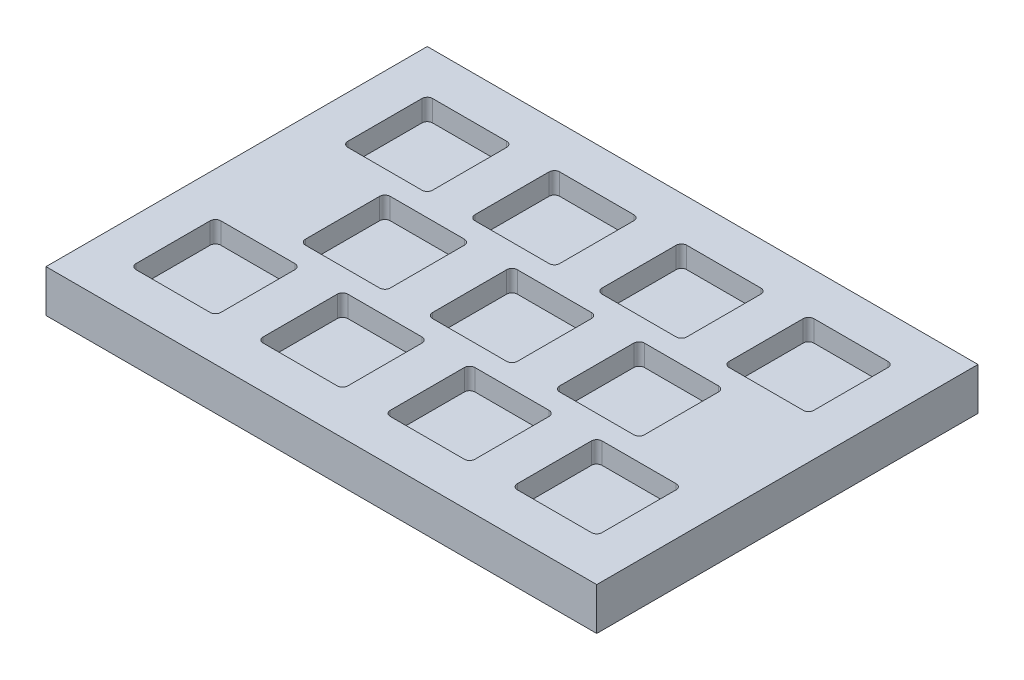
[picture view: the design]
ISO-10303-21;
HEADER;
FILE_DESCRIPTION(('STEP AP214'),'2;1');
FILE_NAME('part.step','',(''),(''),'','','');
FILE_SCHEMA(('AUTOMOTIVE_DESIGN { 1 0 10303 214 1 1 1 1 }'));
ENDSEC;
DATA;
#1=APPLICATION_CONTEXT('core data for automotive mechanical design processes');
#2=APPLICATION_PROTOCOL_DEFINITION('international standard','automotive_design',2000,#1);
#3=PRODUCT_CONTEXT('',#1,'mechanical');
#4=PRODUCT('Part','Part','',(#3));
#5=PRODUCT_RELATED_PRODUCT_CATEGORY('part','',(#4));
#6=PRODUCT_DEFINITION_FORMATION('','',#4);
#7=PRODUCT_DEFINITION_CONTEXT('part definition',#1,'design');
#8=PRODUCT_DEFINITION('design','',#6,#7);
#9=PRODUCT_DEFINITION_SHAPE('','',#8);
#10=(LENGTH_UNIT() NAMED_UNIT(*) SI_UNIT(.MILLI.,.METRE.));
#11=(NAMED_UNIT(*) PLANE_ANGLE_UNIT() SI_UNIT($,.RADIAN.));
#12=(NAMED_UNIT(*) SI_UNIT($,.STERADIAN.) SOLID_ANGLE_UNIT());
#13=UNCERTAINTY_MEASURE_WITH_UNIT(LENGTH_MEASURE(1.E-05),#10,'distance_accuracy_value','');
#14=(GEOMETRIC_REPRESENTATION_CONTEXT(3) GLOBAL_UNCERTAINTY_ASSIGNED_CONTEXT((#13)) GLOBAL_UNIT_ASSIGNED_CONTEXT((#10,
#11,#12)) REPRESENTATION_CONTEXT('',''));
#15=CARTESIAN_POINT('',(0.,0.,0.));
#16=DIRECTION('',(0.,0.,1.));
#17=DIRECTION('',(1.,0.,0.));
#18=AXIS2_PLACEMENT_3D('',#15,#16,#17);
#19=CARTESIAN_POINT('',(-82.55,12.7,57.15));
#20=DIRECTION('',(0.,1.,0.));
#21=DIRECTION('',(0.,0.,1.));
#22=AXIS2_PLACEMENT_3D('',#19,#20,#21);
#23=PLANE('',#22);
#24=DIRECTION('',(0.,0.,1.));
#25=VECTOR('',#24,1.);
#26=CARTESIAN_POINT('',(-82.55,12.7,-57.15));
#27=LINE('',#26,#25);
#28=CARTESIAN_POINT('',(-82.55,12.7,-57.15));
#29=VERTEX_POINT('',#28);
#30=CARTESIAN_POINT('',(-82.55,12.7,57.15));
#31=VERTEX_POINT('',#30);
#32=EDGE_CURVE('E902',#29,#31,#27,.T.);
#33=ORIENTED_EDGE('',*,*,#32,.T.);
#34=DIRECTION('',(1.,0.,0.));
#35=VECTOR('',#34,1.);
#36=CARTESIAN_POINT('',(-82.55,12.7,57.15));
#37=LINE('',#36,#35);
#38=CARTESIAN_POINT('',(82.55,12.7,57.15));
#39=VERTEX_POINT('',#38);
#40=EDGE_CURVE('E905',#31,#39,#37,.T.);
#41=ORIENTED_EDGE('',*,*,#40,.T.);
#42=DIRECTION('',(0.,0.,-1.));
#43=VECTOR('',#42,1.);
#44=CARTESIAN_POINT('',(82.55,12.7,-57.15));
#45=LINE('',#44,#43);
#46=CARTESIAN_POINT('',(82.55,12.7,-57.15));
#47=VERTEX_POINT('',#46);
#48=EDGE_CURVE('E907',#39,#47,#45,.T.);
#49=ORIENTED_EDGE('',*,*,#48,.T.);
#50=DIRECTION('',(-1.,0.,0.));
#51=VECTOR('',#50,1.);
#52=CARTESIAN_POINT('',(-82.55,12.7,-57.15));
#53=LINE('',#52,#51);
#54=EDGE_CURVE('E909',#47,#29,#53,.T.);
#55=ORIENTED_EDGE('',*,*,#54,.T.);
#56=EDGE_LOOP('',(#33,#41,#49,#55));
#57=FACE_BOUND('',#56,.T.);
#58=DIRECTION('',(0.,0.,-1.));
#59=VECTOR('',#58,1.);
#60=CARTESIAN_POINT('',(-44.45,12.7,-44.45));
#61=LINE('',#60,#59);
#62=CARTESIAN_POINT('',(-44.45,12.7,-20.6375));
#63=VERTEX_POINT('',#62);
#64=CARTESIAN_POINT('',(-44.45,12.7,-42.8625));
#65=VERTEX_POINT('',#64);
#66=EDGE_CURVE('E869',#63,#65,#61,.T.);
#67=ORIENTED_EDGE('',*,*,#66,.F.);
#68=CARTESIAN_POINT('',(-46.0375,12.7,-20.6375));
#69=DIRECTION('',(0.,1.,0.));
#70=DIRECTION('',(0.,0.,1.));
#71=AXIS2_PLACEMENT_3D('',#68,#69,#70);
#72=CIRCLE('',#71,1.5875);
#73=CARTESIAN_POINT('',(-46.0375,12.7,-19.05));
#74=VERTEX_POINT('',#73);
#75=EDGE_CURVE('E953',#63,#74,#72,.F.);
#76=ORIENTED_EDGE('',*,*,#75,.T.);
#77=DIRECTION('',(1.,0.,0.));
#78=VECTOR('',#77,1.);
#79=CARTESIAN_POINT('',(-44.45,12.7,-19.05));
#80=LINE('',#79,#78);
#81=CARTESIAN_POINT('',(-68.2625,12.7,-19.05));
#82=VERTEX_POINT('',#81);
#83=EDGE_CURVE('E878',#82,#74,#80,.T.);
#84=ORIENTED_EDGE('',*,*,#83,.F.);
#85=CARTESIAN_POINT('',(-68.2625,12.7,-20.6375));
#86=DIRECTION('',(0.,1.,0.));
#87=DIRECTION('',(0.,0.,1.));
#88=AXIS2_PLACEMENT_3D('',#85,#86,#87);
#89=CIRCLE('',#88,1.5875);
#90=CARTESIAN_POINT('',(-69.85,12.7,-20.6375));
#91=VERTEX_POINT('',#90);
#92=EDGE_CURVE('E951',#82,#91,#89,.F.);
#93=ORIENTED_EDGE('',*,*,#92,.T.);
#94=DIRECTION('',(0.,0.,1.));
#95=VECTOR('',#94,1.);
#96=CARTESIAN_POINT('',(-69.85,12.7,-44.45));
#97=LINE('',#96,#95);
#98=CARTESIAN_POINT('',(-69.85,12.7,-42.8625));
#99=VERTEX_POINT('',#98);
#100=EDGE_CURVE('E875',#99,#91,#97,.T.);
#101=ORIENTED_EDGE('',*,*,#100,.F.);
#102=CARTESIAN_POINT('',(-68.2625,12.7,-42.8625));
#103=DIRECTION('',(0.,1.,0.));
#104=DIRECTION('',(0.,0.,1.));
#105=AXIS2_PLACEMENT_3D('',#102,#103,#104);
#106=CIRCLE('',#105,1.5875);
#107=CARTESIAN_POINT('',(-68.2625,12.7,-44.45));
#108=VERTEX_POINT('',#107);
#109=EDGE_CURVE('E957',#99,#108,#106,.F.);
#110=ORIENTED_EDGE('',*,*,#109,.T.);
#111=DIRECTION('',(-1.,0.,0.));
#112=VECTOR('',#111,1.);
#113=CARTESIAN_POINT('',(-44.45,12.7,-44.45));
#114=LINE('',#113,#112);
#115=CARTESIAN_POINT('',(-46.0375,12.7,-44.45));
#116=VERTEX_POINT('',#115);
#117=EDGE_CURVE('E872',#116,#108,#114,.T.);
#118=ORIENTED_EDGE('',*,*,#117,.F.);
#119=CARTESIAN_POINT('',(-46.0375,12.7,-42.8625));
#120=DIRECTION('',(0.,1.,0.));
#121=DIRECTION('',(0.,0.,1.));
#122=AXIS2_PLACEMENT_3D('',#119,#120,#121);
#123=CIRCLE('',#122,1.5875);
#124=EDGE_CURVE('E955',#116,#65,#123,.F.);
#125=ORIENTED_EDGE('',*,*,#124,.T.);
#126=EDGE_LOOP('',(#67,#76,#84,#93,#101,#110,#118,#125));
#127=FACE_BOUND('',#126,.T.);
#128=DIRECTION('',(0.,0.,-1.));
#129=VECTOR('',#128,1.);
#130=CARTESIAN_POINT('',(-25.4,12.7,-12.7));
#131=LINE('',#130,#129);
#132=CARTESIAN_POINT('',(-25.4,12.7,11.1125));
#133=VERTEX_POINT('',#132);
#134=CARTESIAN_POINT('',(-25.4,12.7,-11.1125));
#135=VERTEX_POINT('',#134);
#136=EDGE_CURVE('E845',#133,#135,#131,.T.);
#137=ORIENTED_EDGE('',*,*,#136,.F.);
#138=CARTESIAN_POINT('',(-26.9875,12.7,11.1125));
#139=DIRECTION('',(0.,1.,0.));
#140=DIRECTION('',(0.,0.,1.));
#141=AXIS2_PLACEMENT_3D('',#138,#139,#140);
#142=CIRCLE('',#141,1.5875);
#143=CARTESIAN_POINT('',(-26.9875,12.7,12.7));
#144=VERTEX_POINT('',#143);
#145=EDGE_CURVE('E1241',#133,#144,#142,.F.);
#146=ORIENTED_EDGE('',*,*,#145,.T.);
#147=DIRECTION('',(1.,0.,0.));
#148=VECTOR('',#147,1.);
#149=CARTESIAN_POINT('',(-25.4,12.7,12.7));
#150=LINE('',#149,#148);
#151=CARTESIAN_POINT('',(-49.2125,12.7,12.7));
#152=VERTEX_POINT('',#151);
#153=EDGE_CURVE('E854',#152,#144,#150,.T.);
#154=ORIENTED_EDGE('',*,*,#153,.F.);
#155=CARTESIAN_POINT('',(-49.2125,12.7,11.1125));
#156=DIRECTION('',(0.,1.,0.));
#157=DIRECTION('',(0.,0.,1.));
#158=AXIS2_PLACEMENT_3D('',#155,#156,#157);
#159=CIRCLE('',#158,1.5875);
#160=CARTESIAN_POINT('',(-50.8,12.7,11.1125));
#161=VERTEX_POINT('',#160);
#162=EDGE_CURVE('E1243',#152,#161,#159,.F.);
#163=ORIENTED_EDGE('',*,*,#162,.T.);
#164=DIRECTION('',(0.,0.,1.));
#165=VECTOR('',#164,1.);
#166=CARTESIAN_POINT('',(-50.8,12.7,-12.7));
#167=LINE('',#166,#165);
#168=CARTESIAN_POINT('',(-50.8,12.7,-11.1125));
#169=VERTEX_POINT('',#168);
#170=EDGE_CURVE('E851',#169,#161,#167,.T.);
#171=ORIENTED_EDGE('',*,*,#170,.F.);
#172=CARTESIAN_POINT('',(-49.2125,12.7,-11.1125));
#173=DIRECTION('',(0.,1.,0.));
#174=DIRECTION('',(0.,0.,1.));
#175=AXIS2_PLACEMENT_3D('',#172,#173,#174);
#176=CIRCLE('',#175,1.5875);
#177=CARTESIAN_POINT('',(-49.2125,12.7,-12.7));
#178=VERTEX_POINT('',#177);
#179=EDGE_CURVE('E1245',#169,#178,#176,.F.);
#180=ORIENTED_EDGE('',*,*,#179,.T.);
#181=DIRECTION('',(-1.,0.,0.));
#182=VECTOR('',#181,1.);
#183=CARTESIAN_POINT('',(-25.4,12.7,-12.7));
#184=LINE('',#183,#182);
#185=CARTESIAN_POINT('',(-26.9875,12.7,-12.7));
#186=VERTEX_POINT('',#185);
#187=EDGE_CURVE('E848',#186,#178,#184,.T.);
#188=ORIENTED_EDGE('',*,*,#187,.F.);
#189=CARTESIAN_POINT('',(-26.9875,12.7,-11.1125));
#190=DIRECTION('',(0.,1.,0.));
#191=DIRECTION('',(0.,0.,1.));
#192=AXIS2_PLACEMENT_3D('',#189,#190,#191);
#193=CIRCLE('',#192,1.5875);
#194=EDGE_CURVE('E1239',#186,#135,#193,.F.);
#195=ORIENTED_EDGE('',*,*,#194,.T.);
#196=EDGE_LOOP('',(#137,#146,#154,#163,#171,#180,#188,#195));
#197=FACE_BOUND('',#196,.T.);
#198=DIRECTION('',(0.,0.,-1.));
#199=VECTOR('',#198,1.);
#200=CARTESIAN_POINT('',(-44.45,12.7,19.05));
#201=LINE('',#200,#199);
#202=CARTESIAN_POINT('',(-44.45,12.7,42.8625));
#203=VERTEX_POINT('',#202);
#204=CARTESIAN_POINT('',(-44.45,12.7,20.6375));
#205=VERTEX_POINT('',#204);
#206=EDGE_CURVE('E821',#203,#205,#201,.T.);
#207=ORIENTED_EDGE('',*,*,#206,.F.);
#208=CARTESIAN_POINT('',(-46.0375,12.7,42.8625));
#209=DIRECTION('',(0.,1.,0.));
#210=DIRECTION('',(0.,0.,1.));
#211=AXIS2_PLACEMENT_3D('',#208,#209,#210);
#212=CIRCLE('',#211,1.5875);
#213=CARTESIAN_POINT('',(-46.0375,12.7,44.45));
#214=VERTEX_POINT('',#213);
#215=EDGE_CURVE('E989',#203,#214,#212,.F.);
#216=ORIENTED_EDGE('',*,*,#215,.T.);
#217=DIRECTION('',(1.,0.,0.));
#218=VECTOR('',#217,1.);
#219=CARTESIAN_POINT('',(-44.45,12.7,44.45));
#220=LINE('',#219,#218);
#221=CARTESIAN_POINT('',(-68.2625,12.7,44.45));
#222=VERTEX_POINT('',#221);
#223=EDGE_CURVE('E830',#222,#214,#220,.T.);
#224=ORIENTED_EDGE('',*,*,#223,.F.);
#225=CARTESIAN_POINT('',(-68.2625,12.7,42.8625));
#226=DIRECTION('',(0.,1.,0.));
#227=DIRECTION('',(0.,0.,1.));
#228=AXIS2_PLACEMENT_3D('',#225,#226,#227);
#229=CIRCLE('',#228,1.5875);
#230=CARTESIAN_POINT('',(-69.85,12.7,42.8625));
#231=VERTEX_POINT('',#230);
#232=EDGE_CURVE('E987',#222,#231,#229,.F.);
#233=ORIENTED_EDGE('',*,*,#232,.T.);
#234=DIRECTION('',(0.,0.,1.));
#235=VECTOR('',#234,1.);
#236=CARTESIAN_POINT('',(-69.85,12.7,19.05));
#237=LINE('',#236,#235);
#238=CARTESIAN_POINT('',(-69.85,12.7,20.6375));
#239=VERTEX_POINT('',#238);
#240=EDGE_CURVE('E827',#239,#231,#237,.T.);
#241=ORIENTED_EDGE('',*,*,#240,.F.);
#242=CARTESIAN_POINT('',(-68.2625,12.7,20.6375));
#243=DIRECTION('',(0.,1.,0.));
#244=DIRECTION('',(0.,0.,1.));
#245=AXIS2_PLACEMENT_3D('',#242,#243,#244);
#246=CIRCLE('',#245,1.5875);
#247=CARTESIAN_POINT('',(-68.2625,12.7,19.05));
#248=VERTEX_POINT('',#247);
#249=EDGE_CURVE('E993',#239,#248,#246,.F.);
#250=ORIENTED_EDGE('',*,*,#249,.T.);
#251=DIRECTION('',(-1.,0.,0.));
#252=VECTOR('',#251,1.);
#253=CARTESIAN_POINT('',(-44.45,12.7,19.05));
#254=LINE('',#253,#252);
#255=CARTESIAN_POINT('',(-46.0375,12.7,19.05));
#256=VERTEX_POINT('',#255);
#257=EDGE_CURVE('E824',#256,#248,#254,.T.);
#258=ORIENTED_EDGE('',*,*,#257,.F.);
#259=CARTESIAN_POINT('',(-46.0375,12.7,20.6375));
#260=DIRECTION('',(0.,1.,0.));
#261=DIRECTION('',(0.,0.,1.));
#262=AXIS2_PLACEMENT_3D('',#259,#260,#261);
#263=CIRCLE('',#262,1.5875);
#264=EDGE_CURVE('E991',#256,#205,#263,.F.);
#265=ORIENTED_EDGE('',*,*,#264,.T.);
#266=EDGE_LOOP('',(#207,#216,#224,#233,#241,#250,#258,#265));
#267=FACE_BOUND('',#266,.T.);
#268=DIRECTION('',(0.,0.,-1.));
#269=VECTOR('',#268,1.);
#270=CARTESIAN_POINT('',(-6.34999999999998,12.7,-44.45));
#271=LINE('',#270,#269);
#272=CARTESIAN_POINT('',(-6.34999999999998,12.7,-20.6375));
#273=VERTEX_POINT('',#272);
#274=CARTESIAN_POINT('',(-6.34999999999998,12.7,-42.8625));
#275=VERTEX_POINT('',#274);
#276=EDGE_CURVE('E797',#273,#275,#271,.T.);
#277=ORIENTED_EDGE('',*,*,#276,.F.);
#278=CARTESIAN_POINT('',(-7.93749999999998,12.7,-20.6375));
#279=DIRECTION('',(0.,1.,0.));
#280=DIRECTION('',(0.,0.,1.));
#281=AXIS2_PLACEMENT_3D('',#278,#279,#280);
#282=CIRCLE('',#281,1.5875);
#283=CARTESIAN_POINT('',(-7.93749999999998,12.7,-19.05));
#284=VERTEX_POINT('',#283);
#285=EDGE_CURVE('E1025',#273,#284,#282,.F.);
#286=ORIENTED_EDGE('',*,*,#285,.T.);
#287=DIRECTION('',(1.,0.,0.));
#288=VECTOR('',#287,1.);
#289=CARTESIAN_POINT('',(-6.34999999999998,12.7,-19.05));
#290=LINE('',#289,#288);
#291=CARTESIAN_POINT('',(-30.1625,12.7,-19.05));
#292=VERTEX_POINT('',#291);
#293=EDGE_CURVE('E806',#292,#284,#290,.T.);
#294=ORIENTED_EDGE('',*,*,#293,.F.);
#295=CARTESIAN_POINT('',(-30.1625,12.7,-20.6375));
#296=DIRECTION('',(0.,1.,0.));
#297=DIRECTION('',(0.,0.,1.));
#298=AXIS2_PLACEMENT_3D('',#295,#296,#297);
#299=CIRCLE('',#298,1.5875);
#300=CARTESIAN_POINT('',(-31.75,12.7,-20.6375));
#301=VERTEX_POINT('',#300);
#302=EDGE_CURVE('E1023',#292,#301,#299,.F.);
#303=ORIENTED_EDGE('',*,*,#302,.T.);
#304=DIRECTION('',(0.,0.,1.));
#305=VECTOR('',#304,1.);
#306=CARTESIAN_POINT('',(-31.75,12.7,-44.45));
#307=LINE('',#306,#305);
#308=CARTESIAN_POINT('',(-31.75,12.7,-42.8625));
#309=VERTEX_POINT('',#308);
#310=EDGE_CURVE('E803',#309,#301,#307,.T.);
#311=ORIENTED_EDGE('',*,*,#310,.F.);
#312=CARTESIAN_POINT('',(-30.1625,12.7,-42.8625));
#313=DIRECTION('',(0.,1.,0.));
#314=DIRECTION('',(0.,0.,1.));
#315=AXIS2_PLACEMENT_3D('',#312,#313,#314);
#316=CIRCLE('',#315,1.5875);
#317=CARTESIAN_POINT('',(-30.1625,12.7,-44.45));
#318=VERTEX_POINT('',#317);
#319=EDGE_CURVE('E1029',#309,#318,#316,.F.);
#320=ORIENTED_EDGE('',*,*,#319,.T.);
#321=DIRECTION('',(-1.,0.,0.));
#322=VECTOR('',#321,1.);
#323=CARTESIAN_POINT('',(-6.34999999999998,12.7,-44.45));
#324=LINE('',#323,#322);
#325=CARTESIAN_POINT('',(-7.93749999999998,12.7,-44.45));
#326=VERTEX_POINT('',#325);
#327=EDGE_CURVE('E800',#326,#318,#324,.T.);
#328=ORIENTED_EDGE('',*,*,#327,.F.);
#329=CARTESIAN_POINT('',(-7.93749999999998,12.7,-42.8625));
#330=DIRECTION('',(0.,1.,0.));
#331=DIRECTION('',(0.,0.,1.));
#332=AXIS2_PLACEMENT_3D('',#329,#330,#331);
#333=CIRCLE('',#332,1.5875);
#334=EDGE_CURVE('E1027',#326,#275,#333,.F.);
#335=ORIENTED_EDGE('',*,*,#334,.T.);
#336=EDGE_LOOP('',(#277,#286,#294,#303,#311,#320,#328,#335));
#337=FACE_BOUND('',#336,.T.);
#338=DIRECTION('',(0.,0.,-1.));
#339=VECTOR('',#338,1.);
#340=CARTESIAN_POINT('',(-6.34999999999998,12.7,19.05));
#341=LINE('',#340,#339);
#342=CARTESIAN_POINT('',(-6.34999999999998,12.7,42.8625));
#343=VERTEX_POINT('',#342);
#344=CARTESIAN_POINT('',(-6.34999999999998,12.7,20.6375));
#345=VERTEX_POINT('',#344);
#346=EDGE_CURVE('E773',#343,#345,#341,.T.);
#347=ORIENTED_EDGE('',*,*,#346,.F.);
#348=CARTESIAN_POINT('',(-7.93749999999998,12.7,42.8625));
#349=DIRECTION('',(0.,1.,0.));
#350=DIRECTION('',(0.,0.,1.));
#351=AXIS2_PLACEMENT_3D('',#348,#349,#350);
#352=CIRCLE('',#351,1.5875);
#353=CARTESIAN_POINT('',(-7.93749999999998,12.7,44.45));
#354=VERTEX_POINT('',#353);
#355=EDGE_CURVE('E1061',#343,#354,#352,.F.);
#356=ORIENTED_EDGE('',*,*,#355,.T.);
#357=DIRECTION('',(1.,0.,0.));
#358=VECTOR('',#357,1.);
#359=CARTESIAN_POINT('',(-6.34999999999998,12.7,44.45));
#360=LINE('',#359,#358);
#361=CARTESIAN_POINT('',(-30.1625,12.7,44.45));
#362=VERTEX_POINT('',#361);
#363=EDGE_CURVE('E782',#362,#354,#360,.T.);
#364=ORIENTED_EDGE('',*,*,#363,.F.);
#365=CARTESIAN_POINT('',(-30.1625,12.7,42.8625));
#366=DIRECTION('',(0.,1.,0.));
#367=DIRECTION('',(0.,0.,1.));
#368=AXIS2_PLACEMENT_3D('',#365,#366,#367);
#369=CIRCLE('',#368,1.5875);
#370=CARTESIAN_POINT('',(-31.75,12.7,42.8625));
#371=VERTEX_POINT('',#370);
#372=EDGE_CURVE('E1059',#362,#371,#369,.F.);
#373=ORIENTED_EDGE('',*,*,#372,.T.);
#374=DIRECTION('',(0.,0.,1.));
#375=VECTOR('',#374,1.);
#376=CARTESIAN_POINT('',(-31.75,12.7,19.05));
#377=LINE('',#376,#375);
#378=CARTESIAN_POINT('',(-31.75,12.7,20.6375));
#379=VERTEX_POINT('',#378);
#380=EDGE_CURVE('E779',#379,#371,#377,.T.);
#381=ORIENTED_EDGE('',*,*,#380,.F.);
#382=CARTESIAN_POINT('',(-30.1625,12.7,20.6375));
#383=DIRECTION('',(0.,1.,0.));
#384=DIRECTION('',(0.,0.,1.));
#385=AXIS2_PLACEMENT_3D('',#382,#383,#384);
#386=CIRCLE('',#385,1.5875);
#387=CARTESIAN_POINT('',(-30.1625,12.7,19.05));
#388=VERTEX_POINT('',#387);
#389=EDGE_CURVE('E1065',#379,#388,#386,.F.);
#390=ORIENTED_EDGE('',*,*,#389,.T.);
#391=DIRECTION('',(-1.,0.,0.));
#392=VECTOR('',#391,1.);
#393=CARTESIAN_POINT('',(-6.34999999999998,12.7,19.05));
#394=LINE('',#393,#392);
#395=CARTESIAN_POINT('',(-7.93749999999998,12.7,19.05));
#396=VERTEX_POINT('',#395);
#397=EDGE_CURVE('E776',#396,#388,#394,.T.);
#398=ORIENTED_EDGE('',*,*,#397,.F.);
#399=CARTESIAN_POINT('',(-7.93749999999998,12.7,20.6375));
#400=DIRECTION('',(0.,1.,0.));
#401=DIRECTION('',(0.,0.,1.));
#402=AXIS2_PLACEMENT_3D('',#399,#400,#401);
#403=CIRCLE('',#402,1.5875);
#404=EDGE_CURVE('E1063',#396,#345,#403,.F.);
#405=ORIENTED_EDGE('',*,*,#404,.T.);
#406=EDGE_LOOP('',(#347,#356,#364,#373,#381,#390,#398,#405));
#407=FACE_BOUND('',#406,.T.);
#408=DIRECTION('',(0.,0.,-1.));
#409=VECTOR('',#408,1.);
#410=CARTESIAN_POINT('',(31.75,12.7,-44.45));
#411=LINE('',#410,#409);
#412=CARTESIAN_POINT('',(31.75,12.7,-20.6375));
#413=VERTEX_POINT('',#412);
#414=CARTESIAN_POINT('',(31.75,12.7,-42.8625));
#415=VERTEX_POINT('',#414);
#416=EDGE_CURVE('E749',#413,#415,#411,.T.);
#417=ORIENTED_EDGE('',*,*,#416,.F.);
#418=CARTESIAN_POINT('',(30.1625,12.7,-20.6375));
#419=DIRECTION('',(0.,1.,0.));
#420=DIRECTION('',(0.,0.,1.));
#421=AXIS2_PLACEMENT_3D('',#418,#419,#420);
#422=CIRCLE('',#421,1.5875);
#423=CARTESIAN_POINT('',(30.1625,12.7,-19.05));
#424=VERTEX_POINT('',#423);
#425=EDGE_CURVE('E1097',#413,#424,#422,.F.);
#426=ORIENTED_EDGE('',*,*,#425,.T.);
#427=DIRECTION('',(1.,0.,0.));
#428=VECTOR('',#427,1.);
#429=CARTESIAN_POINT('',(31.75,12.7,-19.05));
#430=LINE('',#429,#428);
#431=CARTESIAN_POINT('',(7.93750000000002,12.7,-19.05));
#432=VERTEX_POINT('',#431);
#433=EDGE_CURVE('E758',#432,#424,#430,.T.);
#434=ORIENTED_EDGE('',*,*,#433,.F.);
#435=CARTESIAN_POINT('',(7.93750000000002,12.7,-20.6375));
#436=DIRECTION('',(0.,1.,0.));
#437=DIRECTION('',(0.,0.,1.));
#438=AXIS2_PLACEMENT_3D('',#435,#436,#437);
#439=CIRCLE('',#438,1.5875);
#440=CARTESIAN_POINT('',(6.35000000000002,12.7,-20.6375));
#441=VERTEX_POINT('',#440);
#442=EDGE_CURVE('E1095',#432,#441,#439,.F.);
#443=ORIENTED_EDGE('',*,*,#442,.T.);
#444=DIRECTION('',(0.,0.,1.));
#445=VECTOR('',#444,1.);
#446=CARTESIAN_POINT('',(6.35000000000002,12.7,-44.45));
#447=LINE('',#446,#445);
#448=CARTESIAN_POINT('',(6.35000000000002,12.7,-42.8625));
#449=VERTEX_POINT('',#448);
#450=EDGE_CURVE('E755',#449,#441,#447,.T.);
#451=ORIENTED_EDGE('',*,*,#450,.F.);
#452=CARTESIAN_POINT('',(7.93750000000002,12.7,-42.8625));
#453=DIRECTION('',(0.,1.,0.));
#454=DIRECTION('',(0.,0.,1.));
#455=AXIS2_PLACEMENT_3D('',#452,#453,#454);
#456=CIRCLE('',#455,1.5875);
#457=CARTESIAN_POINT('',(7.93750000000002,12.7,-44.45));
#458=VERTEX_POINT('',#457);
#459=EDGE_CURVE('E1101',#449,#458,#456,.F.);
#460=ORIENTED_EDGE('',*,*,#459,.T.);
#461=DIRECTION('',(-1.,0.,0.));
#462=VECTOR('',#461,1.);
#463=CARTESIAN_POINT('',(31.75,12.7,-44.45));
#464=LINE('',#463,#462);
#465=CARTESIAN_POINT('',(30.1625,12.7,-44.45));
#466=VERTEX_POINT('',#465);
#467=EDGE_CURVE('E752',#466,#458,#464,.T.);
#468=ORIENTED_EDGE('',*,*,#467,.F.);
#469=CARTESIAN_POINT('',(30.1625,12.7,-42.8625));
#470=DIRECTION('',(0.,1.,0.));
#471=DIRECTION('',(0.,0.,1.));
#472=AXIS2_PLACEMENT_3D('',#469,#470,#471);
#473=CIRCLE('',#472,1.5875);
#474=EDGE_CURVE('E1099',#466,#415,#473,.F.);
#475=ORIENTED_EDGE('',*,*,#474,.T.);
#476=EDGE_LOOP('',(#417,#426,#434,#443,#451,#460,#468,#475));
#477=FACE_BOUND('',#476,.T.);
#478=DIRECTION('',(0.,0.,-1.));
#479=VECTOR('',#478,1.);
#480=CARTESIAN_POINT('',(31.75,12.7,19.05));
#481=LINE('',#480,#479);
#482=CARTESIAN_POINT('',(31.75,12.7,42.8625));
#483=VERTEX_POINT('',#482);
#484=CARTESIAN_POINT('',(31.75,12.7,20.6375));
#485=VERTEX_POINT('',#484);
#486=EDGE_CURVE('E725',#483,#485,#481,.T.);
#487=ORIENTED_EDGE('',*,*,#486,.F.);
#488=CARTESIAN_POINT('',(30.1625,12.7,42.8625));
#489=DIRECTION('',(0.,1.,0.));
#490=DIRECTION('',(0.,0.,1.));
#491=AXIS2_PLACEMENT_3D('',#488,#489,#490);
#492=CIRCLE('',#491,1.5875);
#493=CARTESIAN_POINT('',(30.1625,12.7,44.45));
#494=VERTEX_POINT('',#493);
#495=EDGE_CURVE('E1133',#483,#494,#492,.F.);
#496=ORIENTED_EDGE('',*,*,#495,.T.);
#497=DIRECTION('',(1.,0.,0.));
#498=VECTOR('',#497,1.);
#499=CARTESIAN_POINT('',(31.75,12.7,44.45));
#500=LINE('',#499,#498);
#501=CARTESIAN_POINT('',(7.93750000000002,12.7,44.45));
#502=VERTEX_POINT('',#501);
#503=EDGE_CURVE('E734',#502,#494,#500,.T.);
#504=ORIENTED_EDGE('',*,*,#503,.F.);
#505=CARTESIAN_POINT('',(7.93750000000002,12.7,42.8625));
#506=DIRECTION('',(0.,1.,0.));
#507=DIRECTION('',(0.,0.,1.));
#508=AXIS2_PLACEMENT_3D('',#505,#506,#507);
#509=CIRCLE('',#508,1.5875);
#510=CARTESIAN_POINT('',(6.35000000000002,12.7,42.8625));
#511=VERTEX_POINT('',#510);
#512=EDGE_CURVE('E1131',#502,#511,#509,.F.);
#513=ORIENTED_EDGE('',*,*,#512,.T.);
#514=DIRECTION('',(0.,0.,1.));
#515=VECTOR('',#514,1.);
#516=CARTESIAN_POINT('',(6.35000000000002,12.7,19.05));
#517=LINE('',#516,#515);
#518=CARTESIAN_POINT('',(6.35000000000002,12.7,20.6375));
#519=VERTEX_POINT('',#518);
#520=EDGE_CURVE('E731',#519,#511,#517,.T.);
#521=ORIENTED_EDGE('',*,*,#520,.F.);
#522=CARTESIAN_POINT('',(7.93750000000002,12.7,20.6375));
#523=DIRECTION('',(0.,1.,0.));
#524=DIRECTION('',(0.,0.,1.));
#525=AXIS2_PLACEMENT_3D('',#522,#523,#524);
#526=CIRCLE('',#525,1.5875);
#527=CARTESIAN_POINT('',(7.93750000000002,12.7,19.05));
#528=VERTEX_POINT('',#527);
#529=EDGE_CURVE('E1137',#519,#528,#526,.F.);
#530=ORIENTED_EDGE('',*,*,#529,.T.);
#531=DIRECTION('',(-1.,0.,0.));
#532=VECTOR('',#531,1.);
#533=CARTESIAN_POINT('',(31.75,12.7,19.05));
#534=LINE('',#533,#532);
#535=CARTESIAN_POINT('',(30.1625,12.7,19.05));
#536=VERTEX_POINT('',#535);
#537=EDGE_CURVE('E728',#536,#528,#534,.T.);
#538=ORIENTED_EDGE('',*,*,#537,.F.);
#539=CARTESIAN_POINT('',(30.1625,12.7,20.6375));
#540=DIRECTION('',(0.,1.,0.));
#541=DIRECTION('',(0.,0.,1.));
#542=AXIS2_PLACEMENT_3D('',#539,#540,#541);
#543=CIRCLE('',#542,1.5875);
#544=EDGE_CURVE('E1135',#536,#485,#543,.F.);
#545=ORIENTED_EDGE('',*,*,#544,.T.);
#546=EDGE_LOOP('',(#487,#496,#504,#513,#521,#530,#538,#545));
#547=FACE_BOUND('',#546,.T.);
#548=DIRECTION('',(0.,0.,-1.));
#549=VECTOR('',#548,1.);
#550=CARTESIAN_POINT('',(69.85,12.7,-44.45));
#551=LINE('',#550,#549);
#552=CARTESIAN_POINT('',(69.85,12.7,-20.6375));
#553=VERTEX_POINT('',#552);
#554=CARTESIAN_POINT('',(69.85,12.7,-42.8625));
#555=VERTEX_POINT('',#554);
#556=EDGE_CURVE('E701',#553,#555,#551,.T.);
#557=ORIENTED_EDGE('',*,*,#556,.F.);
#558=CARTESIAN_POINT('',(68.2625,12.7,-20.6375));
#559=DIRECTION('',(0.,1.,0.));
#560=DIRECTION('',(0.,0.,1.));
#561=AXIS2_PLACEMENT_3D('',#558,#559,#560);
#562=CIRCLE('',#561,1.5875);
#563=CARTESIAN_POINT('',(68.2625,12.7,-19.05));
#564=VERTEX_POINT('',#563);
#565=EDGE_CURVE('E1169',#553,#564,#562,.F.);
#566=ORIENTED_EDGE('',*,*,#565,.T.);
#567=DIRECTION('',(1.,0.,0.));
#568=VECTOR('',#567,1.);
#569=CARTESIAN_POINT('',(69.85,12.7,-19.05));
#570=LINE('',#569,#568);
#571=CARTESIAN_POINT('',(46.0375,12.7,-19.05));
#572=VERTEX_POINT('',#571);
#573=EDGE_CURVE('E710',#572,#564,#570,.T.);
#574=ORIENTED_EDGE('',*,*,#573,.F.);
#575=CARTESIAN_POINT('',(46.0375,12.7,-20.6375));
#576=DIRECTION('',(0.,1.,0.));
#577=DIRECTION('',(0.,0.,1.));
#578=AXIS2_PLACEMENT_3D('',#575,#576,#577);
#579=CIRCLE('',#578,1.5875);
#580=CARTESIAN_POINT('',(44.45,12.7,-20.6375));
#581=VERTEX_POINT('',#580);
#582=EDGE_CURVE('E1167',#572,#581,#579,.F.);
#583=ORIENTED_EDGE('',*,*,#582,.T.);
#584=DIRECTION('',(0.,0.,1.));
#585=VECTOR('',#584,1.);
#586=CARTESIAN_POINT('',(44.45,12.7,-44.45));
#587=LINE('',#586,#585);
#588=CARTESIAN_POINT('',(44.45,12.7,-42.8625));
#589=VERTEX_POINT('',#588);
#590=EDGE_CURVE('E707',#589,#581,#587,.T.);
#591=ORIENTED_EDGE('',*,*,#590,.F.);
#592=CARTESIAN_POINT('',(46.0375,12.7,-42.8625));
#593=DIRECTION('',(0.,1.,0.));
#594=DIRECTION('',(0.,0.,1.));
#595=AXIS2_PLACEMENT_3D('',#592,#593,#594);
#596=CIRCLE('',#595,1.5875);
#597=CARTESIAN_POINT('',(46.0375,12.7,-44.45));
#598=VERTEX_POINT('',#597);
#599=EDGE_CURVE('E1173',#589,#598,#596,.F.);
#600=ORIENTED_EDGE('',*,*,#599,.T.);
#601=DIRECTION('',(-1.,0.,0.));
#602=VECTOR('',#601,1.);
#603=CARTESIAN_POINT('',(69.85,12.7,-44.45));
#604=LINE('',#603,#602);
#605=CARTESIAN_POINT('',(68.2625,12.7,-44.45));
#606=VERTEX_POINT('',#605);
#607=EDGE_CURVE('E704',#606,#598,#604,.T.);
#608=ORIENTED_EDGE('',*,*,#607,.F.);
#609=CARTESIAN_POINT('',(68.2625,12.7,-42.8625));
#610=DIRECTION('',(0.,1.,0.));
#611=DIRECTION('',(0.,0.,1.));
#612=AXIS2_PLACEMENT_3D('',#609,#610,#611);
#613=CIRCLE('',#612,1.5875);
#614=EDGE_CURVE('E1171',#606,#555,#613,.F.);
#615=ORIENTED_EDGE('',*,*,#614,.T.);
#616=EDGE_LOOP('',(#557,#566,#574,#583,#591,#600,#608,#615));
#617=FACE_BOUND('',#616,.T.);
#618=DIRECTION('',(0.,0.,-1.));
#619=VECTOR('',#618,1.);
#620=CARTESIAN_POINT('',(69.85,12.7,19.05));
#621=LINE('',#620,#619);
#622=CARTESIAN_POINT('',(69.85,12.7,42.8625));
#623=VERTEX_POINT('',#622);
#624=CARTESIAN_POINT('',(69.85,12.7,20.6375));
#625=VERTEX_POINT('',#624);
#626=EDGE_CURVE('E677',#623,#625,#621,.T.);
#627=ORIENTED_EDGE('',*,*,#626,.F.);
#628=CARTESIAN_POINT('',(68.2625,12.7,42.8625));
#629=DIRECTION('',(0.,1.,0.));
#630=DIRECTION('',(0.,0.,1.));
#631=AXIS2_PLACEMENT_3D('',#628,#629,#630);
#632=CIRCLE('',#631,1.5875);
#633=CARTESIAN_POINT('',(68.2625,12.7,44.45));
#634=VERTEX_POINT('',#633);
#635=EDGE_CURVE('E1205',#623,#634,#632,.F.);
#636=ORIENTED_EDGE('',*,*,#635,.T.);
#637=DIRECTION('',(1.,0.,0.));
#638=VECTOR('',#637,1.);
#639=CARTESIAN_POINT('',(69.85,12.7,44.45));
#640=LINE('',#639,#638);
#641=CARTESIAN_POINT('',(46.0375,12.7,44.45));
#642=VERTEX_POINT('',#641);
#643=EDGE_CURVE('E686',#642,#634,#640,.T.);
#644=ORIENTED_EDGE('',*,*,#643,.F.);
#645=CARTESIAN_POINT('',(46.0375,12.7,42.8625));
#646=DIRECTION('',(0.,1.,0.));
#647=DIRECTION('',(0.,0.,1.));
#648=AXIS2_PLACEMENT_3D('',#645,#646,#647);
#649=CIRCLE('',#648,1.5875);
#650=CARTESIAN_POINT('',(44.45,12.7,42.8625));
#651=VERTEX_POINT('',#650);
#652=EDGE_CURVE('E1203',#642,#651,#649,.F.);
#653=ORIENTED_EDGE('',*,*,#652,.T.);
#654=DIRECTION('',(0.,0.,1.));
#655=VECTOR('',#654,1.);
#656=CARTESIAN_POINT('',(44.45,12.7,19.05));
#657=LINE('',#656,#655);
#658=CARTESIAN_POINT('',(44.45,12.7,20.6375));
#659=VERTEX_POINT('',#658);
#660=EDGE_CURVE('E683',#659,#651,#657,.T.);
#661=ORIENTED_EDGE('',*,*,#660,.F.);
#662=CARTESIAN_POINT('',(46.0375,12.7,20.6375));
#663=DIRECTION('',(0.,1.,0.));
#664=DIRECTION('',(0.,0.,1.));
#665=AXIS2_PLACEMENT_3D('',#662,#663,#664);
#666=CIRCLE('',#665,1.5875);
#667=CARTESIAN_POINT('',(46.0375,12.7,19.05));
#668=VERTEX_POINT('',#667);
#669=EDGE_CURVE('E1209',#659,#668,#666,.F.);
#670=ORIENTED_EDGE('',*,*,#669,.T.);
#671=DIRECTION('',(-1.,0.,0.));
#672=VECTOR('',#671,1.);
#673=CARTESIAN_POINT('',(69.85,12.7,19.05));
#674=LINE('',#673,#672);
#675=CARTESIAN_POINT('',(68.2625,12.7,19.05));
#676=VERTEX_POINT('',#675);
#677=EDGE_CURVE('E680',#676,#668,#674,.T.);
#678=ORIENTED_EDGE('',*,*,#677,.F.);
#679=CARTESIAN_POINT('',(68.2625,12.7,20.6375));
#680=DIRECTION('',(0.,1.,0.));
#681=DIRECTION('',(0.,0.,1.));
#682=AXIS2_PLACEMENT_3D('',#679,#680,#681);
#683=CIRCLE('',#682,1.5875);
#684=EDGE_CURVE('E1207',#676,#625,#683,.F.);
#685=ORIENTED_EDGE('',*,*,#684,.T.);
#686=EDGE_LOOP('',(#627,#636,#644,#653,#661,#670,#678,#685));
#687=FACE_BOUND('',#686,.T.);
#688=DIRECTION('',(1.,0.,0.));
#689=VECTOR('',#688,1.);
#690=CARTESIAN_POINT('',(12.7,12.7,12.7));
#691=LINE('',#690,#689);
#692=CARTESIAN_POINT('',(-11.1125,12.7,12.7));
#693=VERTEX_POINT('',#692);
#694=CARTESIAN_POINT('',(11.1125,12.7,12.7));
#695=VERTEX_POINT('',#694);
#696=EDGE_CURVE('E655',#693,#695,#691,.T.);
#697=ORIENTED_EDGE('',*,*,#696,.F.);
#698=CARTESIAN_POINT('',(-11.1125,12.7,11.1125));
#699=DIRECTION('',(0.,1.,0.));
#700=DIRECTION('',(0.,0.,1.));
#701=AXIS2_PLACEMENT_3D('',#698,#699,#700);
#702=CIRCLE('',#701,1.5875);
#703=CARTESIAN_POINT('',(-12.7,12.7,11.1125));
#704=VERTEX_POINT('',#703);
#705=EDGE_CURVE('E646',#693,#704,#702,.F.);
#706=ORIENTED_EDGE('',*,*,#705,.T.);
#707=DIRECTION('',(0.,0.,1.));
#708=VECTOR('',#707,1.);
#709=CARTESIAN_POINT('',(-12.7,12.7,-12.7));
#710=LINE('',#709,#708);
#711=CARTESIAN_POINT('',(-12.7,12.7,-11.1125));
#712=VERTEX_POINT('',#711);
#713=EDGE_CURVE('E652',#712,#704,#710,.T.);
#714=ORIENTED_EDGE('',*,*,#713,.F.);
#715=CARTESIAN_POINT('',(-11.1125,12.7,-11.1125));
#716=DIRECTION('',(0.,1.,0.));
#717=DIRECTION('',(0.,0.,1.));
#718=AXIS2_PLACEMENT_3D('',#715,#716,#717);
#719=CIRCLE('',#718,1.5875);
#720=CARTESIAN_POINT('',(-11.1125,12.7,-12.7));
#721=VERTEX_POINT('',#720);
#722=EDGE_CURVE('E615',#712,#721,#719,.F.);
#723=ORIENTED_EDGE('',*,*,#722,.T.);
#724=DIRECTION('',(-1.,0.,0.));
#725=VECTOR('',#724,1.);
#726=CARTESIAN_POINT('',(12.7,12.7,-12.7));
#727=LINE('',#726,#725);
#728=CARTESIAN_POINT('',(11.1125,12.7,-12.7));
#729=VERTEX_POINT('',#728);
#730=EDGE_CURVE('E624',#729,#721,#727,.T.);
#731=ORIENTED_EDGE('',*,*,#730,.F.);
#732=CARTESIAN_POINT('',(11.1125,12.7,-11.1125));
#733=DIRECTION('',(0.,1.,0.));
#734=DIRECTION('',(0.,0.,1.));
#735=AXIS2_PLACEMENT_3D('',#732,#733,#734);
#736=CIRCLE('',#735,1.5875);
#737=CARTESIAN_POINT('',(12.7,12.7,-11.1125));
#738=VERTEX_POINT('',#737);
#739=EDGE_CURVE('E671',#729,#738,#736,.F.);
#740=ORIENTED_EDGE('',*,*,#739,.T.);
#741=DIRECTION('',(0.,0.,-1.));
#742=VECTOR('',#741,1.);
#743=CARTESIAN_POINT('',(12.7,12.7,-12.7));
#744=LINE('',#743,#742);
#745=CARTESIAN_POINT('',(12.7,12.7,11.1125));
#746=VERTEX_POINT('',#745);
#747=EDGE_CURVE('E666',#746,#738,#744,.T.);
#748=ORIENTED_EDGE('',*,*,#747,.F.);
#749=CARTESIAN_POINT('',(11.1125,12.7,11.1125));
#750=DIRECTION('',(0.,1.,0.));
#751=DIRECTION('',(0.,0.,1.));
#752=AXIS2_PLACEMENT_3D('',#749,#750,#751);
#753=CIRCLE('',#752,1.5875);
#754=EDGE_CURVE('E660',#746,#695,#753,.F.);
#755=ORIENTED_EDGE('',*,*,#754,.T.);
#756=EDGE_LOOP('',(#697,#706,#714,#723,#731,#740,#748,#755));
#757=FACE_BOUND('',#756,.T.);
#758=DIRECTION('',(-1.,0.,0.));
#759=VECTOR('',#758,1.);
#760=CARTESIAN_POINT('',(50.8,12.7,-12.7));
#761=LINE('',#760,#759);
#762=CARTESIAN_POINT('',(49.2125,12.7,-12.7));
#763=VERTEX_POINT('',#762);
#764=CARTESIAN_POINT('',(26.9875,12.7,-12.7));
#765=VERTEX_POINT('',#764);
#766=EDGE_CURVE('E1247',#763,#765,#761,.T.);
#767=ORIENTED_EDGE('',*,*,#766,.F.);
#768=CARTESIAN_POINT('',(49.2125,12.7,-11.1125));
#769=DIRECTION('',(0.,1.,0.));
#770=DIRECTION('',(0.,0.,1.));
#771=AXIS2_PLACEMENT_3D('',#768,#769,#770);
#772=CIRCLE('',#771,1.5875);
#773=CARTESIAN_POINT('',(50.8,12.7,-11.1125));
#774=VERTEX_POINT('',#773);
#775=EDGE_CURVE('E1249',#763,#774,#772,.F.);
#776=ORIENTED_EDGE('',*,*,#775,.T.);
#777=DIRECTION('',(0.,0.,-1.));
#778=VECTOR('',#777,1.);
#779=CARTESIAN_POINT('',(50.8,12.7,-12.7));
#780=LINE('',#779,#778);
#781=CARTESIAN_POINT('',(50.8,12.7,11.1125));
#782=VERTEX_POINT('',#781);
#783=EDGE_CURVE('E1251',#782,#774,#780,.T.);
#784=ORIENTED_EDGE('',*,*,#783,.F.);
#785=CARTESIAN_POINT('',(49.2125,12.7,11.1125));
#786=DIRECTION('',(0.,1.,0.));
#787=DIRECTION('',(0.,0.,1.));
#788=AXIS2_PLACEMENT_3D('',#785,#786,#787);
#789=CIRCLE('',#788,1.5875);
#790=CARTESIAN_POINT('',(49.2125,12.7,12.7));
#791=VERTEX_POINT('',#790);
#792=EDGE_CURVE('E1254',#782,#791,#789,.F.);
#793=ORIENTED_EDGE('',*,*,#792,.T.);
#794=DIRECTION('',(1.,0.,0.));
#795=VECTOR('',#794,1.);
#796=CARTESIAN_POINT('',(50.8,12.7,12.7));
#797=LINE('',#796,#795);
#798=CARTESIAN_POINT('',(26.9875,12.7,12.7));
#799=VERTEX_POINT('',#798);
#800=EDGE_CURVE('E1256',#799,#791,#797,.T.);
#801=ORIENTED_EDGE('',*,*,#800,.F.);
#802=CARTESIAN_POINT('',(26.9875,12.7,11.1125));
#803=DIRECTION('',(0.,1.,0.));
#804=DIRECTION('',(0.,0.,1.));
#805=AXIS2_PLACEMENT_3D('',#802,#803,#804);
#806=CIRCLE('',#805,1.5875);
#807=CARTESIAN_POINT('',(25.4,12.7,11.1125));
#808=VERTEX_POINT('',#807);
#809=EDGE_CURVE('E1259',#799,#808,#806,.F.);
#810=ORIENTED_EDGE('',*,*,#809,.T.);
#811=DIRECTION('',(0.,0.,1.));
#812=VECTOR('',#811,1.);
#813=CARTESIAN_POINT('',(25.4,12.7,-12.7));
#814=LINE('',#813,#812);
#815=CARTESIAN_POINT('',(25.4,12.7,-11.1125));
#816=VERTEX_POINT('',#815);
#817=EDGE_CURVE('E1261',#816,#808,#814,.T.);
#818=ORIENTED_EDGE('',*,*,#817,.F.);
#819=CARTESIAN_POINT('',(26.9875,12.7,-11.1125));
#820=DIRECTION('',(0.,1.,0.));
#821=DIRECTION('',(0.,0.,1.));
#822=AXIS2_PLACEMENT_3D('',#819,#820,#821);
#823=CIRCLE('',#822,1.5875);
#824=EDGE_CURVE('E1263',#816,#765,#823,.F.);
#825=ORIENTED_EDGE('',*,*,#824,.T.);
#826=EDGE_LOOP('',(#767,#776,#784,#793,#801,#810,#818,#825));
#827=FACE_BOUND('',#826,.T.);
#828=ADVANCED_FACE('F36',(#57,#127,#197,#267,#337,#407,#477,#547,#617,#687,#757,#827),#23,.T.);
#829=CARTESIAN_POINT('',(-82.55,12.7,-57.15));
#830=DIRECTION('',(1.,0.,0.));
#831=DIRECTION('',(0.,0.,-1.));
#832=AXIS2_PLACEMENT_3D('',#829,#830,#831);
#833=PLANE('',#832);
#834=DIRECTION('',(0.,0.,1.));
#835=VECTOR('',#834,1.);
#836=CARTESIAN_POINT('',(-82.55,0.,-57.15));
#837=LINE('',#836,#835);
#838=CARTESIAN_POINT('',(-82.55,0.,-57.15));
#839=VERTEX_POINT('',#838);
#840=CARTESIAN_POINT('',(-82.55,0.,57.15));
#841=VERTEX_POINT('',#840);
#842=EDGE_CURVE('E893',#839,#841,#837,.T.);
#843=ORIENTED_EDGE('',*,*,#842,.T.);
#844=DIRECTION('',(0.,-1.,0.));
#845=VECTOR('',#844,1.);
#846=CARTESIAN_POINT('',(-82.55,12.7,57.15));
#847=LINE('',#846,#845);
#848=EDGE_CURVE('E920',#31,#841,#847,.T.);
#849=ORIENTED_EDGE('',*,*,#848,.F.);
#850=ORIENTED_EDGE('',*,*,#32,.F.);
#851=DIRECTION('',(0.,-1.,0.));
#852=VECTOR('',#851,1.);
#853=CARTESIAN_POINT('',(-82.55,12.7,-57.15));
#854=LINE('',#853,#852);
#855=EDGE_CURVE('E911',#29,#839,#854,.T.);
#856=ORIENTED_EDGE('',*,*,#855,.T.);
#857=EDGE_LOOP('',(#843,#849,#850,#856));
#858=FACE_BOUND('',#857,.T.);
#859=ADVANCED_FACE('F1332',(#858),#833,.F.);
#860=CARTESIAN_POINT('',(-82.55,12.7,57.15));
#861=DIRECTION('',(0.,0.,-1.));
#862=DIRECTION('',(-1.,0.,0.));
#863=AXIS2_PLACEMENT_3D('',#860,#861,#862);
#864=PLANE('',#863);
#865=DIRECTION('',(1.,0.,0.));
#866=VECTOR('',#865,1.);
#867=CARTESIAN_POINT('',(-82.55,0.,57.15));
#868=LINE('',#867,#866);
#869=CARTESIAN_POINT('',(82.55,0.,57.15));
#870=VERTEX_POINT('',#869);
#871=EDGE_CURVE('E896',#841,#870,#868,.T.);
#872=ORIENTED_EDGE('',*,*,#871,.T.);
#873=DIRECTION('',(0.,-1.,0.));
#874=VECTOR('',#873,1.);
#875=CARTESIAN_POINT('',(82.55,12.7,57.15));
#876=LINE('',#875,#874);
#877=EDGE_CURVE('E917',#39,#870,#876,.T.);
#878=ORIENTED_EDGE('',*,*,#877,.F.);
#879=ORIENTED_EDGE('',*,*,#40,.F.);
#880=ORIENTED_EDGE('',*,*,#848,.T.);
#881=EDGE_LOOP('',(#872,#878,#879,#880));
#882=FACE_BOUND('',#881,.T.);
#883=ADVANCED_FACE('F1338',(#882),#864,.F.);
#884=CARTESIAN_POINT('',(82.55,12.7,-57.15));
#885=DIRECTION('',(-1.,0.,0.));
#886=DIRECTION('',(0.,0.,1.));
#887=AXIS2_PLACEMENT_3D('',#884,#885,#886);
#888=PLANE('',#887);
#889=DIRECTION('',(0.,0.,-1.));
#890=VECTOR('',#889,1.);
#891=CARTESIAN_POINT('',(82.55,0.,-57.15));
#892=LINE('',#891,#890);
#893=CARTESIAN_POINT('',(82.55,0.,-57.15));
#894=VERTEX_POINT('',#893);
#895=EDGE_CURVE('E898',#870,#894,#892,.T.);
#896=ORIENTED_EDGE('',*,*,#895,.T.);
#897=DIRECTION('',(0.,-1.,0.));
#898=VECTOR('',#897,1.);
#899=CARTESIAN_POINT('',(82.55,12.7,-57.15));
#900=LINE('',#899,#898);
#901=EDGE_CURVE('E914',#47,#894,#900,.T.);
#902=ORIENTED_EDGE('',*,*,#901,.F.);
#903=ORIENTED_EDGE('',*,*,#48,.F.);
#904=ORIENTED_EDGE('',*,*,#877,.T.);
#905=EDGE_LOOP('',(#896,#902,#903,#904));
#906=FACE_BOUND('',#905,.T.);
#907=ADVANCED_FACE('F1349',(#906),#888,.F.);
#908=CARTESIAN_POINT('',(-82.55,12.7,-57.15));
#909=DIRECTION('',(0.,0.,1.));
#910=DIRECTION('',(1.,0.,0.));
#911=AXIS2_PLACEMENT_3D('',#908,#909,#910);
#912=PLANE('',#911);
#913=DIRECTION('',(-1.,0.,0.));
#914=VECTOR('',#913,1.);
#915=CARTESIAN_POINT('',(-82.55,0.,-57.15));
#916=LINE('',#915,#914);
#917=EDGE_CURVE('E900',#894,#839,#916,.T.);
#918=ORIENTED_EDGE('',*,*,#917,.T.);
#919=ORIENTED_EDGE('',*,*,#855,.F.);
#920=ORIENTED_EDGE('',*,*,#54,.F.);
#921=ORIENTED_EDGE('',*,*,#901,.T.);
#922=EDGE_LOOP('',(#918,#919,#920,#921));
#923=FACE_BOUND('',#922,.T.);
#924=ADVANCED_FACE('F1346',(#923),#912,.F.);
#925=CARTESIAN_POINT('',(-82.55,0.,57.15));
#926=DIRECTION('',(0.,1.,0.));
#927=DIRECTION('',(0.,0.,1.));
#928=AXIS2_PLACEMENT_3D('',#925,#926,#927);
#929=PLANE('',#928);
#930=ORIENTED_EDGE('',*,*,#842,.F.);
#931=ORIENTED_EDGE('',*,*,#917,.F.);
#932=ORIENTED_EDGE('',*,*,#895,.F.);
#933=ORIENTED_EDGE('',*,*,#871,.F.);
#934=EDGE_LOOP('',(#930,#931,#932,#933));
#935=FACE_BOUND('',#934,.T.);
#936=ADVANCED_FACE('F1344',(#935),#929,.F.);
#937=CARTESIAN_POINT('',(-44.45,6.35,-44.45));
#938=DIRECTION('',(1.,0.,0.));
#939=DIRECTION('',(0.,0.,-1.));
#940=AXIS2_PLACEMENT_3D('',#937,#938,#939);
#941=PLANE('',#940);
#942=DIRECTION('',(0.,0.,-1.));
#943=VECTOR('',#942,1.);
#944=CARTESIAN_POINT('',(-44.45,6.35,-44.45));
#945=LINE('',#944,#943);
#946=CARTESIAN_POINT('',(-44.45,6.35,-20.6375));
#947=VERTEX_POINT('',#946);
#948=CARTESIAN_POINT('',(-44.45,6.35,-42.8625));
#949=VERTEX_POINT('',#948);
#950=EDGE_CURVE('E881',#947,#949,#945,.T.);
#951=ORIENTED_EDGE('',*,*,#950,.F.);
#952=DIRECTION('',(0.,1.,0.));
#953=VECTOR('',#952,1.);
#954=CARTESIAN_POINT('',(-44.45,12.7,-20.6375));
#955=LINE('',#954,#953);
#956=EDGE_CURVE('E943',#947,#63,#955,.T.);
#957=ORIENTED_EDGE('',*,*,#956,.T.);
#958=ORIENTED_EDGE('',*,*,#66,.T.);
#959=DIRECTION('',(0.,1.,0.));
#960=VECTOR('',#959,1.);
#961=CARTESIAN_POINT('',(-44.45,6.35,-42.8625));
#962=LINE('',#961,#960);
#963=EDGE_CURVE('E941',#65,#949,#962,.F.);
#964=ORIENTED_EDGE('',*,*,#963,.T.);
#965=EDGE_LOOP('',(#951,#957,#958,#964));
#966=FACE_BOUND('',#965,.T.);
#967=ADVANCED_FACE('F1702',(#966),#941,.F.);
#968=CARTESIAN_POINT('',(-44.45,6.35,-19.05));
#969=DIRECTION('',(0.,0.,1.));
#970=DIRECTION('',(1.,0.,0.));
#971=AXIS2_PLACEMENT_3D('',#968,#969,#970);
#972=PLANE('',#971);
#973=DIRECTION('',(1.,0.,0.));
#974=VECTOR('',#973,1.);
#975=CARTESIAN_POINT('',(-44.45,6.35,-19.05));
#976=LINE('',#975,#974);
#977=CARTESIAN_POINT('',(-68.2625,6.35,-19.05));
#978=VERTEX_POINT('',#977);
#979=CARTESIAN_POINT('',(-46.0375,6.35,-19.05));
#980=VERTEX_POINT('',#979);
#981=EDGE_CURVE('E890',#978,#980,#976,.T.);
#982=ORIENTED_EDGE('',*,*,#981,.F.);
#983=DIRECTION('',(0.,1.,0.));
#984=VECTOR('',#983,1.);
#985=CARTESIAN_POINT('',(-68.2625,12.7,-19.05));
#986=LINE('',#985,#984);
#987=EDGE_CURVE('E925',#978,#82,#986,.T.);
#988=ORIENTED_EDGE('',*,*,#987,.T.);
#989=ORIENTED_EDGE('',*,*,#83,.T.);
#990=DIRECTION('',(0.,1.,0.));
#991=VECTOR('',#990,1.);
#992=CARTESIAN_POINT('',(-46.0375,6.35,-19.05));
#993=LINE('',#992,#991);
#994=EDGE_CURVE('E923',#74,#980,#993,.F.);
#995=ORIENTED_EDGE('',*,*,#994,.T.);
#996=EDGE_LOOP('',(#982,#988,#989,#995));
#997=FACE_BOUND('',#996,.T.);
#998=ADVANCED_FACE('F1698',(#997),#972,.F.);
#999=CARTESIAN_POINT('',(-69.85,6.35,-44.45));
#1000=DIRECTION('',(-1.,0.,0.));
#1001=DIRECTION('',(0.,0.,1.));
#1002=AXIS2_PLACEMENT_3D('',#999,#1000,#1001);
#1003=PLANE('',#1002);
#1004=ORIENTED_EDGE('',*,*,#100,.T.);
#1005=DIRECTION('',(0.,1.,0.));
#1006=VECTOR('',#1005,1.);
#1007=CARTESIAN_POINT('',(-69.85,6.35,-20.6375));
#1008=LINE('',#1007,#1006);
#1009=CARTESIAN_POINT('',(-69.85,6.35,-20.6375));
#1010=VERTEX_POINT('',#1009);
#1011=EDGE_CURVE('E931',#91,#1010,#1008,.F.);
#1012=ORIENTED_EDGE('',*,*,#1011,.T.);
#1013=DIRECTION('',(0.,0.,1.));
#1014=VECTOR('',#1013,1.);
#1015=CARTESIAN_POINT('',(-69.85,6.35,-44.45));
#1016=LINE('',#1015,#1014);
#1017=CARTESIAN_POINT('',(-69.85,6.35,-42.8625));
#1018=VERTEX_POINT('',#1017);
#1019=EDGE_CURVE('E887',#1018,#1010,#1016,.T.);
#1020=ORIENTED_EDGE('',*,*,#1019,.F.);
#1021=DIRECTION('',(0.,1.,0.));
#1022=VECTOR('',#1021,1.);
#1023=CARTESIAN_POINT('',(-69.85,12.7,-42.8625));
#1024=LINE('',#1023,#1022);
#1025=EDGE_CURVE('E928',#1018,#99,#1024,.T.);
#1026=ORIENTED_EDGE('',*,*,#1025,.T.);
#1027=EDGE_LOOP('',(#1004,#1012,#1020,#1026));
#1028=FACE_BOUND('',#1027,.T.);
#1029=ADVANCED_FACE('F1701',(#1028),#1003,.F.);
#1030=CARTESIAN_POINT('',(-44.45,6.35,-44.45));
#1031=DIRECTION('',(0.,0.,-1.));
#1032=DIRECTION('',(-1.,0.,0.));
#1033=AXIS2_PLACEMENT_3D('',#1030,#1031,#1032);
#1034=PLANE('',#1033);
#1035=DIRECTION('',(-1.,0.,0.));
#1036=VECTOR('',#1035,1.);
#1037=CARTESIAN_POINT('',(-44.45,6.35,-44.45));
#1038=LINE('',#1037,#1036);
#1039=CARTESIAN_POINT('',(-46.0375,6.35,-44.45));
#1040=VERTEX_POINT('',#1039);
#1041=CARTESIAN_POINT('',(-68.2625,6.35,-44.45));
#1042=VERTEX_POINT('',#1041);
#1043=EDGE_CURVE('E884',#1040,#1042,#1038,.T.);
#1044=ORIENTED_EDGE('',*,*,#1043,.F.);
#1045=DIRECTION('',(0.,1.,0.));
#1046=VECTOR('',#1045,1.);
#1047=CARTESIAN_POINT('',(-46.0375,12.7,-44.45));
#1048=LINE('',#1047,#1046);
#1049=EDGE_CURVE('E948',#1040,#116,#1048,.T.);
#1050=ORIENTED_EDGE('',*,*,#1049,.T.);
#1051=ORIENTED_EDGE('',*,*,#117,.T.);
#1052=DIRECTION('',(0.,1.,0.));
#1053=VECTOR('',#1052,1.);
#1054=CARTESIAN_POINT('',(-68.2625,6.35,-44.45));
#1055=LINE('',#1054,#1053);
#1056=EDGE_CURVE('E946',#108,#1042,#1055,.F.);
#1057=ORIENTED_EDGE('',*,*,#1056,.T.);
#1058=EDGE_LOOP('',(#1044,#1050,#1051,#1057));
#1059=FACE_BOUND('',#1058,.T.);
#1060=ADVANCED_FACE('F1696',(#1059),#1034,.F.);
#1061=CARTESIAN_POINT('',(-44.45,6.35,-19.05));
#1062=DIRECTION('',(0.,-1.,0.));
#1063=DIRECTION('',(0.,0.,-1.));
#1064=AXIS2_PLACEMENT_3D('',#1061,#1062,#1063);
#1065=PLANE('',#1064);
#1066=ORIENTED_EDGE('',*,*,#1019,.T.);
#1067=CARTESIAN_POINT('',(-68.2625,6.35,-20.6375));
#1068=DIRECTION('',(0.,-1.,0.));
#1069=DIRECTION('',(0.,0.,-1.));
#1070=AXIS2_PLACEMENT_3D('',#1067,#1068,#1069);
#1071=CIRCLE('',#1070,1.5875);
#1072=EDGE_CURVE('E939',#1010,#978,#1071,.F.);
#1073=ORIENTED_EDGE('',*,*,#1072,.T.);
#1074=ORIENTED_EDGE('',*,*,#981,.T.);
#1075=CARTESIAN_POINT('',(-46.0375,6.35,-20.6375));
#1076=DIRECTION('',(0.,-1.,0.));
#1077=DIRECTION('',(0.,0.,-1.));
#1078=AXIS2_PLACEMENT_3D('',#1075,#1076,#1077);
#1079=CIRCLE('',#1078,1.5875);
#1080=EDGE_CURVE('E937',#980,#947,#1079,.F.);
#1081=ORIENTED_EDGE('',*,*,#1080,.T.);
#1082=ORIENTED_EDGE('',*,*,#950,.T.);
#1083=CARTESIAN_POINT('',(-46.0375,6.35,-42.8625));
#1084=DIRECTION('',(0.,-1.,0.));
#1085=DIRECTION('',(0.,0.,-1.));
#1086=AXIS2_PLACEMENT_3D('',#1083,#1084,#1085);
#1087=CIRCLE('',#1086,1.5875);
#1088=EDGE_CURVE('E935',#949,#1040,#1087,.F.);
#1089=ORIENTED_EDGE('',*,*,#1088,.T.);
#1090=ORIENTED_EDGE('',*,*,#1043,.T.);
#1091=CARTESIAN_POINT('',(-68.2625,6.35,-42.8625));
#1092=DIRECTION('',(0.,-1.,0.));
#1093=DIRECTION('',(0.,0.,-1.));
#1094=AXIS2_PLACEMENT_3D('',#1091,#1092,#1093);
#1095=CIRCLE('',#1094,1.5875);
#1096=EDGE_CURVE('E933',#1042,#1018,#1095,.F.);
#1097=ORIENTED_EDGE('',*,*,#1096,.T.);
#1098=EDGE_LOOP('',(#1066,#1073,#1074,#1081,#1082,#1089,#1090,#1097));
#1099=FACE_BOUND('',#1098,.T.);
#1100=ADVANCED_FACE('F1692',(#1099),#1065,.F.);
#1101=CARTESIAN_POINT('',(-25.4,6.35,-12.7));
#1102=DIRECTION('',(1.,0.,0.));
#1103=DIRECTION('',(0.,0.,-1.));
#1104=AXIS2_PLACEMENT_3D('',#1101,#1102,#1103);
#1105=PLANE('',#1104);
#1106=ORIENTED_EDGE('',*,*,#136,.T.);
#1107=DIRECTION('',(0.,1.,0.));
#1108=VECTOR('',#1107,1.);
#1109=CARTESIAN_POINT('',(-25.4,6.35,-11.1125));
#1110=LINE('',#1109,#1108);
#1111=CARTESIAN_POINT('',(-25.4,6.35,-11.1125));
#1112=VERTEX_POINT('',#1111);
#1113=EDGE_CURVE('E1219',#135,#1112,#1110,.F.);
#1114=ORIENTED_EDGE('',*,*,#1113,.T.);
#1115=DIRECTION('',(0.,0.,-1.));
#1116=VECTOR('',#1115,1.);
#1117=CARTESIAN_POINT('',(-25.4,6.35,-12.7));
#1118=LINE('',#1117,#1116);
#1119=CARTESIAN_POINT('',(-25.4,6.35,11.1125));
#1120=VERTEX_POINT('',#1119);
#1121=EDGE_CURVE('E857',#1120,#1112,#1118,.T.);
#1122=ORIENTED_EDGE('',*,*,#1121,.F.);
#1123=DIRECTION('',(0.,1.,0.));
#1124=VECTOR('',#1123,1.);
#1125=CARTESIAN_POINT('',(-25.4,12.7,11.1125));
#1126=LINE('',#1125,#1124);
#1127=EDGE_CURVE('E1216',#1120,#133,#1126,.T.);
#1128=ORIENTED_EDGE('',*,*,#1127,.T.);
#1129=EDGE_LOOP('',(#1106,#1114,#1122,#1128));
#1130=FACE_BOUND('',#1129,.T.);
#1131=ADVANCED_FACE('F1682',(#1130),#1105,.F.);
#1132=CARTESIAN_POINT('',(-25.4,6.35,12.7));
#1133=DIRECTION('',(0.,0.,1.));
#1134=DIRECTION('',(1.,0.,0.));
#1135=AXIS2_PLACEMENT_3D('',#1132,#1133,#1134);
#1136=PLANE('',#1135);
#1137=ORIENTED_EDGE('',*,*,#153,.T.);
#1138=DIRECTION('',(0.,1.,0.));
#1139=VECTOR('',#1138,1.);
#1140=CARTESIAN_POINT('',(-26.9875,6.35,12.7));
#1141=LINE('',#1140,#1139);
#1142=CARTESIAN_POINT('',(-26.9875,6.35,12.7));
#1143=VERTEX_POINT('',#1142);
#1144=EDGE_CURVE('E1232',#144,#1143,#1141,.F.);
#1145=ORIENTED_EDGE('',*,*,#1144,.T.);
#1146=DIRECTION('',(1.,0.,0.));
#1147=VECTOR('',#1146,1.);
#1148=CARTESIAN_POINT('',(-25.4,6.35,12.7));
#1149=LINE('',#1148,#1147);
#1150=CARTESIAN_POINT('',(-49.2125,6.35,12.7));
#1151=VERTEX_POINT('',#1150);
#1152=EDGE_CURVE('E866',#1151,#1143,#1149,.T.);
#1153=ORIENTED_EDGE('',*,*,#1152,.F.);
#1154=DIRECTION('',(0.,1.,0.));
#1155=VECTOR('',#1154,1.);
#1156=CARTESIAN_POINT('',(-49.2125,12.7,12.7));
#1157=LINE('',#1156,#1155);
#1158=EDGE_CURVE('E1229',#1151,#152,#1157,.T.);
#1159=ORIENTED_EDGE('',*,*,#1158,.T.);
#1160=EDGE_LOOP('',(#1137,#1145,#1153,#1159));
#1161=FACE_BOUND('',#1160,.T.);
#1162=ADVANCED_FACE('F1678',(#1161),#1136,.F.);
#1163=CARTESIAN_POINT('',(-50.8,6.35,-12.7));
#1164=DIRECTION('',(-1.,0.,0.));
#1165=DIRECTION('',(0.,0.,1.));
#1166=AXIS2_PLACEMENT_3D('',#1163,#1164,#1165);
#1167=PLANE('',#1166);
#1168=ORIENTED_EDGE('',*,*,#170,.T.);
#1169=DIRECTION('',(0.,1.,0.));
#1170=VECTOR('',#1169,1.);
#1171=CARTESIAN_POINT('',(-50.8,6.35,11.1125));
#1172=LINE('',#1171,#1170);
#1173=CARTESIAN_POINT('',(-50.8,6.35,11.1125));
#1174=VERTEX_POINT('',#1173);
#1175=EDGE_CURVE('E1237',#161,#1174,#1172,.F.);
#1176=ORIENTED_EDGE('',*,*,#1175,.T.);
#1177=DIRECTION('',(0.,0.,1.));
#1178=VECTOR('',#1177,1.);
#1179=CARTESIAN_POINT('',(-50.8,6.35,-12.7));
#1180=LINE('',#1179,#1178);
#1181=CARTESIAN_POINT('',(-50.8,6.35,-11.1125));
#1182=VERTEX_POINT('',#1181);
#1183=EDGE_CURVE('E863',#1182,#1174,#1180,.T.);
#1184=ORIENTED_EDGE('',*,*,#1183,.F.);
#1185=DIRECTION('',(0.,1.,0.));
#1186=VECTOR('',#1185,1.);
#1187=CARTESIAN_POINT('',(-50.8,12.7,-11.1125));
#1188=LINE('',#1187,#1186);
#1189=EDGE_CURVE('E1234',#1182,#169,#1188,.T.);
#1190=ORIENTED_EDGE('',*,*,#1189,.T.);
#1191=EDGE_LOOP('',(#1168,#1176,#1184,#1190));
#1192=FACE_BOUND('',#1191,.T.);
#1193=ADVANCED_FACE('F1681',(#1192),#1167,.F.);
#1194=CARTESIAN_POINT('',(-25.4,6.35,-12.7));
#1195=DIRECTION('',(0.,0.,-1.));
#1196=DIRECTION('',(-1.,0.,0.));
#1197=AXIS2_PLACEMENT_3D('',#1194,#1195,#1196);
#1198=PLANE('',#1197);
#1199=DIRECTION('',(-1.,0.,0.));
#1200=VECTOR('',#1199,1.);
#1201=CARTESIAN_POINT('',(-25.4,6.35,-12.7));
#1202=LINE('',#1201,#1200);
#1203=CARTESIAN_POINT('',(-26.9875,6.35,-12.7));
#1204=VERTEX_POINT('',#1203);
#1205=CARTESIAN_POINT('',(-49.2125,6.35,-12.7));
#1206=VERTEX_POINT('',#1205);
#1207=EDGE_CURVE('E860',#1204,#1206,#1202,.T.);
#1208=ORIENTED_EDGE('',*,*,#1207,.F.);
#1209=DIRECTION('',(0.,1.,0.));
#1210=VECTOR('',#1209,1.);
#1211=CARTESIAN_POINT('',(-26.9875,12.7,-12.7));
#1212=LINE('',#1211,#1210);
#1213=EDGE_CURVE('E1213',#1204,#186,#1212,.T.);
#1214=ORIENTED_EDGE('',*,*,#1213,.T.);
#1215=ORIENTED_EDGE('',*,*,#187,.T.);
#1216=DIRECTION('',(0.,1.,0.));
#1217=VECTOR('',#1216,1.);
#1218=CARTESIAN_POINT('',(-49.2125,6.35,-12.7));
#1219=LINE('',#1218,#1217);
#1220=EDGE_CURVE('E1211',#178,#1206,#1219,.F.);
#1221=ORIENTED_EDGE('',*,*,#1220,.T.);
#1222=EDGE_LOOP('',(#1208,#1214,#1215,#1221));
#1223=FACE_BOUND('',#1222,.T.);
#1224=ADVANCED_FACE('F1676',(#1223),#1198,.F.);
#1225=CARTESIAN_POINT('',(-25.4,6.35,12.7));
#1226=DIRECTION('',(0.,-1.,0.));
#1227=DIRECTION('',(0.,0.,-1.));
#1228=AXIS2_PLACEMENT_3D('',#1225,#1226,#1227);
#1229=PLANE('',#1228);
#1230=ORIENTED_EDGE('',*,*,#1121,.T.);
#1231=CARTESIAN_POINT('',(-26.9875,6.35,-11.1125));
#1232=DIRECTION('',(0.,-1.,0.));
#1233=DIRECTION('',(0.,0.,-1.));
#1234=AXIS2_PLACEMENT_3D('',#1231,#1232,#1233);
#1235=CIRCLE('',#1234,1.5875);
#1236=EDGE_CURVE('E1227',#1112,#1204,#1235,.F.);
#1237=ORIENTED_EDGE('',*,*,#1236,.T.);
#1238=ORIENTED_EDGE('',*,*,#1207,.T.);
#1239=CARTESIAN_POINT('',(-49.2125,6.35,-11.1125));
#1240=DIRECTION('',(0.,-1.,0.));
#1241=DIRECTION('',(0.,0.,-1.));
#1242=AXIS2_PLACEMENT_3D('',#1239,#1240,#1241);
#1243=CIRCLE('',#1242,1.5875);
#1244=EDGE_CURVE('E1221',#1206,#1182,#1243,.F.);
#1245=ORIENTED_EDGE('',*,*,#1244,.T.);
#1246=ORIENTED_EDGE('',*,*,#1183,.T.);
#1247=CARTESIAN_POINT('',(-49.2125,6.35,11.1125));
#1248=DIRECTION('',(0.,-1.,0.));
#1249=DIRECTION('',(0.,0.,-1.));
#1250=AXIS2_PLACEMENT_3D('',#1247,#1248,#1249);
#1251=CIRCLE('',#1250,1.5875);
#1252=EDGE_CURVE('E1223',#1174,#1151,#1251,.F.);
#1253=ORIENTED_EDGE('',*,*,#1252,.T.);
#1254=ORIENTED_EDGE('',*,*,#1152,.T.);
#1255=CARTESIAN_POINT('',(-26.9875,6.35,11.1125));
#1256=DIRECTION('',(0.,-1.,0.));
#1257=DIRECTION('',(0.,0.,-1.));
#1258=AXIS2_PLACEMENT_3D('',#1255,#1256,#1257);
#1259=CIRCLE('',#1258,1.5875);
#1260=EDGE_CURVE('E1225',#1143,#1120,#1259,.F.);
#1261=ORIENTED_EDGE('',*,*,#1260,.T.);
#1262=EDGE_LOOP('',(#1230,#1237,#1238,#1245,#1246,#1253,#1254,#1261));
#1263=FACE_BOUND('',#1262,.T.);
#1264=ADVANCED_FACE('F1672',(#1263),#1229,.F.);
#1265=CARTESIAN_POINT('',(-68.2625,6.35,-20.6375));
#1266=DIRECTION('',(0.,-1.,0.));
#1267=DIRECTION('',(0.,0.,-1.));
#1268=AXIS2_PLACEMENT_3D('',#1265,#1266,#1267);
#1269=CYLINDRICAL_SURFACE('',#1268,1.5875);
#1270=ORIENTED_EDGE('',*,*,#1072,.F.);
#1271=ORIENTED_EDGE('',*,*,#1011,.F.);
#1272=ORIENTED_EDGE('',*,*,#92,.F.);
#1273=ORIENTED_EDGE('',*,*,#987,.F.);
#1274=EDGE_LOOP('',(#1270,#1271,#1272,#1273));
#1275=FACE_BOUND('',#1274,.T.);
#1276=ADVANCED_FACE('F1668',(#1275),#1269,.F.);
#1277=CARTESIAN_POINT('',(-46.0375,6.35,-20.6375));
#1278=DIRECTION('',(0.,-1.,0.));
#1279=DIRECTION('',(0.,0.,-1.));
#1280=AXIS2_PLACEMENT_3D('',#1277,#1278,#1279);
#1281=CYLINDRICAL_SURFACE('',#1280,1.5875);
#1282=ORIENTED_EDGE('',*,*,#1080,.F.);
#1283=ORIENTED_EDGE('',*,*,#994,.F.);
#1284=ORIENTED_EDGE('',*,*,#75,.F.);
#1285=ORIENTED_EDGE('',*,*,#956,.F.);
#1286=EDGE_LOOP('',(#1282,#1283,#1284,#1285));
#1287=FACE_BOUND('',#1286,.T.);
#1288=ADVANCED_FACE('F1664',(#1287),#1281,.F.);
#1289=CARTESIAN_POINT('',(-46.0375,6.35,-42.8625));
#1290=DIRECTION('',(0.,-1.,0.));
#1291=DIRECTION('',(0.,0.,-1.));
#1292=AXIS2_PLACEMENT_3D('',#1289,#1290,#1291);
#1293=CYLINDRICAL_SURFACE('',#1292,1.5875);
#1294=ORIENTED_EDGE('',*,*,#1088,.F.);
#1295=ORIENTED_EDGE('',*,*,#963,.F.);
#1296=ORIENTED_EDGE('',*,*,#124,.F.);
#1297=ORIENTED_EDGE('',*,*,#1049,.F.);
#1298=EDGE_LOOP('',(#1294,#1295,#1296,#1297));
#1299=FACE_BOUND('',#1298,.T.);
#1300=ADVANCED_FACE('F1660',(#1299),#1293,.F.);
#1301=CARTESIAN_POINT('',(-68.2625,6.35,-42.8625));
#1302=DIRECTION('',(0.,-1.,0.));
#1303=DIRECTION('',(0.,0.,-1.));
#1304=AXIS2_PLACEMENT_3D('',#1301,#1302,#1303);
#1305=CYLINDRICAL_SURFACE('',#1304,1.5875);
#1306=ORIENTED_EDGE('',*,*,#1096,.F.);
#1307=ORIENTED_EDGE('',*,*,#1056,.F.);
#1308=ORIENTED_EDGE('',*,*,#109,.F.);
#1309=ORIENTED_EDGE('',*,*,#1025,.F.);
#1310=EDGE_LOOP('',(#1306,#1307,#1308,#1309));
#1311=FACE_BOUND('',#1310,.T.);
#1312=ADVANCED_FACE('F1656',(#1311),#1305,.F.);
#1313=CARTESIAN_POINT('',(-44.45,6.35,19.05));
#1314=DIRECTION('',(1.,0.,0.));
#1315=DIRECTION('',(0.,0.,-1.));
#1316=AXIS2_PLACEMENT_3D('',#1313,#1314,#1315);
#1317=PLANE('',#1316);
#1318=DIRECTION('',(0.,0.,-1.));
#1319=VECTOR('',#1318,1.);
#1320=CARTESIAN_POINT('',(-44.45,6.35,19.05));
#1321=LINE('',#1320,#1319);
#1322=CARTESIAN_POINT('',(-44.45,6.35,42.8625));
#1323=VERTEX_POINT('',#1322);
#1324=CARTESIAN_POINT('',(-44.45,6.35,20.6375));
#1325=VERTEX_POINT('',#1324);
#1326=EDGE_CURVE('E833',#1323,#1325,#1321,.T.);
#1327=ORIENTED_EDGE('',*,*,#1326,.F.);
#1328=DIRECTION('',(0.,1.,0.));
#1329=VECTOR('',#1328,1.);
#1330=CARTESIAN_POINT('',(-44.45,12.7,42.8625));
#1331=LINE('',#1330,#1329);
#1332=EDGE_CURVE('E979',#1323,#203,#1331,.T.);
#1333=ORIENTED_EDGE('',*,*,#1332,.T.);
#1334=ORIENTED_EDGE('',*,*,#206,.T.);
#1335=DIRECTION('',(0.,1.,0.));
#1336=VECTOR('',#1335,1.);
#1337=CARTESIAN_POINT('',(-44.45,6.35,20.6375));
#1338=LINE('',#1337,#1336);
#1339=EDGE_CURVE('E977',#205,#1325,#1338,.F.);
#1340=ORIENTED_EDGE('',*,*,#1339,.T.);
#1341=EDGE_LOOP('',(#1327,#1333,#1334,#1340));
#1342=FACE_BOUND('',#1341,.T.);
#1343=ADVANCED_FACE('F1646',(#1342),#1317,.F.);
#1344=CARTESIAN_POINT('',(-44.45,6.35,44.45));
#1345=DIRECTION('',(0.,0.,1.));
#1346=DIRECTION('',(1.,0.,0.));
#1347=AXIS2_PLACEMENT_3D('',#1344,#1345,#1346);
#1348=PLANE('',#1347);
#1349=DIRECTION('',(1.,0.,0.));
#1350=VECTOR('',#1349,1.);
#1351=CARTESIAN_POINT('',(-44.45,6.35,44.45));
#1352=LINE('',#1351,#1350);
#1353=CARTESIAN_POINT('',(-68.2625,6.35,44.45));
#1354=VERTEX_POINT('',#1353);
#1355=CARTESIAN_POINT('',(-46.0375,6.35,44.45));
#1356=VERTEX_POINT('',#1355);
#1357=EDGE_CURVE('E842',#1354,#1356,#1352,.T.);
#1358=ORIENTED_EDGE('',*,*,#1357,.F.);
#1359=DIRECTION('',(0.,1.,0.));
#1360=VECTOR('',#1359,1.);
#1361=CARTESIAN_POINT('',(-68.2625,12.7,44.45));
#1362=LINE('',#1361,#1360);
#1363=EDGE_CURVE('E961',#1354,#222,#1362,.T.);
#1364=ORIENTED_EDGE('',*,*,#1363,.T.);
#1365=ORIENTED_EDGE('',*,*,#223,.T.);
#1366=DIRECTION('',(0.,1.,0.));
#1367=VECTOR('',#1366,1.);
#1368=CARTESIAN_POINT('',(-46.0375,6.35,44.45));
#1369=LINE('',#1368,#1367);
#1370=EDGE_CURVE('E959',#214,#1356,#1369,.F.);
#1371=ORIENTED_EDGE('',*,*,#1370,.T.);
#1372=EDGE_LOOP('',(#1358,#1364,#1365,#1371));
#1373=FACE_BOUND('',#1372,.T.);
#1374=ADVANCED_FACE('F1642',(#1373),#1348,.F.);
#1375=CARTESIAN_POINT('',(-69.85,6.35,19.05));
#1376=DIRECTION('',(-1.,0.,0.));
#1377=DIRECTION('',(0.,0.,1.));
#1378=AXIS2_PLACEMENT_3D('',#1375,#1376,#1377);
#1379=PLANE('',#1378);
#1380=ORIENTED_EDGE('',*,*,#240,.T.);
#1381=DIRECTION('',(0.,1.,0.));
#1382=VECTOR('',#1381,1.);
#1383=CARTESIAN_POINT('',(-69.85,6.35,42.8625));
#1384=LINE('',#1383,#1382);
#1385=CARTESIAN_POINT('',(-69.85,6.35,42.8625));
#1386=VERTEX_POINT('',#1385);
#1387=EDGE_CURVE('E967',#231,#1386,#1384,.F.);
#1388=ORIENTED_EDGE('',*,*,#1387,.T.);
#1389=DIRECTION('',(0.,0.,1.));
#1390=VECTOR('',#1389,1.);
#1391=CARTESIAN_POINT('',(-69.85,6.35,19.05));
#1392=LINE('',#1391,#1390);
#1393=CARTESIAN_POINT('',(-69.85,6.35,20.6375));
#1394=VERTEX_POINT('',#1393);
#1395=EDGE_CURVE('E839',#1394,#1386,#1392,.T.);
#1396=ORIENTED_EDGE('',*,*,#1395,.F.);
#1397=DIRECTION('',(0.,1.,0.));
#1398=VECTOR('',#1397,1.);
#1399=CARTESIAN_POINT('',(-69.85,12.7,20.6375));
#1400=LINE('',#1399,#1398);
#1401=EDGE_CURVE('E964',#1394,#239,#1400,.T.);
#1402=ORIENTED_EDGE('',*,*,#1401,.T.);
#1403=EDGE_LOOP('',(#1380,#1388,#1396,#1402));
#1404=FACE_BOUND('',#1403,.T.);
#1405=ADVANCED_FACE('F1645',(#1404),#1379,.F.);
#1406=CARTESIAN_POINT('',(-44.45,6.35,19.05));
#1407=DIRECTION('',(0.,0.,-1.));
#1408=DIRECTION('',(-1.,0.,0.));
#1409=AXIS2_PLACEMENT_3D('',#1406,#1407,#1408);
#1410=PLANE('',#1409);
#1411=DIRECTION('',(-1.,0.,0.));
#1412=VECTOR('',#1411,1.);
#1413=CARTESIAN_POINT('',(-44.45,6.35,19.05));
#1414=LINE('',#1413,#1412);
#1415=CARTESIAN_POINT('',(-46.0375,6.35,19.05));
#1416=VERTEX_POINT('',#1415);
#1417=CARTESIAN_POINT('',(-68.2625,6.35,19.05));
#1418=VERTEX_POINT('',#1417);
#1419=EDGE_CURVE('E836',#1416,#1418,#1414,.T.);
#1420=ORIENTED_EDGE('',*,*,#1419,.F.);
#1421=DIRECTION('',(0.,1.,0.));
#1422=VECTOR('',#1421,1.);
#1423=CARTESIAN_POINT('',(-46.0375,12.7,19.05));
#1424=LINE('',#1423,#1422);
#1425=EDGE_CURVE('E984',#1416,#256,#1424,.T.);
#1426=ORIENTED_EDGE('',*,*,#1425,.T.);
#1427=ORIENTED_EDGE('',*,*,#257,.T.);
#1428=DIRECTION('',(0.,1.,0.));
#1429=VECTOR('',#1428,1.);
#1430=CARTESIAN_POINT('',(-68.2625,6.35,19.05));
#1431=LINE('',#1430,#1429);
#1432=EDGE_CURVE('E982',#248,#1418,#1431,.F.);
#1433=ORIENTED_EDGE('',*,*,#1432,.T.);
#1434=EDGE_LOOP('',(#1420,#1426,#1427,#1433));
#1435=FACE_BOUND('',#1434,.T.);
#1436=ADVANCED_FACE('F1640',(#1435),#1410,.F.);
#1437=CARTESIAN_POINT('',(-44.45,6.35,44.45));
#1438=DIRECTION('',(0.,-1.,0.));
#1439=DIRECTION('',(0.,0.,-1.));
#1440=AXIS2_PLACEMENT_3D('',#1437,#1438,#1439);
#1441=PLANE('',#1440);
#1442=ORIENTED_EDGE('',*,*,#1395,.T.);
#1443=CARTESIAN_POINT('',(-68.2625,6.35,42.8625));
#1444=DIRECTION('',(0.,-1.,0.));
#1445=DIRECTION('',(0.,0.,-1.));
#1446=AXIS2_PLACEMENT_3D('',#1443,#1444,#1445);
#1447=CIRCLE('',#1446,1.5875);
#1448=EDGE_CURVE('E975',#1386,#1354,#1447,.F.);
#1449=ORIENTED_EDGE('',*,*,#1448,.T.);
#1450=ORIENTED_EDGE('',*,*,#1357,.T.);
#1451=CARTESIAN_POINT('',(-46.0375,6.35,42.8625));
#1452=DIRECTION('',(0.,-1.,0.));
#1453=DIRECTION('',(0.,0.,-1.));
#1454=AXIS2_PLACEMENT_3D('',#1451,#1452,#1453);
#1455=CIRCLE('',#1454,1.5875);
#1456=EDGE_CURVE('E973',#1356,#1323,#1455,.F.);
#1457=ORIENTED_EDGE('',*,*,#1456,.T.);
#1458=ORIENTED_EDGE('',*,*,#1326,.T.);
#1459=CARTESIAN_POINT('',(-46.0375,6.35,20.6375));
#1460=DIRECTION('',(0.,-1.,0.));
#1461=DIRECTION('',(0.,0.,-1.));
#1462=AXIS2_PLACEMENT_3D('',#1459,#1460,#1461);
#1463=CIRCLE('',#1462,1.5875);
#1464=EDGE_CURVE('E971',#1325,#1416,#1463,.F.);
#1465=ORIENTED_EDGE('',*,*,#1464,.T.);
#1466=ORIENTED_EDGE('',*,*,#1419,.T.);
#1467=CARTESIAN_POINT('',(-68.2625,6.35,20.6375));
#1468=DIRECTION('',(0.,-1.,0.));
#1469=DIRECTION('',(0.,0.,-1.));
#1470=AXIS2_PLACEMENT_3D('',#1467,#1468,#1469);
#1471=CIRCLE('',#1470,1.5875);
#1472=EDGE_CURVE('E969',#1418,#1394,#1471,.F.);
#1473=ORIENTED_EDGE('',*,*,#1472,.T.);
#1474=EDGE_LOOP('',(#1442,#1449,#1450,#1457,#1458,#1465,#1466,#1473));
#1475=FACE_BOUND('',#1474,.T.);
#1476=ADVANCED_FACE('F1636',(#1475),#1441,.F.);
#1477=CARTESIAN_POINT('',(-6.34999999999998,6.35,-44.45));
#1478=DIRECTION('',(1.,0.,0.));
#1479=DIRECTION('',(0.,0.,-1.));
#1480=AXIS2_PLACEMENT_3D('',#1477,#1478,#1479);
#1481=PLANE('',#1480);
#1482=DIRECTION('',(0.,0.,-1.));
#1483=VECTOR('',#1482,1.);
#1484=CARTESIAN_POINT('',(-6.34999999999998,6.35,-44.45));
#1485=LINE('',#1484,#1483);
#1486=CARTESIAN_POINT('',(-6.34999999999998,6.35,-20.6375));
#1487=VERTEX_POINT('',#1486);
#1488=CARTESIAN_POINT('',(-6.34999999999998,6.35,-42.8625));
#1489=VERTEX_POINT('',#1488);
#1490=EDGE_CURVE('E809',#1487,#1489,#1485,.T.);
#1491=ORIENTED_EDGE('',*,*,#1490,.F.);
#1492=DIRECTION('',(0.,1.,0.));
#1493=VECTOR('',#1492,1.);
#1494=CARTESIAN_POINT('',(-6.34999999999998,12.7,-20.6375));
#1495=LINE('',#1494,#1493);
#1496=EDGE_CURVE('E1015',#1487,#273,#1495,.T.);
#1497=ORIENTED_EDGE('',*,*,#1496,.T.);
#1498=ORIENTED_EDGE('',*,*,#276,.T.);
#1499=DIRECTION('',(0.,1.,0.));
#1500=VECTOR('',#1499,1.);
#1501=CARTESIAN_POINT('',(-6.34999999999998,6.35,-42.8625));
#1502=LINE('',#1501,#1500);
#1503=EDGE_CURVE('E1013',#275,#1489,#1502,.F.);
#1504=ORIENTED_EDGE('',*,*,#1503,.T.);
#1505=EDGE_LOOP('',(#1491,#1497,#1498,#1504));
#1506=FACE_BOUND('',#1505,.T.);
#1507=ADVANCED_FACE('F1626',(#1506),#1481,.F.);
#1508=CARTESIAN_POINT('',(-6.34999999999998,6.35,-19.05));
#1509=DIRECTION('',(0.,0.,1.));
#1510=DIRECTION('',(1.,0.,0.));
#1511=AXIS2_PLACEMENT_3D('',#1508,#1509,#1510);
#1512=PLANE('',#1511);
#1513=DIRECTION('',(1.,0.,0.));
#1514=VECTOR('',#1513,1.);
#1515=CARTESIAN_POINT('',(-6.34999999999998,6.35,-19.05));
#1516=LINE('',#1515,#1514);
#1517=CARTESIAN_POINT('',(-30.1625,6.35,-19.05));
#1518=VERTEX_POINT('',#1517);
#1519=CARTESIAN_POINT('',(-7.93749999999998,6.35,-19.05));
#1520=VERTEX_POINT('',#1519);
#1521=EDGE_CURVE('E818',#1518,#1520,#1516,.T.);
#1522=ORIENTED_EDGE('',*,*,#1521,.F.);
#1523=DIRECTION('',(0.,1.,0.));
#1524=VECTOR('',#1523,1.);
#1525=CARTESIAN_POINT('',(-30.1625,12.7,-19.05));
#1526=LINE('',#1525,#1524);
#1527=EDGE_CURVE('E997',#1518,#292,#1526,.T.);
#1528=ORIENTED_EDGE('',*,*,#1527,.T.);
#1529=ORIENTED_EDGE('',*,*,#293,.T.);
#1530=DIRECTION('',(0.,1.,0.));
#1531=VECTOR('',#1530,1.);
#1532=CARTESIAN_POINT('',(-7.93749999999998,6.35,-19.05));
#1533=LINE('',#1532,#1531);
#1534=EDGE_CURVE('E995',#284,#1520,#1533,.F.);
#1535=ORIENTED_EDGE('',*,*,#1534,.T.);
#1536=EDGE_LOOP('',(#1522,#1528,#1529,#1535));
#1537=FACE_BOUND('',#1536,.T.);
#1538=ADVANCED_FACE('F1622',(#1537),#1512,.F.);
#1539=CARTESIAN_POINT('',(-31.75,6.35,-44.45));
#1540=DIRECTION('',(-1.,0.,0.));
#1541=DIRECTION('',(0.,0.,1.));
#1542=AXIS2_PLACEMENT_3D('',#1539,#1540,#1541);
#1543=PLANE('',#1542);
#1544=ORIENTED_EDGE('',*,*,#310,.T.);
#1545=DIRECTION('',(0.,1.,0.));
#1546=VECTOR('',#1545,1.);
#1547=CARTESIAN_POINT('',(-31.75,6.35,-20.6375));
#1548=LINE('',#1547,#1546);
#1549=CARTESIAN_POINT('',(-31.75,6.35,-20.6375));
#1550=VERTEX_POINT('',#1549);
#1551=EDGE_CURVE('E1003',#301,#1550,#1548,.F.);
#1552=ORIENTED_EDGE('',*,*,#1551,.T.);
#1553=DIRECTION('',(0.,0.,1.));
#1554=VECTOR('',#1553,1.);
#1555=CARTESIAN_POINT('',(-31.75,6.35,-44.45));
#1556=LINE('',#1555,#1554);
#1557=CARTESIAN_POINT('',(-31.75,6.35,-42.8625));
#1558=VERTEX_POINT('',#1557);
#1559=EDGE_CURVE('E815',#1558,#1550,#1556,.T.);
#1560=ORIENTED_EDGE('',*,*,#1559,.F.);
#1561=DIRECTION('',(0.,1.,0.));
#1562=VECTOR('',#1561,1.);
#1563=CARTESIAN_POINT('',(-31.75,12.7,-42.8625));
#1564=LINE('',#1563,#1562);
#1565=EDGE_CURVE('E1000',#1558,#309,#1564,.T.);
#1566=ORIENTED_EDGE('',*,*,#1565,.T.);
#1567=EDGE_LOOP('',(#1544,#1552,#1560,#1566));
#1568=FACE_BOUND('',#1567,.T.);
#1569=ADVANCED_FACE('F1625',(#1568),#1543,.F.);
#1570=CARTESIAN_POINT('',(-6.34999999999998,6.35,-44.45));
#1571=DIRECTION('',(0.,0.,-1.));
#1572=DIRECTION('',(-1.,0.,0.));
#1573=AXIS2_PLACEMENT_3D('',#1570,#1571,#1572);
#1574=PLANE('',#1573);
#1575=DIRECTION('',(-1.,0.,0.));
#1576=VECTOR('',#1575,1.);
#1577=CARTESIAN_POINT('',(-6.34999999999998,6.35,-44.45));
#1578=LINE('',#1577,#1576);
#1579=CARTESIAN_POINT('',(-7.93749999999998,6.35,-44.45));
#1580=VERTEX_POINT('',#1579);
#1581=CARTESIAN_POINT('',(-30.1625,6.35,-44.45));
#1582=VERTEX_POINT('',#1581);
#1583=EDGE_CURVE('E812',#1580,#1582,#1578,.T.);
#1584=ORIENTED_EDGE('',*,*,#1583,.F.);
#1585=DIRECTION('',(0.,1.,0.));
#1586=VECTOR('',#1585,1.);
#1587=CARTESIAN_POINT('',(-7.93749999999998,12.7,-44.45));
#1588=LINE('',#1587,#1586);
#1589=EDGE_CURVE('E1020',#1580,#326,#1588,.T.);
#1590=ORIENTED_EDGE('',*,*,#1589,.T.);
#1591=ORIENTED_EDGE('',*,*,#327,.T.);
#1592=DIRECTION('',(0.,1.,0.));
#1593=VECTOR('',#1592,1.);
#1594=CARTESIAN_POINT('',(-30.1625,6.35,-44.45));
#1595=LINE('',#1594,#1593);
#1596=EDGE_CURVE('E1018',#318,#1582,#1595,.F.);
#1597=ORIENTED_EDGE('',*,*,#1596,.T.);
#1598=EDGE_LOOP('',(#1584,#1590,#1591,#1597));
#1599=FACE_BOUND('',#1598,.T.);
#1600=ADVANCED_FACE('F1620',(#1599),#1574,.F.);
#1601=CARTESIAN_POINT('',(-6.34999999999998,6.35,-19.05));
#1602=DIRECTION('',(0.,-1.,0.));
#1603=DIRECTION('',(0.,0.,-1.));
#1604=AXIS2_PLACEMENT_3D('',#1601,#1602,#1603);
#1605=PLANE('',#1604);
#1606=ORIENTED_EDGE('',*,*,#1559,.T.);
#1607=CARTESIAN_POINT('',(-30.1625,6.35,-20.6375));
#1608=DIRECTION('',(0.,-1.,0.));
#1609=DIRECTION('',(0.,0.,-1.));
#1610=AXIS2_PLACEMENT_3D('',#1607,#1608,#1609);
#1611=CIRCLE('',#1610,1.5875);
#1612=EDGE_CURVE('E1011',#1550,#1518,#1611,.F.);
#1613=ORIENTED_EDGE('',*,*,#1612,.T.);
#1614=ORIENTED_EDGE('',*,*,#1521,.T.);
#1615=CARTESIAN_POINT('',(-7.93749999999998,6.35,-20.6375));
#1616=DIRECTION('',(0.,-1.,0.));
#1617=DIRECTION('',(0.,0.,-1.));
#1618=AXIS2_PLACEMENT_3D('',#1615,#1616,#1617);
#1619=CIRCLE('',#1618,1.5875);
#1620=EDGE_CURVE('E1009',#1520,#1487,#1619,.F.);
#1621=ORIENTED_EDGE('',*,*,#1620,.T.);
#1622=ORIENTED_EDGE('',*,*,#1490,.T.);
#1623=CARTESIAN_POINT('',(-7.93749999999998,6.35,-42.8625));
#1624=DIRECTION('',(0.,-1.,0.));
#1625=DIRECTION('',(0.,0.,-1.));
#1626=AXIS2_PLACEMENT_3D('',#1623,#1624,#1625);
#1627=CIRCLE('',#1626,1.5875);
#1628=EDGE_CURVE('E1007',#1489,#1580,#1627,.F.);
#1629=ORIENTED_EDGE('',*,*,#1628,.T.);
#1630=ORIENTED_EDGE('',*,*,#1583,.T.);
#1631=CARTESIAN_POINT('',(-30.1625,6.35,-42.8625));
#1632=DIRECTION('',(0.,-1.,0.));
#1633=DIRECTION('',(0.,0.,-1.));
#1634=AXIS2_PLACEMENT_3D('',#1631,#1632,#1633);
#1635=CIRCLE('',#1634,1.5875);
#1636=EDGE_CURVE('E1005',#1582,#1558,#1635,.F.);
#1637=ORIENTED_EDGE('',*,*,#1636,.T.);
#1638=EDGE_LOOP('',(#1606,#1613,#1614,#1621,#1622,#1629,#1630,#1637));
#1639=FACE_BOUND('',#1638,.T.);
#1640=ADVANCED_FACE('F1616',(#1639),#1605,.F.);
#1641=CARTESIAN_POINT('',(-6.34999999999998,6.35,19.05));
#1642=DIRECTION('',(1.,0.,0.));
#1643=DIRECTION('',(0.,0.,-1.));
#1644=AXIS2_PLACEMENT_3D('',#1641,#1642,#1643);
#1645=PLANE('',#1644);
#1646=DIRECTION('',(0.,0.,-1.));
#1647=VECTOR('',#1646,1.);
#1648=CARTESIAN_POINT('',(-6.34999999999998,6.35,19.05));
#1649=LINE('',#1648,#1647);
#1650=CARTESIAN_POINT('',(-6.34999999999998,6.35,42.8625));
#1651=VERTEX_POINT('',#1650);
#1652=CARTESIAN_POINT('',(-6.34999999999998,6.35,20.6375));
#1653=VERTEX_POINT('',#1652);
#1654=EDGE_CURVE('E785',#1651,#1653,#1649,.T.);
#1655=ORIENTED_EDGE('',*,*,#1654,.F.);
#1656=DIRECTION('',(0.,1.,0.));
#1657=VECTOR('',#1656,1.);
#1658=CARTESIAN_POINT('',(-6.34999999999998,12.7,42.8625));
#1659=LINE('',#1658,#1657);
#1660=EDGE_CURVE('E1051',#1651,#343,#1659,.T.);
#1661=ORIENTED_EDGE('',*,*,#1660,.T.);
#1662=ORIENTED_EDGE('',*,*,#346,.T.);
#1663=DIRECTION('',(0.,1.,0.));
#1664=VECTOR('',#1663,1.);
#1665=CARTESIAN_POINT('',(-6.34999999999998,6.35,20.6375));
#1666=LINE('',#1665,#1664);
#1667=EDGE_CURVE('E1049',#345,#1653,#1666,.F.);
#1668=ORIENTED_EDGE('',*,*,#1667,.T.);
#1669=EDGE_LOOP('',(#1655,#1661,#1662,#1668));
#1670=FACE_BOUND('',#1669,.T.);
#1671=ADVANCED_FACE('F1606',(#1670),#1645,.F.);
#1672=CARTESIAN_POINT('',(-6.34999999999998,6.35,44.45));
#1673=DIRECTION('',(0.,0.,1.));
#1674=DIRECTION('',(1.,0.,0.));
#1675=AXIS2_PLACEMENT_3D('',#1672,#1673,#1674);
#1676=PLANE('',#1675);
#1677=DIRECTION('',(1.,0.,0.));
#1678=VECTOR('',#1677,1.);
#1679=CARTESIAN_POINT('',(-6.34999999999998,6.35,44.45));
#1680=LINE('',#1679,#1678);
#1681=CARTESIAN_POINT('',(-30.1625,6.35,44.45));
#1682=VERTEX_POINT('',#1681);
#1683=CARTESIAN_POINT('',(-7.93749999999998,6.35,44.45));
#1684=VERTEX_POINT('',#1683);
#1685=EDGE_CURVE('E794',#1682,#1684,#1680,.T.);
#1686=ORIENTED_EDGE('',*,*,#1685,.F.);
#1687=DIRECTION('',(0.,1.,0.));
#1688=VECTOR('',#1687,1.);
#1689=CARTESIAN_POINT('',(-30.1625,12.7,44.45));
#1690=LINE('',#1689,#1688);
#1691=EDGE_CURVE('E1033',#1682,#362,#1690,.T.);
#1692=ORIENTED_EDGE('',*,*,#1691,.T.);
#1693=ORIENTED_EDGE('',*,*,#363,.T.);
#1694=DIRECTION('',(0.,1.,0.));
#1695=VECTOR('',#1694,1.);
#1696=CARTESIAN_POINT('',(-7.93749999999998,6.35,44.45));
#1697=LINE('',#1696,#1695);
#1698=EDGE_CURVE('E1031',#354,#1684,#1697,.F.);
#1699=ORIENTED_EDGE('',*,*,#1698,.T.);
#1700=EDGE_LOOP('',(#1686,#1692,#1693,#1699));
#1701=FACE_BOUND('',#1700,.T.);
#1702=ADVANCED_FACE('F1602',(#1701),#1676,.F.);
#1703=CARTESIAN_POINT('',(-31.75,6.35,19.05));
#1704=DIRECTION('',(-1.,0.,0.));
#1705=DIRECTION('',(0.,0.,1.));
#1706=AXIS2_PLACEMENT_3D('',#1703,#1704,#1705);
#1707=PLANE('',#1706);
#1708=ORIENTED_EDGE('',*,*,#380,.T.);
#1709=DIRECTION('',(0.,1.,0.));
#1710=VECTOR('',#1709,1.);
#1711=CARTESIAN_POINT('',(-31.75,6.35,42.8625));
#1712=LINE('',#1711,#1710);
#1713=CARTESIAN_POINT('',(-31.75,6.35,42.8625));
#1714=VERTEX_POINT('',#1713);
#1715=EDGE_CURVE('E1039',#371,#1714,#1712,.F.);
#1716=ORIENTED_EDGE('',*,*,#1715,.T.);
#1717=DIRECTION('',(0.,0.,1.));
#1718=VECTOR('',#1717,1.);
#1719=CARTESIAN_POINT('',(-31.75,6.35,19.05));
#1720=LINE('',#1719,#1718);
#1721=CARTESIAN_POINT('',(-31.75,6.35,20.6375));
#1722=VERTEX_POINT('',#1721);
#1723=EDGE_CURVE('E791',#1722,#1714,#1720,.T.);
#1724=ORIENTED_EDGE('',*,*,#1723,.F.);
#1725=DIRECTION('',(0.,1.,0.));
#1726=VECTOR('',#1725,1.);
#1727=CARTESIAN_POINT('',(-31.75,12.7,20.6375));
#1728=LINE('',#1727,#1726);
#1729=EDGE_CURVE('E1036',#1722,#379,#1728,.T.);
#1730=ORIENTED_EDGE('',*,*,#1729,.T.);
#1731=EDGE_LOOP('',(#1708,#1716,#1724,#1730));
#1732=FACE_BOUND('',#1731,.T.);
#1733=ADVANCED_FACE('F1605',(#1732),#1707,.F.);
#1734=CARTESIAN_POINT('',(-6.34999999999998,6.35,19.05));
#1735=DIRECTION('',(0.,0.,-1.));
#1736=DIRECTION('',(-1.,0.,0.));
#1737=AXIS2_PLACEMENT_3D('',#1734,#1735,#1736);
#1738=PLANE('',#1737);
#1739=DIRECTION('',(-1.,0.,0.));
#1740=VECTOR('',#1739,1.);
#1741=CARTESIAN_POINT('',(-6.34999999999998,6.35,19.05));
#1742=LINE('',#1741,#1740);
#1743=CARTESIAN_POINT('',(-7.93749999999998,6.35,19.05));
#1744=VERTEX_POINT('',#1743);
#1745=CARTESIAN_POINT('',(-30.1625,6.35,19.05));
#1746=VERTEX_POINT('',#1745);
#1747=EDGE_CURVE('E788',#1744,#1746,#1742,.T.);
#1748=ORIENTED_EDGE('',*,*,#1747,.F.);
#1749=DIRECTION('',(0.,1.,0.));
#1750=VECTOR('',#1749,1.);
#1751=CARTESIAN_POINT('',(-7.93749999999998,12.7,19.05));
#1752=LINE('',#1751,#1750);
#1753=EDGE_CURVE('E1056',#1744,#396,#1752,.T.);
#1754=ORIENTED_EDGE('',*,*,#1753,.T.);
#1755=ORIENTED_EDGE('',*,*,#397,.T.);
#1756=DIRECTION('',(0.,1.,0.));
#1757=VECTOR('',#1756,1.);
#1758=CARTESIAN_POINT('',(-30.1625,6.35,19.05));
#1759=LINE('',#1758,#1757);
#1760=EDGE_CURVE('E1054',#388,#1746,#1759,.F.);
#1761=ORIENTED_EDGE('',*,*,#1760,.T.);
#1762=EDGE_LOOP('',(#1748,#1754,#1755,#1761));
#1763=FACE_BOUND('',#1762,.T.);
#1764=ADVANCED_FACE('F1600',(#1763),#1738,.F.);
#1765=CARTESIAN_POINT('',(-6.34999999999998,6.35,44.45));
#1766=DIRECTION('',(0.,-1.,0.));
#1767=DIRECTION('',(0.,0.,-1.));
#1768=AXIS2_PLACEMENT_3D('',#1765,#1766,#1767);
#1769=PLANE('',#1768);
#1770=ORIENTED_EDGE('',*,*,#1723,.T.);
#1771=CARTESIAN_POINT('',(-30.1625,6.35,42.8625));
#1772=DIRECTION('',(0.,-1.,0.));
#1773=DIRECTION('',(0.,0.,-1.));
#1774=AXIS2_PLACEMENT_3D('',#1771,#1772,#1773);
#1775=CIRCLE('',#1774,1.5875);
#1776=EDGE_CURVE('E1047',#1714,#1682,#1775,.F.);
#1777=ORIENTED_EDGE('',*,*,#1776,.T.);
#1778=ORIENTED_EDGE('',*,*,#1685,.T.);
#1779=CARTESIAN_POINT('',(-7.93749999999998,6.35,42.8625));
#1780=DIRECTION('',(0.,-1.,0.));
#1781=DIRECTION('',(0.,0.,-1.));
#1782=AXIS2_PLACEMENT_3D('',#1779,#1780,#1781);
#1783=CIRCLE('',#1782,1.5875);
#1784=EDGE_CURVE('E1045',#1684,#1651,#1783,.F.);
#1785=ORIENTED_EDGE('',*,*,#1784,.T.);
#1786=ORIENTED_EDGE('',*,*,#1654,.T.);
#1787=CARTESIAN_POINT('',(-7.93749999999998,6.35,20.6375));
#1788=DIRECTION('',(0.,-1.,0.));
#1789=DIRECTION('',(0.,0.,-1.));
#1790=AXIS2_PLACEMENT_3D('',#1787,#1788,#1789);
#1791=CIRCLE('',#1790,1.5875);
#1792=EDGE_CURVE('E1043',#1653,#1744,#1791,.F.);
#1793=ORIENTED_EDGE('',*,*,#1792,.T.);
#1794=ORIENTED_EDGE('',*,*,#1747,.T.);
#1795=CARTESIAN_POINT('',(-30.1625,6.35,20.6375));
#1796=DIRECTION('',(0.,-1.,0.));
#1797=DIRECTION('',(0.,0.,-1.));
#1798=AXIS2_PLACEMENT_3D('',#1795,#1796,#1797);
#1799=CIRCLE('',#1798,1.5875);
#1800=EDGE_CURVE('E1041',#1746,#1722,#1799,.F.);
#1801=ORIENTED_EDGE('',*,*,#1800,.T.);
#1802=EDGE_LOOP('',(#1770,#1777,#1778,#1785,#1786,#1793,#1794,#1801));
#1803=FACE_BOUND('',#1802,.T.);
#1804=ADVANCED_FACE('F1596',(#1803),#1769,.F.);
#1805=CARTESIAN_POINT('',(31.75,6.35,-44.45));
#1806=DIRECTION('',(1.,0.,0.));
#1807=DIRECTION('',(0.,0.,-1.));
#1808=AXIS2_PLACEMENT_3D('',#1805,#1806,#1807);
#1809=PLANE('',#1808);
#1810=DIRECTION('',(0.,0.,-1.));
#1811=VECTOR('',#1810,1.);
#1812=CARTESIAN_POINT('',(31.75,6.35,-44.45));
#1813=LINE('',#1812,#1811);
#1814=CARTESIAN_POINT('',(31.75,6.35,-20.6375));
#1815=VERTEX_POINT('',#1814);
#1816=CARTESIAN_POINT('',(31.75,6.35,-42.8625));
#1817=VERTEX_POINT('',#1816);
#1818=EDGE_CURVE('E761',#1815,#1817,#1813,.T.);
#1819=ORIENTED_EDGE('',*,*,#1818,.F.);
#1820=DIRECTION('',(0.,1.,0.));
#1821=VECTOR('',#1820,1.);
#1822=CARTESIAN_POINT('',(31.75,12.7,-20.6375));
#1823=LINE('',#1822,#1821);
#1824=EDGE_CURVE('E1087',#1815,#413,#1823,.T.);
#1825=ORIENTED_EDGE('',*,*,#1824,.T.);
#1826=ORIENTED_EDGE('',*,*,#416,.T.);
#1827=DIRECTION('',(0.,1.,0.));
#1828=VECTOR('',#1827,1.);
#1829=CARTESIAN_POINT('',(31.75,6.35,-42.8625));
#1830=LINE('',#1829,#1828);
#1831=EDGE_CURVE('E1085',#415,#1817,#1830,.F.);
#1832=ORIENTED_EDGE('',*,*,#1831,.T.);
#1833=EDGE_LOOP('',(#1819,#1825,#1826,#1832));
#1834=FACE_BOUND('',#1833,.T.);
#1835=ADVANCED_FACE('F1586',(#1834),#1809,.F.);
#1836=CARTESIAN_POINT('',(31.75,6.35,-19.05));
#1837=DIRECTION('',(0.,0.,1.));
#1838=DIRECTION('',(1.,0.,0.));
#1839=AXIS2_PLACEMENT_3D('',#1836,#1837,#1838);
#1840=PLANE('',#1839);
#1841=DIRECTION('',(1.,0.,0.));
#1842=VECTOR('',#1841,1.);
#1843=CARTESIAN_POINT('',(31.75,6.35,-19.05));
#1844=LINE('',#1843,#1842);
#1845=CARTESIAN_POINT('',(7.93750000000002,6.35,-19.05));
#1846=VERTEX_POINT('',#1845);
#1847=CARTESIAN_POINT('',(30.1625,6.35,-19.05));
#1848=VERTEX_POINT('',#1847);
#1849=EDGE_CURVE('E770',#1846,#1848,#1844,.T.);
#1850=ORIENTED_EDGE('',*,*,#1849,.F.);
#1851=DIRECTION('',(0.,1.,0.));
#1852=VECTOR('',#1851,1.);
#1853=CARTESIAN_POINT('',(7.93750000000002,12.7,-19.05));
#1854=LINE('',#1853,#1852);
#1855=EDGE_CURVE('E1069',#1846,#432,#1854,.T.);
#1856=ORIENTED_EDGE('',*,*,#1855,.T.);
#1857=ORIENTED_EDGE('',*,*,#433,.T.);
#1858=DIRECTION('',(0.,1.,0.));
#1859=VECTOR('',#1858,1.);
#1860=CARTESIAN_POINT('',(30.1625,6.35,-19.05));
#1861=LINE('',#1860,#1859);
#1862=EDGE_CURVE('E1067',#424,#1848,#1861,.F.);
#1863=ORIENTED_EDGE('',*,*,#1862,.T.);
#1864=EDGE_LOOP('',(#1850,#1856,#1857,#1863));
#1865=FACE_BOUND('',#1864,.T.);
#1866=ADVANCED_FACE('F1582',(#1865),#1840,.F.);
#1867=CARTESIAN_POINT('',(6.35000000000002,6.35,-44.45));
#1868=DIRECTION('',(-1.,0.,0.));
#1869=DIRECTION('',(0.,0.,1.));
#1870=AXIS2_PLACEMENT_3D('',#1867,#1868,#1869);
#1871=PLANE('',#1870);
#1872=ORIENTED_EDGE('',*,*,#450,.T.);
#1873=DIRECTION('',(0.,1.,0.));
#1874=VECTOR('',#1873,1.);
#1875=CARTESIAN_POINT('',(6.35000000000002,6.35,-20.6375));
#1876=LINE('',#1875,#1874);
#1877=CARTESIAN_POINT('',(6.35000000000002,6.35,-20.6375));
#1878=VERTEX_POINT('',#1877);
#1879=EDGE_CURVE('E1075',#441,#1878,#1876,.F.);
#1880=ORIENTED_EDGE('',*,*,#1879,.T.);
#1881=DIRECTION('',(0.,0.,1.));
#1882=VECTOR('',#1881,1.);
#1883=CARTESIAN_POINT('',(6.35000000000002,6.35,-44.45));
#1884=LINE('',#1883,#1882);
#1885=CARTESIAN_POINT('',(6.35000000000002,6.35,-42.8625));
#1886=VERTEX_POINT('',#1885);
#1887=EDGE_CURVE('E767',#1886,#1878,#1884,.T.);
#1888=ORIENTED_EDGE('',*,*,#1887,.F.);
#1889=DIRECTION('',(0.,1.,0.));
#1890=VECTOR('',#1889,1.);
#1891=CARTESIAN_POINT('',(6.35000000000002,12.7,-42.8625));
#1892=LINE('',#1891,#1890);
#1893=EDGE_CURVE('E1072',#1886,#449,#1892,.T.);
#1894=ORIENTED_EDGE('',*,*,#1893,.T.);
#1895=EDGE_LOOP('',(#1872,#1880,#1888,#1894));
#1896=FACE_BOUND('',#1895,.T.);
#1897=ADVANCED_FACE('F1585',(#1896),#1871,.F.);
#1898=CARTESIAN_POINT('',(31.75,6.35,-44.45));
#1899=DIRECTION('',(0.,0.,-1.));
#1900=DIRECTION('',(-1.,0.,0.));
#1901=AXIS2_PLACEMENT_3D('',#1898,#1899,#1900);
#1902=PLANE('',#1901);
#1903=DIRECTION('',(-1.,0.,0.));
#1904=VECTOR('',#1903,1.);
#1905=CARTESIAN_POINT('',(31.75,6.35,-44.45));
#1906=LINE('',#1905,#1904);
#1907=CARTESIAN_POINT('',(30.1625,6.35,-44.45));
#1908=VERTEX_POINT('',#1907);
#1909=CARTESIAN_POINT('',(7.93750000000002,6.35,-44.45));
#1910=VERTEX_POINT('',#1909);
#1911=EDGE_CURVE('E764',#1908,#1910,#1906,.T.);
#1912=ORIENTED_EDGE('',*,*,#1911,.F.);
#1913=DIRECTION('',(0.,1.,0.));
#1914=VECTOR('',#1913,1.);
#1915=CARTESIAN_POINT('',(30.1625,12.7,-44.45));
#1916=LINE('',#1915,#1914);
#1917=EDGE_CURVE('E1092',#1908,#466,#1916,.T.);
#1918=ORIENTED_EDGE('',*,*,#1917,.T.);
#1919=ORIENTED_EDGE('',*,*,#467,.T.);
#1920=DIRECTION('',(0.,1.,0.));
#1921=VECTOR('',#1920,1.);
#1922=CARTESIAN_POINT('',(7.93750000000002,6.35,-44.45));
#1923=LINE('',#1922,#1921);
#1924=EDGE_CURVE('E1090',#458,#1910,#1923,.F.);
#1925=ORIENTED_EDGE('',*,*,#1924,.T.);
#1926=EDGE_LOOP('',(#1912,#1918,#1919,#1925));
#1927=FACE_BOUND('',#1926,.T.);
#1928=ADVANCED_FACE('F1580',(#1927),#1902,.F.);
#1929=CARTESIAN_POINT('',(31.75,6.35,-19.05));
#1930=DIRECTION('',(0.,-1.,0.));
#1931=DIRECTION('',(0.,0.,-1.));
#1932=AXIS2_PLACEMENT_3D('',#1929,#1930,#1931);
#1933=PLANE('',#1932);
#1934=ORIENTED_EDGE('',*,*,#1887,.T.);
#1935=CARTESIAN_POINT('',(7.93750000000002,6.35,-20.6375));
#1936=DIRECTION('',(0.,-1.,0.));
#1937=DIRECTION('',(0.,0.,-1.));
#1938=AXIS2_PLACEMENT_3D('',#1935,#1936,#1937);
#1939=CIRCLE('',#1938,1.5875);
#1940=EDGE_CURVE('E1083',#1878,#1846,#1939,.F.);
#1941=ORIENTED_EDGE('',*,*,#1940,.T.);
#1942=ORIENTED_EDGE('',*,*,#1849,.T.);
#1943=CARTESIAN_POINT('',(30.1625,6.35,-20.6375));
#1944=DIRECTION('',(0.,-1.,0.));
#1945=DIRECTION('',(0.,0.,-1.));
#1946=AXIS2_PLACEMENT_3D('',#1943,#1944,#1945);
#1947=CIRCLE('',#1946,1.5875);
#1948=EDGE_CURVE('E1081',#1848,#1815,#1947,.F.);
#1949=ORIENTED_EDGE('',*,*,#1948,.T.);
#1950=ORIENTED_EDGE('',*,*,#1818,.T.);
#1951=CARTESIAN_POINT('',(30.1625,6.35,-42.8625));
#1952=DIRECTION('',(0.,-1.,0.));
#1953=DIRECTION('',(0.,0.,-1.));
#1954=AXIS2_PLACEMENT_3D('',#1951,#1952,#1953);
#1955=CIRCLE('',#1954,1.5875);
#1956=EDGE_CURVE('E1079',#1817,#1908,#1955,.F.);
#1957=ORIENTED_EDGE('',*,*,#1956,.T.);
#1958=ORIENTED_EDGE('',*,*,#1911,.T.);
#1959=CARTESIAN_POINT('',(7.93750000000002,6.35,-42.8625));
#1960=DIRECTION('',(0.,-1.,0.));
#1961=DIRECTION('',(0.,0.,-1.));
#1962=AXIS2_PLACEMENT_3D('',#1959,#1960,#1961);
#1963=CIRCLE('',#1962,1.5875);
#1964=EDGE_CURVE('E1077',#1910,#1886,#1963,.F.);
#1965=ORIENTED_EDGE('',*,*,#1964,.T.);
#1966=EDGE_LOOP('',(#1934,#1941,#1942,#1949,#1950,#1957,#1958,#1965));
#1967=FACE_BOUND('',#1966,.T.);
#1968=ADVANCED_FACE('F1576',(#1967),#1933,.F.);
#1969=CARTESIAN_POINT('',(31.75,6.35,19.05));
#1970=DIRECTION('',(1.,0.,0.));
#1971=DIRECTION('',(0.,0.,-1.));
#1972=AXIS2_PLACEMENT_3D('',#1969,#1970,#1971);
#1973=PLANE('',#1972);
#1974=DIRECTION('',(0.,0.,-1.));
#1975=VECTOR('',#1974,1.);
#1976=CARTESIAN_POINT('',(31.75,6.35,19.05));
#1977=LINE('',#1976,#1975);
#1978=CARTESIAN_POINT('',(31.75,6.35,42.8625));
#1979=VERTEX_POINT('',#1978);
#1980=CARTESIAN_POINT('',(31.75,6.35,20.6375));
#1981=VERTEX_POINT('',#1980);
#1982=EDGE_CURVE('E737',#1979,#1981,#1977,.T.);
#1983=ORIENTED_EDGE('',*,*,#1982,.F.);
#1984=DIRECTION('',(0.,1.,0.));
#1985=VECTOR('',#1984,1.);
#1986=CARTESIAN_POINT('',(31.75,12.7,42.8625));
#1987=LINE('',#1986,#1985);
#1988=EDGE_CURVE('E1123',#1979,#483,#1987,.T.);
#1989=ORIENTED_EDGE('',*,*,#1988,.T.);
#1990=ORIENTED_EDGE('',*,*,#486,.T.);
#1991=DIRECTION('',(0.,1.,0.));
#1992=VECTOR('',#1991,1.);
#1993=CARTESIAN_POINT('',(31.75,6.35,20.6375));
#1994=LINE('',#1993,#1992);
#1995=EDGE_CURVE('E1121',#485,#1981,#1994,.F.);
#1996=ORIENTED_EDGE('',*,*,#1995,.T.);
#1997=EDGE_LOOP('',(#1983,#1989,#1990,#1996));
#1998=FACE_BOUND('',#1997,.T.);
#1999=ADVANCED_FACE('F1566',(#1998),#1973,.F.);
#2000=CARTESIAN_POINT('',(31.75,6.35,44.45));
#2001=DIRECTION('',(0.,0.,1.));
#2002=DIRECTION('',(1.,0.,0.));
#2003=AXIS2_PLACEMENT_3D('',#2000,#2001,#2002);
#2004=PLANE('',#2003);
#2005=DIRECTION('',(1.,0.,0.));
#2006=VECTOR('',#2005,1.);
#2007=CARTESIAN_POINT('',(31.75,6.35,44.45));
#2008=LINE('',#2007,#2006);
#2009=CARTESIAN_POINT('',(7.93750000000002,6.35,44.45));
#2010=VERTEX_POINT('',#2009);
#2011=CARTESIAN_POINT('',(30.1625,6.35,44.45));
#2012=VERTEX_POINT('',#2011);
#2013=EDGE_CURVE('E746',#2010,#2012,#2008,.T.);
#2014=ORIENTED_EDGE('',*,*,#2013,.F.);
#2015=DIRECTION('',(0.,1.,0.));
#2016=VECTOR('',#2015,1.);
#2017=CARTESIAN_POINT('',(7.93750000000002,12.7,44.45));
#2018=LINE('',#2017,#2016);
#2019=EDGE_CURVE('E1105',#2010,#502,#2018,.T.);
#2020=ORIENTED_EDGE('',*,*,#2019,.T.);
#2021=ORIENTED_EDGE('',*,*,#503,.T.);
#2022=DIRECTION('',(0.,1.,0.));
#2023=VECTOR('',#2022,1.);
#2024=CARTESIAN_POINT('',(30.1625,6.35,44.45));
#2025=LINE('',#2024,#2023);
#2026=EDGE_CURVE('E1103',#494,#2012,#2025,.F.);
#2027=ORIENTED_EDGE('',*,*,#2026,.T.);
#2028=EDGE_LOOP('',(#2014,#2020,#2021,#2027));
#2029=FACE_BOUND('',#2028,.T.);
#2030=ADVANCED_FACE('F1562',(#2029),#2004,.F.);
#2031=CARTESIAN_POINT('',(6.35000000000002,6.35,19.05));
#2032=DIRECTION('',(-1.,0.,0.));
#2033=DIRECTION('',(0.,0.,1.));
#2034=AXIS2_PLACEMENT_3D('',#2031,#2032,#2033);
#2035=PLANE('',#2034);
#2036=ORIENTED_EDGE('',*,*,#520,.T.);
#2037=DIRECTION('',(0.,1.,0.));
#2038=VECTOR('',#2037,1.);
#2039=CARTESIAN_POINT('',(6.35000000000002,6.35,42.8625));
#2040=LINE('',#2039,#2038);
#2041=CARTESIAN_POINT('',(6.35000000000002,6.35,42.8625));
#2042=VERTEX_POINT('',#2041);
#2043=EDGE_CURVE('E1111',#511,#2042,#2040,.F.);
#2044=ORIENTED_EDGE('',*,*,#2043,.T.);
#2045=DIRECTION('',(0.,0.,1.));
#2046=VECTOR('',#2045,1.);
#2047=CARTESIAN_POINT('',(6.35000000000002,6.35,19.05));
#2048=LINE('',#2047,#2046);
#2049=CARTESIAN_POINT('',(6.35000000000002,6.35,20.6375));
#2050=VERTEX_POINT('',#2049);
#2051=EDGE_CURVE('E743',#2050,#2042,#2048,.T.);
#2052=ORIENTED_EDGE('',*,*,#2051,.F.);
#2053=DIRECTION('',(0.,1.,0.));
#2054=VECTOR('',#2053,1.);
#2055=CARTESIAN_POINT('',(6.35000000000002,12.7,20.6375));
#2056=LINE('',#2055,#2054);
#2057=EDGE_CURVE('E1108',#2050,#519,#2056,.T.);
#2058=ORIENTED_EDGE('',*,*,#2057,.T.);
#2059=EDGE_LOOP('',(#2036,#2044,#2052,#2058));
#2060=FACE_BOUND('',#2059,.T.);
#2061=ADVANCED_FACE('F1565',(#2060),#2035,.F.);
#2062=CARTESIAN_POINT('',(31.75,6.35,19.05));
#2063=DIRECTION('',(0.,0.,-1.));
#2064=DIRECTION('',(-1.,0.,0.));
#2065=AXIS2_PLACEMENT_3D('',#2062,#2063,#2064);
#2066=PLANE('',#2065);
#2067=DIRECTION('',(-1.,0.,0.));
#2068=VECTOR('',#2067,1.);
#2069=CARTESIAN_POINT('',(31.75,6.35,19.05));
#2070=LINE('',#2069,#2068);
#2071=CARTESIAN_POINT('',(30.1625,6.35,19.05));
#2072=VERTEX_POINT('',#2071);
#2073=CARTESIAN_POINT('',(7.93750000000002,6.35,19.05));
#2074=VERTEX_POINT('',#2073);
#2075=EDGE_CURVE('E740',#2072,#2074,#2070,.T.);
#2076=ORIENTED_EDGE('',*,*,#2075,.F.);
#2077=DIRECTION('',(0.,1.,0.));
#2078=VECTOR('',#2077,1.);
#2079=CARTESIAN_POINT('',(30.1625,12.7,19.05));
#2080=LINE('',#2079,#2078);
#2081=EDGE_CURVE('E1128',#2072,#536,#2080,.T.);
#2082=ORIENTED_EDGE('',*,*,#2081,.T.);
#2083=ORIENTED_EDGE('',*,*,#537,.T.);
#2084=DIRECTION('',(0.,1.,0.));
#2085=VECTOR('',#2084,1.);
#2086=CARTESIAN_POINT('',(7.93750000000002,6.35,19.05));
#2087=LINE('',#2086,#2085);
#2088=EDGE_CURVE('E1126',#528,#2074,#2087,.F.);
#2089=ORIENTED_EDGE('',*,*,#2088,.T.);
#2090=EDGE_LOOP('',(#2076,#2082,#2083,#2089));
#2091=FACE_BOUND('',#2090,.T.);
#2092=ADVANCED_FACE('F1560',(#2091),#2066,.F.);
#2093=CARTESIAN_POINT('',(31.75,6.35,44.45));
#2094=DIRECTION('',(0.,-1.,0.));
#2095=DIRECTION('',(0.,0.,-1.));
#2096=AXIS2_PLACEMENT_3D('',#2093,#2094,#2095);
#2097=PLANE('',#2096);
#2098=ORIENTED_EDGE('',*,*,#2051,.T.);
#2099=CARTESIAN_POINT('',(7.93750000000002,6.35,42.8625));
#2100=DIRECTION('',(0.,-1.,0.));
#2101=DIRECTION('',(0.,0.,-1.));
#2102=AXIS2_PLACEMENT_3D('',#2099,#2100,#2101);
#2103=CIRCLE('',#2102,1.5875);
#2104=EDGE_CURVE('E1119',#2042,#2010,#2103,.F.);
#2105=ORIENTED_EDGE('',*,*,#2104,.T.);
#2106=ORIENTED_EDGE('',*,*,#2013,.T.);
#2107=CARTESIAN_POINT('',(30.1625,6.35,42.8625));
#2108=DIRECTION('',(0.,-1.,0.));
#2109=DIRECTION('',(0.,0.,-1.));
#2110=AXIS2_PLACEMENT_3D('',#2107,#2108,#2109);
#2111=CIRCLE('',#2110,1.5875);
#2112=EDGE_CURVE('E1117',#2012,#1979,#2111,.F.);
#2113=ORIENTED_EDGE('',*,*,#2112,.T.);
#2114=ORIENTED_EDGE('',*,*,#1982,.T.);
#2115=CARTESIAN_POINT('',(30.1625,6.35,20.6375));
#2116=DIRECTION('',(0.,-1.,0.));
#2117=DIRECTION('',(0.,0.,-1.));
#2118=AXIS2_PLACEMENT_3D('',#2115,#2116,#2117);
#2119=CIRCLE('',#2118,1.5875);
#2120=EDGE_CURVE('E1115',#1981,#2072,#2119,.F.);
#2121=ORIENTED_EDGE('',*,*,#2120,.T.);
#2122=ORIENTED_EDGE('',*,*,#2075,.T.);
#2123=CARTESIAN_POINT('',(7.93750000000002,6.35,20.6375));
#2124=DIRECTION('',(0.,-1.,0.));
#2125=DIRECTION('',(0.,0.,-1.));
#2126=AXIS2_PLACEMENT_3D('',#2123,#2124,#2125);
#2127=CIRCLE('',#2126,1.5875);
#2128=EDGE_CURVE('E1113',#2074,#2050,#2127,.F.);
#2129=ORIENTED_EDGE('',*,*,#2128,.T.);
#2130=EDGE_LOOP('',(#2098,#2105,#2106,#2113,#2114,#2121,#2122,#2129));
#2131=FACE_BOUND('',#2130,.T.);
#2132=ADVANCED_FACE('F1556',(#2131),#2097,.F.);
#2133=CARTESIAN_POINT('',(69.85,6.35,-44.45));
#2134=DIRECTION('',(1.,0.,0.));
#2135=DIRECTION('',(0.,0.,-1.));
#2136=AXIS2_PLACEMENT_3D('',#2133,#2134,#2135);
#2137=PLANE('',#2136);
#2138=DIRECTION('',(0.,0.,-1.));
#2139=VECTOR('',#2138,1.);
#2140=CARTESIAN_POINT('',(69.85,6.35,-44.45));
#2141=LINE('',#2140,#2139);
#2142=CARTESIAN_POINT('',(69.85,6.35,-20.6375));
#2143=VERTEX_POINT('',#2142);
#2144=CARTESIAN_POINT('',(69.85,6.35,-42.8625));
#2145=VERTEX_POINT('',#2144);
#2146=EDGE_CURVE('E713',#2143,#2145,#2141,.T.);
#2147=ORIENTED_EDGE('',*,*,#2146,.F.);
#2148=DIRECTION('',(0.,1.,0.));
#2149=VECTOR('',#2148,1.);
#2150=CARTESIAN_POINT('',(69.85,12.7,-20.6375));
#2151=LINE('',#2150,#2149);
#2152=EDGE_CURVE('E1159',#2143,#553,#2151,.T.);
#2153=ORIENTED_EDGE('',*,*,#2152,.T.);
#2154=ORIENTED_EDGE('',*,*,#556,.T.);
#2155=DIRECTION('',(0.,1.,0.));
#2156=VECTOR('',#2155,1.);
#2157=CARTESIAN_POINT('',(69.85,6.35,-42.8625));
#2158=LINE('',#2157,#2156);
#2159=EDGE_CURVE('E1157',#555,#2145,#2158,.F.);
#2160=ORIENTED_EDGE('',*,*,#2159,.T.);
#2161=EDGE_LOOP('',(#2147,#2153,#2154,#2160));
#2162=FACE_BOUND('',#2161,.T.);
#2163=ADVANCED_FACE('F1546',(#2162),#2137,.F.);
#2164=CARTESIAN_POINT('',(69.85,6.35,-19.05));
#2165=DIRECTION('',(0.,0.,1.));
#2166=DIRECTION('',(1.,0.,0.));
#2167=AXIS2_PLACEMENT_3D('',#2164,#2165,#2166);
#2168=PLANE('',#2167);
#2169=DIRECTION('',(1.,0.,0.));
#2170=VECTOR('',#2169,1.);
#2171=CARTESIAN_POINT('',(69.85,6.35,-19.05));
#2172=LINE('',#2171,#2170);
#2173=CARTESIAN_POINT('',(46.0375,6.35,-19.05));
#2174=VERTEX_POINT('',#2173);
#2175=CARTESIAN_POINT('',(68.2625,6.35,-19.05));
#2176=VERTEX_POINT('',#2175);
#2177=EDGE_CURVE('E722',#2174,#2176,#2172,.T.);
#2178=ORIENTED_EDGE('',*,*,#2177,.F.);
#2179=DIRECTION('',(0.,1.,0.));
#2180=VECTOR('',#2179,1.);
#2181=CARTESIAN_POINT('',(46.0375,12.7,-19.05));
#2182=LINE('',#2181,#2180);
#2183=EDGE_CURVE('E1141',#2174,#572,#2182,.T.);
#2184=ORIENTED_EDGE('',*,*,#2183,.T.);
#2185=ORIENTED_EDGE('',*,*,#573,.T.);
#2186=DIRECTION('',(0.,1.,0.));
#2187=VECTOR('',#2186,1.);
#2188=CARTESIAN_POINT('',(68.2625,6.35,-19.05));
#2189=LINE('',#2188,#2187);
#2190=EDGE_CURVE('E1139',#564,#2176,#2189,.F.);
#2191=ORIENTED_EDGE('',*,*,#2190,.T.);
#2192=EDGE_LOOP('',(#2178,#2184,#2185,#2191));
#2193=FACE_BOUND('',#2192,.T.);
#2194=ADVANCED_FACE('F1542',(#2193),#2168,.F.);
#2195=CARTESIAN_POINT('',(44.45,6.35,-44.45));
#2196=DIRECTION('',(-1.,0.,0.));
#2197=DIRECTION('',(0.,0.,1.));
#2198=AXIS2_PLACEMENT_3D('',#2195,#2196,#2197);
#2199=PLANE('',#2198);
#2200=ORIENTED_EDGE('',*,*,#590,.T.);
#2201=DIRECTION('',(0.,1.,0.));
#2202=VECTOR('',#2201,1.);
#2203=CARTESIAN_POINT('',(44.45,6.35,-20.6375));
#2204=LINE('',#2203,#2202);
#2205=CARTESIAN_POINT('',(44.45,6.35,-20.6375));
#2206=VERTEX_POINT('',#2205);
#2207=EDGE_CURVE('E1147',#581,#2206,#2204,.F.);
#2208=ORIENTED_EDGE('',*,*,#2207,.T.);
#2209=DIRECTION('',(0.,0.,1.));
#2210=VECTOR('',#2209,1.);
#2211=CARTESIAN_POINT('',(44.45,6.35,-44.45));
#2212=LINE('',#2211,#2210);
#2213=CARTESIAN_POINT('',(44.45,6.35,-42.8625));
#2214=VERTEX_POINT('',#2213);
#2215=EDGE_CURVE('E719',#2214,#2206,#2212,.T.);
#2216=ORIENTED_EDGE('',*,*,#2215,.F.);
#2217=DIRECTION('',(0.,1.,0.));
#2218=VECTOR('',#2217,1.);
#2219=CARTESIAN_POINT('',(44.45,12.7,-42.8625));
#2220=LINE('',#2219,#2218);
#2221=EDGE_CURVE('E1144',#2214,#589,#2220,.T.);
#2222=ORIENTED_EDGE('',*,*,#2221,.T.);
#2223=EDGE_LOOP('',(#2200,#2208,#2216,#2222));
#2224=FACE_BOUND('',#2223,.T.);
#2225=ADVANCED_FACE('F1545',(#2224),#2199,.F.);
#2226=CARTESIAN_POINT('',(69.85,6.35,-44.45));
#2227=DIRECTION('',(0.,0.,-1.));
#2228=DIRECTION('',(-1.,0.,0.));
#2229=AXIS2_PLACEMENT_3D('',#2226,#2227,#2228);
#2230=PLANE('',#2229);
#2231=DIRECTION('',(-1.,0.,0.));
#2232=VECTOR('',#2231,1.);
#2233=CARTESIAN_POINT('',(69.85,6.35,-44.45));
#2234=LINE('',#2233,#2232);
#2235=CARTESIAN_POINT('',(68.2625,6.35,-44.45));
#2236=VERTEX_POINT('',#2235);
#2237=CARTESIAN_POINT('',(46.0375,6.35,-44.45));
#2238=VERTEX_POINT('',#2237);
#2239=EDGE_CURVE('E716',#2236,#2238,#2234,.T.);
#2240=ORIENTED_EDGE('',*,*,#2239,.F.);
#2241=DIRECTION('',(0.,1.,0.));
#2242=VECTOR('',#2241,1.);
#2243=CARTESIAN_POINT('',(68.2625,12.7,-44.45));
#2244=LINE('',#2243,#2242);
#2245=EDGE_CURVE('E1164',#2236,#606,#2244,.T.);
#2246=ORIENTED_EDGE('',*,*,#2245,.T.);
#2247=ORIENTED_EDGE('',*,*,#607,.T.);
#2248=DIRECTION('',(0.,1.,0.));
#2249=VECTOR('',#2248,1.);
#2250=CARTESIAN_POINT('',(46.0375,6.35,-44.45));
#2251=LINE('',#2250,#2249);
#2252=EDGE_CURVE('E1162',#598,#2238,#2251,.F.);
#2253=ORIENTED_EDGE('',*,*,#2252,.T.);
#2254=EDGE_LOOP('',(#2240,#2246,#2247,#2253));
#2255=FACE_BOUND('',#2254,.T.);
#2256=ADVANCED_FACE('F1540',(#2255),#2230,.F.);
#2257=CARTESIAN_POINT('',(69.85,6.35,-19.05));
#2258=DIRECTION('',(0.,-1.,0.));
#2259=DIRECTION('',(0.,0.,-1.));
#2260=AXIS2_PLACEMENT_3D('',#2257,#2258,#2259);
#2261=PLANE('',#2260);
#2262=ORIENTED_EDGE('',*,*,#2215,.T.);
#2263=CARTESIAN_POINT('',(46.0375,6.35,-20.6375));
#2264=DIRECTION('',(0.,-1.,0.));
#2265=DIRECTION('',(0.,0.,-1.));
#2266=AXIS2_PLACEMENT_3D('',#2263,#2264,#2265);
#2267=CIRCLE('',#2266,1.5875);
#2268=EDGE_CURVE('E1155',#2206,#2174,#2267,.F.);
#2269=ORIENTED_EDGE('',*,*,#2268,.T.);
#2270=ORIENTED_EDGE('',*,*,#2177,.T.);
#2271=CARTESIAN_POINT('',(68.2625,6.35,-20.6375));
#2272=DIRECTION('',(0.,-1.,0.));
#2273=DIRECTION('',(0.,0.,-1.));
#2274=AXIS2_PLACEMENT_3D('',#2271,#2272,#2273);
#2275=CIRCLE('',#2274,1.5875);
#2276=EDGE_CURVE('E1153',#2176,#2143,#2275,.F.);
#2277=ORIENTED_EDGE('',*,*,#2276,.T.);
#2278=ORIENTED_EDGE('',*,*,#2146,.T.);
#2279=CARTESIAN_POINT('',(68.2625,6.35,-42.8625));
#2280=DIRECTION('',(0.,-1.,0.));
#2281=DIRECTION('',(0.,0.,-1.));
#2282=AXIS2_PLACEMENT_3D('',#2279,#2280,#2281);
#2283=CIRCLE('',#2282,1.5875);
#2284=EDGE_CURVE('E1151',#2145,#2236,#2283,.F.);
#2285=ORIENTED_EDGE('',*,*,#2284,.T.);
#2286=ORIENTED_EDGE('',*,*,#2239,.T.);
#2287=CARTESIAN_POINT('',(46.0375,6.35,-42.8625));
#2288=DIRECTION('',(0.,-1.,0.));
#2289=DIRECTION('',(0.,0.,-1.));
#2290=AXIS2_PLACEMENT_3D('',#2287,#2288,#2289);
#2291=CIRCLE('',#2290,1.5875);
#2292=EDGE_CURVE('E1149',#2238,#2214,#2291,.F.);
#2293=ORIENTED_EDGE('',*,*,#2292,.T.);
#2294=EDGE_LOOP('',(#2262,#2269,#2270,#2277,#2278,#2285,#2286,#2293));
#2295=FACE_BOUND('',#2294,.T.);
#2296=ADVANCED_FACE('F1536',(#2295),#2261,.F.);
#2297=CARTESIAN_POINT('',(69.85,6.35,19.05));
#2298=DIRECTION('',(1.,0.,0.));
#2299=DIRECTION('',(0.,0.,-1.));
#2300=AXIS2_PLACEMENT_3D('',#2297,#2298,#2299);
#2301=PLANE('',#2300);
#2302=DIRECTION('',(0.,0.,-1.));
#2303=VECTOR('',#2302,1.);
#2304=CARTESIAN_POINT('',(69.85,6.35,19.05));
#2305=LINE('',#2304,#2303);
#2306=CARTESIAN_POINT('',(69.85,6.35,42.8625));
#2307=VERTEX_POINT('',#2306);
#2308=CARTESIAN_POINT('',(69.85,6.35,20.6375));
#2309=VERTEX_POINT('',#2308);
#2310=EDGE_CURVE('E689',#2307,#2309,#2305,.T.);
#2311=ORIENTED_EDGE('',*,*,#2310,.F.);
#2312=DIRECTION('',(0.,1.,0.));
#2313=VECTOR('',#2312,1.);
#2314=CARTESIAN_POINT('',(69.85,12.7,42.8625));
#2315=LINE('',#2314,#2313);
#2316=EDGE_CURVE('E1195',#2307,#623,#2315,.T.);
#2317=ORIENTED_EDGE('',*,*,#2316,.T.);
#2318=ORIENTED_EDGE('',*,*,#626,.T.);
#2319=DIRECTION('',(0.,1.,0.));
#2320=VECTOR('',#2319,1.);
#2321=CARTESIAN_POINT('',(69.85,6.35,20.6375));
#2322=LINE('',#2321,#2320);
#2323=EDGE_CURVE('E1193',#625,#2309,#2322,.F.);
#2324=ORIENTED_EDGE('',*,*,#2323,.T.);
#2325=EDGE_LOOP('',(#2311,#2317,#2318,#2324));
#2326=FACE_BOUND('',#2325,.T.);
#2327=ADVANCED_FACE('F1526',(#2326),#2301,.F.);
#2328=CARTESIAN_POINT('',(69.85,6.35,44.45));
#2329=DIRECTION('',(0.,0.,1.));
#2330=DIRECTION('',(1.,0.,0.));
#2331=AXIS2_PLACEMENT_3D('',#2328,#2329,#2330);
#2332=PLANE('',#2331);
#2333=DIRECTION('',(1.,0.,0.));
#2334=VECTOR('',#2333,1.);
#2335=CARTESIAN_POINT('',(69.85,6.35,44.45));
#2336=LINE('',#2335,#2334);
#2337=CARTESIAN_POINT('',(46.0375,6.35,44.45));
#2338=VERTEX_POINT('',#2337);
#2339=CARTESIAN_POINT('',(68.2625,6.35,44.45));
#2340=VERTEX_POINT('',#2339);
#2341=EDGE_CURVE('E698',#2338,#2340,#2336,.T.);
#2342=ORIENTED_EDGE('',*,*,#2341,.F.);
#2343=DIRECTION('',(0.,1.,0.));
#2344=VECTOR('',#2343,1.);
#2345=CARTESIAN_POINT('',(46.0375,12.7,44.45));
#2346=LINE('',#2345,#2344);
#2347=EDGE_CURVE('E1177',#2338,#642,#2346,.T.);
#2348=ORIENTED_EDGE('',*,*,#2347,.T.);
#2349=ORIENTED_EDGE('',*,*,#643,.T.);
#2350=DIRECTION('',(0.,1.,0.));
#2351=VECTOR('',#2350,1.);
#2352=CARTESIAN_POINT('',(68.2625,6.35,44.45));
#2353=LINE('',#2352,#2351);
#2354=EDGE_CURVE('E1175',#634,#2340,#2353,.F.);
#2355=ORIENTED_EDGE('',*,*,#2354,.T.);
#2356=EDGE_LOOP('',(#2342,#2348,#2349,#2355));
#2357=FACE_BOUND('',#2356,.T.);
#2358=ADVANCED_FACE('F1522',(#2357),#2332,.F.);
#2359=CARTESIAN_POINT('',(44.45,6.35,19.05));
#2360=DIRECTION('',(-1.,0.,0.));
#2361=DIRECTION('',(0.,0.,1.));
#2362=AXIS2_PLACEMENT_3D('',#2359,#2360,#2361);
#2363=PLANE('',#2362);
#2364=ORIENTED_EDGE('',*,*,#660,.T.);
#2365=DIRECTION('',(0.,1.,0.));
#2366=VECTOR('',#2365,1.);
#2367=CARTESIAN_POINT('',(44.45,6.35,42.8625));
#2368=LINE('',#2367,#2366);
#2369=CARTESIAN_POINT('',(44.45,6.35,42.8625));
#2370=VERTEX_POINT('',#2369);
#2371=EDGE_CURVE('E1183',#651,#2370,#2368,.F.);
#2372=ORIENTED_EDGE('',*,*,#2371,.T.);
#2373=DIRECTION('',(0.,0.,1.));
#2374=VECTOR('',#2373,1.);
#2375=CARTESIAN_POINT('',(44.45,6.35,19.05));
#2376=LINE('',#2375,#2374);
#2377=CARTESIAN_POINT('',(44.45,6.35,20.6375));
#2378=VERTEX_POINT('',#2377);
#2379=EDGE_CURVE('E695',#2378,#2370,#2376,.T.);
#2380=ORIENTED_EDGE('',*,*,#2379,.F.);
#2381=DIRECTION('',(0.,1.,0.));
#2382=VECTOR('',#2381,1.);
#2383=CARTESIAN_POINT('',(44.45,12.7,20.6375));
#2384=LINE('',#2383,#2382);
#2385=EDGE_CURVE('E1180',#2378,#659,#2384,.T.);
#2386=ORIENTED_EDGE('',*,*,#2385,.T.);
#2387=EDGE_LOOP('',(#2364,#2372,#2380,#2386));
#2388=FACE_BOUND('',#2387,.T.);
#2389=ADVANCED_FACE('F1525',(#2388),#2363,.F.);
#2390=CARTESIAN_POINT('',(69.85,6.35,19.05));
#2391=DIRECTION('',(0.,0.,-1.));
#2392=DIRECTION('',(-1.,0.,0.));
#2393=AXIS2_PLACEMENT_3D('',#2390,#2391,#2392);
#2394=PLANE('',#2393);
#2395=DIRECTION('',(-1.,0.,0.));
#2396=VECTOR('',#2395,1.);
#2397=CARTESIAN_POINT('',(69.85,6.35,19.05));
#2398=LINE('',#2397,#2396);
#2399=CARTESIAN_POINT('',(68.2625,6.35,19.05));
#2400=VERTEX_POINT('',#2399);
#2401=CARTESIAN_POINT('',(46.0375,6.35,19.05));
#2402=VERTEX_POINT('',#2401);
#2403=EDGE_CURVE('E692',#2400,#2402,#2398,.T.);
#2404=ORIENTED_EDGE('',*,*,#2403,.F.);
#2405=DIRECTION('',(0.,1.,0.));
#2406=VECTOR('',#2405,1.);
#2407=CARTESIAN_POINT('',(68.2625,12.7,19.05));
#2408=LINE('',#2407,#2406);
#2409=EDGE_CURVE('E1200',#2400,#676,#2408,.T.);
#2410=ORIENTED_EDGE('',*,*,#2409,.T.);
#2411=ORIENTED_EDGE('',*,*,#677,.T.);
#2412=DIRECTION('',(0.,1.,0.));
#2413=VECTOR('',#2412,1.);
#2414=CARTESIAN_POINT('',(46.0375,6.35,19.05));
#2415=LINE('',#2414,#2413);
#2416=EDGE_CURVE('E1198',#668,#2402,#2415,.F.);
#2417=ORIENTED_EDGE('',*,*,#2416,.T.);
#2418=EDGE_LOOP('',(#2404,#2410,#2411,#2417));
#2419=FACE_BOUND('',#2418,.T.);
#2420=ADVANCED_FACE('F1520',(#2419),#2394,.F.);
#2421=CARTESIAN_POINT('',(69.85,6.35,44.45));
#2422=DIRECTION('',(0.,-1.,0.));
#2423=DIRECTION('',(0.,0.,-1.));
#2424=AXIS2_PLACEMENT_3D('',#2421,#2422,#2423);
#2425=PLANE('',#2424);
#2426=ORIENTED_EDGE('',*,*,#2379,.T.);
#2427=CARTESIAN_POINT('',(46.0375,6.35,42.8625));
#2428=DIRECTION('',(0.,-1.,0.));
#2429=DIRECTION('',(0.,0.,-1.));
#2430=AXIS2_PLACEMENT_3D('',#2427,#2428,#2429);
#2431=CIRCLE('',#2430,1.5875);
#2432=EDGE_CURVE('E1191',#2370,#2338,#2431,.F.);
#2433=ORIENTED_EDGE('',*,*,#2432,.T.);
#2434=ORIENTED_EDGE('',*,*,#2341,.T.);
#2435=CARTESIAN_POINT('',(68.2625,6.35,42.8625));
#2436=DIRECTION('',(0.,-1.,0.));
#2437=DIRECTION('',(0.,0.,-1.));
#2438=AXIS2_PLACEMENT_3D('',#2435,#2436,#2437);
#2439=CIRCLE('',#2438,1.5875);
#2440=EDGE_CURVE('E1189',#2340,#2307,#2439,.F.);
#2441=ORIENTED_EDGE('',*,*,#2440,.T.);
#2442=ORIENTED_EDGE('',*,*,#2310,.T.);
#2443=CARTESIAN_POINT('',(68.2625,6.35,20.6375));
#2444=DIRECTION('',(0.,-1.,0.));
#2445=DIRECTION('',(0.,0.,-1.));
#2446=AXIS2_PLACEMENT_3D('',#2443,#2444,#2445);
#2447=CIRCLE('',#2446,1.5875);
#2448=EDGE_CURVE('E1187',#2309,#2400,#2447,.F.);
#2449=ORIENTED_EDGE('',*,*,#2448,.T.);
#2450=ORIENTED_EDGE('',*,*,#2403,.T.);
#2451=CARTESIAN_POINT('',(46.0375,6.35,20.6375));
#2452=DIRECTION('',(0.,-1.,0.));
#2453=DIRECTION('',(0.,0.,-1.));
#2454=AXIS2_PLACEMENT_3D('',#2451,#2452,#2453);
#2455=CIRCLE('',#2454,1.5875);
#2456=EDGE_CURVE('E1185',#2402,#2378,#2455,.F.);
#2457=ORIENTED_EDGE('',*,*,#2456,.T.);
#2458=EDGE_LOOP('',(#2426,#2433,#2434,#2441,#2442,#2449,#2450,#2457));
#2459=FACE_BOUND('',#2458,.T.);
#2460=ADVANCED_FACE('F1516',(#2459),#2425,.F.);
#2461=CARTESIAN_POINT('',(-68.2625,6.35,42.8625));
#2462=DIRECTION('',(0.,-1.,0.));
#2463=DIRECTION('',(0.,0.,-1.));
#2464=AXIS2_PLACEMENT_3D('',#2461,#2462,#2463);
#2465=CYLINDRICAL_SURFACE('',#2464,1.5875);
#2466=ORIENTED_EDGE('',*,*,#1448,.F.);
#2467=ORIENTED_EDGE('',*,*,#1387,.F.);
#2468=ORIENTED_EDGE('',*,*,#232,.F.);
#2469=ORIENTED_EDGE('',*,*,#1363,.F.);
#2470=EDGE_LOOP('',(#2466,#2467,#2468,#2469));
#2471=FACE_BOUND('',#2470,.T.);
#2472=ADVANCED_FACE('F1512',(#2471),#2465,.F.);
#2473=CARTESIAN_POINT('',(-46.0375,6.35,42.8625));
#2474=DIRECTION('',(0.,-1.,0.));
#2475=DIRECTION('',(0.,0.,-1.));
#2476=AXIS2_PLACEMENT_3D('',#2473,#2474,#2475);
#2477=CYLINDRICAL_SURFACE('',#2476,1.5875);
#2478=ORIENTED_EDGE('',*,*,#1456,.F.);
#2479=ORIENTED_EDGE('',*,*,#1370,.F.);
#2480=ORIENTED_EDGE('',*,*,#215,.F.);
#2481=ORIENTED_EDGE('',*,*,#1332,.F.);
#2482=EDGE_LOOP('',(#2478,#2479,#2480,#2481));
#2483=FACE_BOUND('',#2482,.T.);
#2484=ADVANCED_FACE('F1508',(#2483),#2477,.F.);
#2485=CARTESIAN_POINT('',(-46.0375,6.35,20.6375));
#2486=DIRECTION('',(0.,-1.,0.));
#2487=DIRECTION('',(0.,0.,-1.));
#2488=AXIS2_PLACEMENT_3D('',#2485,#2486,#2487);
#2489=CYLINDRICAL_SURFACE('',#2488,1.5875);
#2490=ORIENTED_EDGE('',*,*,#1464,.F.);
#2491=ORIENTED_EDGE('',*,*,#1339,.F.);
#2492=ORIENTED_EDGE('',*,*,#264,.F.);
#2493=ORIENTED_EDGE('',*,*,#1425,.F.);
#2494=EDGE_LOOP('',(#2490,#2491,#2492,#2493));
#2495=FACE_BOUND('',#2494,.T.);
#2496=ADVANCED_FACE('F1504',(#2495),#2489,.F.);
#2497=CARTESIAN_POINT('',(-68.2625,6.35,20.6375));
#2498=DIRECTION('',(0.,-1.,0.));
#2499=DIRECTION('',(0.,0.,-1.));
#2500=AXIS2_PLACEMENT_3D('',#2497,#2498,#2499);
#2501=CYLINDRICAL_SURFACE('',#2500,1.5875);
#2502=ORIENTED_EDGE('',*,*,#1472,.F.);
#2503=ORIENTED_EDGE('',*,*,#1432,.F.);
#2504=ORIENTED_EDGE('',*,*,#249,.F.);
#2505=ORIENTED_EDGE('',*,*,#1401,.F.);
#2506=EDGE_LOOP('',(#2502,#2503,#2504,#2505));
#2507=FACE_BOUND('',#2506,.T.);
#2508=ADVANCED_FACE('F1500',(#2507),#2501,.F.);
#2509=CARTESIAN_POINT('',(-30.1625,6.35,-20.6375));
#2510=DIRECTION('',(0.,-1.,0.));
#2511=DIRECTION('',(0.,0.,-1.));
#2512=AXIS2_PLACEMENT_3D('',#2509,#2510,#2511);
#2513=CYLINDRICAL_SURFACE('',#2512,1.5875);
#2514=ORIENTED_EDGE('',*,*,#1612,.F.);
#2515=ORIENTED_EDGE('',*,*,#1551,.F.);
#2516=ORIENTED_EDGE('',*,*,#302,.F.);
#2517=ORIENTED_EDGE('',*,*,#1527,.F.);
#2518=EDGE_LOOP('',(#2514,#2515,#2516,#2517));
#2519=FACE_BOUND('',#2518,.T.);
#2520=ADVANCED_FACE('F1496',(#2519),#2513,.F.);
#2521=CARTESIAN_POINT('',(-7.93749999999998,6.35,-20.6375));
#2522=DIRECTION('',(0.,-1.,0.));
#2523=DIRECTION('',(0.,0.,-1.));
#2524=AXIS2_PLACEMENT_3D('',#2521,#2522,#2523);
#2525=CYLINDRICAL_SURFACE('',#2524,1.5875);
#2526=ORIENTED_EDGE('',*,*,#1620,.F.);
#2527=ORIENTED_EDGE('',*,*,#1534,.F.);
#2528=ORIENTED_EDGE('',*,*,#285,.F.);
#2529=ORIENTED_EDGE('',*,*,#1496,.F.);
#2530=EDGE_LOOP('',(#2526,#2527,#2528,#2529));
#2531=FACE_BOUND('',#2530,.T.);
#2532=ADVANCED_FACE('F1492',(#2531),#2525,.F.);
#2533=CARTESIAN_POINT('',(-7.93749999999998,6.35,-42.8625));
#2534=DIRECTION('',(0.,-1.,0.));
#2535=DIRECTION('',(0.,0.,-1.));
#2536=AXIS2_PLACEMENT_3D('',#2533,#2534,#2535);
#2537=CYLINDRICAL_SURFACE('',#2536,1.5875);
#2538=ORIENTED_EDGE('',*,*,#1628,.F.);
#2539=ORIENTED_EDGE('',*,*,#1503,.F.);
#2540=ORIENTED_EDGE('',*,*,#334,.F.);
#2541=ORIENTED_EDGE('',*,*,#1589,.F.);
#2542=EDGE_LOOP('',(#2538,#2539,#2540,#2541));
#2543=FACE_BOUND('',#2542,.T.);
#2544=ADVANCED_FACE('F1488',(#2543),#2537,.F.);
#2545=CARTESIAN_POINT('',(-30.1625,6.35,-42.8625));
#2546=DIRECTION('',(0.,-1.,0.));
#2547=DIRECTION('',(0.,0.,-1.));
#2548=AXIS2_PLACEMENT_3D('',#2545,#2546,#2547);
#2549=CYLINDRICAL_SURFACE('',#2548,1.5875);
#2550=ORIENTED_EDGE('',*,*,#1636,.F.);
#2551=ORIENTED_EDGE('',*,*,#1596,.F.);
#2552=ORIENTED_EDGE('',*,*,#319,.F.);
#2553=ORIENTED_EDGE('',*,*,#1565,.F.);
#2554=EDGE_LOOP('',(#2550,#2551,#2552,#2553));
#2555=FACE_BOUND('',#2554,.T.);
#2556=ADVANCED_FACE('F1484',(#2555),#2549,.F.);
#2557=CARTESIAN_POINT('',(-30.1625,6.35,42.8625));
#2558=DIRECTION('',(0.,-1.,0.));
#2559=DIRECTION('',(0.,0.,-1.));
#2560=AXIS2_PLACEMENT_3D('',#2557,#2558,#2559);
#2561=CYLINDRICAL_SURFACE('',#2560,1.5875);
#2562=ORIENTED_EDGE('',*,*,#1776,.F.);
#2563=ORIENTED_EDGE('',*,*,#1715,.F.);
#2564=ORIENTED_EDGE('',*,*,#372,.F.);
#2565=ORIENTED_EDGE('',*,*,#1691,.F.);
#2566=EDGE_LOOP('',(#2562,#2563,#2564,#2565));
#2567=FACE_BOUND('',#2566,.T.);
#2568=ADVANCED_FACE('F1480',(#2567),#2561,.F.);
#2569=CARTESIAN_POINT('',(-7.93749999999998,6.35,42.8625));
#2570=DIRECTION('',(0.,-1.,0.));
#2571=DIRECTION('',(0.,0.,-1.));
#2572=AXIS2_PLACEMENT_3D('',#2569,#2570,#2571);
#2573=CYLINDRICAL_SURFACE('',#2572,1.5875);
#2574=ORIENTED_EDGE('',*,*,#1784,.F.);
#2575=ORIENTED_EDGE('',*,*,#1698,.F.);
#2576=ORIENTED_EDGE('',*,*,#355,.F.);
#2577=ORIENTED_EDGE('',*,*,#1660,.F.);
#2578=EDGE_LOOP('',(#2574,#2575,#2576,#2577));
#2579=FACE_BOUND('',#2578,.T.);
#2580=ADVANCED_FACE('F1476',(#2579),#2573,.F.);
#2581=CARTESIAN_POINT('',(-7.93749999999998,6.35,20.6375));
#2582=DIRECTION('',(0.,-1.,0.));
#2583=DIRECTION('',(0.,0.,-1.));
#2584=AXIS2_PLACEMENT_3D('',#2581,#2582,#2583);
#2585=CYLINDRICAL_SURFACE('',#2584,1.5875);
#2586=ORIENTED_EDGE('',*,*,#1792,.F.);
#2587=ORIENTED_EDGE('',*,*,#1667,.F.);
#2588=ORIENTED_EDGE('',*,*,#404,.F.);
#2589=ORIENTED_EDGE('',*,*,#1753,.F.);
#2590=EDGE_LOOP('',(#2586,#2587,#2588,#2589));
#2591=FACE_BOUND('',#2590,.T.);
#2592=ADVANCED_FACE('F1472',(#2591),#2585,.F.);
#2593=CARTESIAN_POINT('',(-30.1625,6.35,20.6375));
#2594=DIRECTION('',(0.,-1.,0.));
#2595=DIRECTION('',(0.,0.,-1.));
#2596=AXIS2_PLACEMENT_3D('',#2593,#2594,#2595);
#2597=CYLINDRICAL_SURFACE('',#2596,1.5875);
#2598=ORIENTED_EDGE('',*,*,#1800,.F.);
#2599=ORIENTED_EDGE('',*,*,#1760,.F.);
#2600=ORIENTED_EDGE('',*,*,#389,.F.);
#2601=ORIENTED_EDGE('',*,*,#1729,.F.);
#2602=EDGE_LOOP('',(#2598,#2599,#2600,#2601));
#2603=FACE_BOUND('',#2602,.T.);
#2604=ADVANCED_FACE('F1468',(#2603),#2597,.F.);
#2605=CARTESIAN_POINT('',(7.93750000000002,6.35,-20.6375));
#2606=DIRECTION('',(0.,-1.,0.));
#2607=DIRECTION('',(0.,0.,-1.));
#2608=AXIS2_PLACEMENT_3D('',#2605,#2606,#2607);
#2609=CYLINDRICAL_SURFACE('',#2608,1.5875);
#2610=ORIENTED_EDGE('',*,*,#1940,.F.);
#2611=ORIENTED_EDGE('',*,*,#1879,.F.);
#2612=ORIENTED_EDGE('',*,*,#442,.F.);
#2613=ORIENTED_EDGE('',*,*,#1855,.F.);
#2614=EDGE_LOOP('',(#2610,#2611,#2612,#2613));
#2615=FACE_BOUND('',#2614,.T.);
#2616=ADVANCED_FACE('F1464',(#2615),#2609,.F.);
#2617=CARTESIAN_POINT('',(30.1625,6.35,-20.6375));
#2618=DIRECTION('',(0.,-1.,0.));
#2619=DIRECTION('',(0.,0.,-1.));
#2620=AXIS2_PLACEMENT_3D('',#2617,#2618,#2619);
#2621=CYLINDRICAL_SURFACE('',#2620,1.5875);
#2622=ORIENTED_EDGE('',*,*,#1948,.F.);
#2623=ORIENTED_EDGE('',*,*,#1862,.F.);
#2624=ORIENTED_EDGE('',*,*,#425,.F.);
#2625=ORIENTED_EDGE('',*,*,#1824,.F.);
#2626=EDGE_LOOP('',(#2622,#2623,#2624,#2625));
#2627=FACE_BOUND('',#2626,.T.);
#2628=ADVANCED_FACE('F1460',(#2627),#2621,.F.);
#2629=CARTESIAN_POINT('',(30.1625,6.35,-42.8625));
#2630=DIRECTION('',(0.,-1.,0.));
#2631=DIRECTION('',(0.,0.,-1.));
#2632=AXIS2_PLACEMENT_3D('',#2629,#2630,#2631);
#2633=CYLINDRICAL_SURFACE('',#2632,1.5875);
#2634=ORIENTED_EDGE('',*,*,#1956,.F.);
#2635=ORIENTED_EDGE('',*,*,#1831,.F.);
#2636=ORIENTED_EDGE('',*,*,#474,.F.);
#2637=ORIENTED_EDGE('',*,*,#1917,.F.);
#2638=EDGE_LOOP('',(#2634,#2635,#2636,#2637));
#2639=FACE_BOUND('',#2638,.T.);
#2640=ADVANCED_FACE('F1456',(#2639),#2633,.F.);
#2641=CARTESIAN_POINT('',(7.93750000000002,6.35,-42.8625));
#2642=DIRECTION('',(0.,-1.,0.));
#2643=DIRECTION('',(0.,0.,-1.));
#2644=AXIS2_PLACEMENT_3D('',#2641,#2642,#2643);
#2645=CYLINDRICAL_SURFACE('',#2644,1.5875);
#2646=ORIENTED_EDGE('',*,*,#1964,.F.);
#2647=ORIENTED_EDGE('',*,*,#1924,.F.);
#2648=ORIENTED_EDGE('',*,*,#459,.F.);
#2649=ORIENTED_EDGE('',*,*,#1893,.F.);
#2650=EDGE_LOOP('',(#2646,#2647,#2648,#2649));
#2651=FACE_BOUND('',#2650,.T.);
#2652=ADVANCED_FACE('F1452',(#2651),#2645,.F.);
#2653=CARTESIAN_POINT('',(7.93750000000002,6.35,42.8625));
#2654=DIRECTION('',(0.,-1.,0.));
#2655=DIRECTION('',(0.,0.,-1.));
#2656=AXIS2_PLACEMENT_3D('',#2653,#2654,#2655);
#2657=CYLINDRICAL_SURFACE('',#2656,1.5875);
#2658=ORIENTED_EDGE('',*,*,#2104,.F.);
#2659=ORIENTED_EDGE('',*,*,#2043,.F.);
#2660=ORIENTED_EDGE('',*,*,#512,.F.);
#2661=ORIENTED_EDGE('',*,*,#2019,.F.);
#2662=EDGE_LOOP('',(#2658,#2659,#2660,#2661));
#2663=FACE_BOUND('',#2662,.T.);
#2664=ADVANCED_FACE('F1448',(#2663),#2657,.F.);
#2665=CARTESIAN_POINT('',(30.1625,6.35,42.8625));
#2666=DIRECTION('',(0.,-1.,0.));
#2667=DIRECTION('',(0.,0.,-1.));
#2668=AXIS2_PLACEMENT_3D('',#2665,#2666,#2667);
#2669=CYLINDRICAL_SURFACE('',#2668,1.5875);
#2670=ORIENTED_EDGE('',*,*,#2112,.F.);
#2671=ORIENTED_EDGE('',*,*,#2026,.F.);
#2672=ORIENTED_EDGE('',*,*,#495,.F.);
#2673=ORIENTED_EDGE('',*,*,#1988,.F.);
#2674=EDGE_LOOP('',(#2670,#2671,#2672,#2673));
#2675=FACE_BOUND('',#2674,.T.);
#2676=ADVANCED_FACE('F1444',(#2675),#2669,.F.);
#2677=CARTESIAN_POINT('',(30.1625,6.35,20.6375));
#2678=DIRECTION('',(0.,-1.,0.));
#2679=DIRECTION('',(0.,0.,-1.));
#2680=AXIS2_PLACEMENT_3D('',#2677,#2678,#2679);
#2681=CYLINDRICAL_SURFACE('',#2680,1.5875);
#2682=ORIENTED_EDGE('',*,*,#2120,.F.);
#2683=ORIENTED_EDGE('',*,*,#1995,.F.);
#2684=ORIENTED_EDGE('',*,*,#544,.F.);
#2685=ORIENTED_EDGE('',*,*,#2081,.F.);
#2686=EDGE_LOOP('',(#2682,#2683,#2684,#2685));
#2687=FACE_BOUND('',#2686,.T.);
#2688=ADVANCED_FACE('F1440',(#2687),#2681,.F.);
#2689=CARTESIAN_POINT('',(7.93750000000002,6.35,20.6375));
#2690=DIRECTION('',(0.,-1.,0.));
#2691=DIRECTION('',(0.,0.,-1.));
#2692=AXIS2_PLACEMENT_3D('',#2689,#2690,#2691);
#2693=CYLINDRICAL_SURFACE('',#2692,1.5875);
#2694=ORIENTED_EDGE('',*,*,#2128,.F.);
#2695=ORIENTED_EDGE('',*,*,#2088,.F.);
#2696=ORIENTED_EDGE('',*,*,#529,.F.);
#2697=ORIENTED_EDGE('',*,*,#2057,.F.);
#2698=EDGE_LOOP('',(#2694,#2695,#2696,#2697));
#2699=FACE_BOUND('',#2698,.T.);
#2700=ADVANCED_FACE('F1436',(#2699),#2693,.F.);
#2701=CARTESIAN_POINT('',(46.0375,6.35,-20.6375));
#2702=DIRECTION('',(0.,-1.,0.));
#2703=DIRECTION('',(0.,0.,-1.));
#2704=AXIS2_PLACEMENT_3D('',#2701,#2702,#2703);
#2705=CYLINDRICAL_SURFACE('',#2704,1.5875);
#2706=ORIENTED_EDGE('',*,*,#2268,.F.);
#2707=ORIENTED_EDGE('',*,*,#2207,.F.);
#2708=ORIENTED_EDGE('',*,*,#582,.F.);
#2709=ORIENTED_EDGE('',*,*,#2183,.F.);
#2710=EDGE_LOOP('',(#2706,#2707,#2708,#2709));
#2711=FACE_BOUND('',#2710,.T.);
#2712=ADVANCED_FACE('F1432',(#2711),#2705,.F.);
#2713=CARTESIAN_POINT('',(68.2625,6.35,-20.6375));
#2714=DIRECTION('',(0.,-1.,0.));
#2715=DIRECTION('',(0.,0.,-1.));
#2716=AXIS2_PLACEMENT_3D('',#2713,#2714,#2715);
#2717=CYLINDRICAL_SURFACE('',#2716,1.5875);
#2718=ORIENTED_EDGE('',*,*,#2276,.F.);
#2719=ORIENTED_EDGE('',*,*,#2190,.F.);
#2720=ORIENTED_EDGE('',*,*,#565,.F.);
#2721=ORIENTED_EDGE('',*,*,#2152,.F.);
#2722=EDGE_LOOP('',(#2718,#2719,#2720,#2721));
#2723=FACE_BOUND('',#2722,.T.);
#2724=ADVANCED_FACE('F1428',(#2723),#2717,.F.);
#2725=CARTESIAN_POINT('',(68.2625,6.35,-42.8625));
#2726=DIRECTION('',(0.,-1.,0.));
#2727=DIRECTION('',(0.,0.,-1.));
#2728=AXIS2_PLACEMENT_3D('',#2725,#2726,#2727);
#2729=CYLINDRICAL_SURFACE('',#2728,1.5875);
#2730=ORIENTED_EDGE('',*,*,#2284,.F.);
#2731=ORIENTED_EDGE('',*,*,#2159,.F.);
#2732=ORIENTED_EDGE('',*,*,#614,.F.);
#2733=ORIENTED_EDGE('',*,*,#2245,.F.);
#2734=EDGE_LOOP('',(#2730,#2731,#2732,#2733));
#2735=FACE_BOUND('',#2734,.T.);
#2736=ADVANCED_FACE('F1424',(#2735),#2729,.F.);
#2737=CARTESIAN_POINT('',(46.0375,6.35,-42.8625));
#2738=DIRECTION('',(0.,-1.,0.));
#2739=DIRECTION('',(0.,0.,-1.));
#2740=AXIS2_PLACEMENT_3D('',#2737,#2738,#2739);
#2741=CYLINDRICAL_SURFACE('',#2740,1.5875);
#2742=ORIENTED_EDGE('',*,*,#2292,.F.);
#2743=ORIENTED_EDGE('',*,*,#2252,.F.);
#2744=ORIENTED_EDGE('',*,*,#599,.F.);
#2745=ORIENTED_EDGE('',*,*,#2221,.F.);
#2746=EDGE_LOOP('',(#2742,#2743,#2744,#2745));
#2747=FACE_BOUND('',#2746,.T.);
#2748=ADVANCED_FACE('F1420',(#2747),#2741,.F.);
#2749=CARTESIAN_POINT('',(46.0375,6.35,42.8625));
#2750=DIRECTION('',(0.,-1.,0.));
#2751=DIRECTION('',(0.,0.,-1.));
#2752=AXIS2_PLACEMENT_3D('',#2749,#2750,#2751);
#2753=CYLINDRICAL_SURFACE('',#2752,1.5875);
#2754=ORIENTED_EDGE('',*,*,#2432,.F.);
#2755=ORIENTED_EDGE('',*,*,#2371,.F.);
#2756=ORIENTED_EDGE('',*,*,#652,.F.);
#2757=ORIENTED_EDGE('',*,*,#2347,.F.);
#2758=EDGE_LOOP('',(#2754,#2755,#2756,#2757));
#2759=FACE_BOUND('',#2758,.T.);
#2760=ADVANCED_FACE('F1416',(#2759),#2753,.F.);
#2761=CARTESIAN_POINT('',(68.2625,6.35,42.8625));
#2762=DIRECTION('',(0.,-1.,0.));
#2763=DIRECTION('',(0.,0.,-1.));
#2764=AXIS2_PLACEMENT_3D('',#2761,#2762,#2763);
#2765=CYLINDRICAL_SURFACE('',#2764,1.5875);
#2766=ORIENTED_EDGE('',*,*,#2440,.F.);
#2767=ORIENTED_EDGE('',*,*,#2354,.F.);
#2768=ORIENTED_EDGE('',*,*,#635,.F.);
#2769=ORIENTED_EDGE('',*,*,#2316,.F.);
#2770=EDGE_LOOP('',(#2766,#2767,#2768,#2769));
#2771=FACE_BOUND('',#2770,.T.);
#2772=ADVANCED_FACE('F1412',(#2771),#2765,.F.);
#2773=CARTESIAN_POINT('',(68.2625,6.35,20.6375));
#2774=DIRECTION('',(0.,-1.,0.));
#2775=DIRECTION('',(0.,0.,-1.));
#2776=AXIS2_PLACEMENT_3D('',#2773,#2774,#2775);
#2777=CYLINDRICAL_SURFACE('',#2776,1.5875);
#2778=ORIENTED_EDGE('',*,*,#2448,.F.);
#2779=ORIENTED_EDGE('',*,*,#2323,.F.);
#2780=ORIENTED_EDGE('',*,*,#684,.F.);
#2781=ORIENTED_EDGE('',*,*,#2409,.F.);
#2782=EDGE_LOOP('',(#2778,#2779,#2780,#2781));
#2783=FACE_BOUND('',#2782,.T.);
#2784=ADVANCED_FACE('F1408',(#2783),#2777,.F.);
#2785=CARTESIAN_POINT('',(46.0375,6.35,20.6375));
#2786=DIRECTION('',(0.,-1.,0.));
#2787=DIRECTION('',(0.,0.,-1.));
#2788=AXIS2_PLACEMENT_3D('',#2785,#2786,#2787);
#2789=CYLINDRICAL_SURFACE('',#2788,1.5875);
#2790=ORIENTED_EDGE('',*,*,#2456,.F.);
#2791=ORIENTED_EDGE('',*,*,#2416,.F.);
#2792=ORIENTED_EDGE('',*,*,#669,.F.);
#2793=ORIENTED_EDGE('',*,*,#2385,.F.);
#2794=EDGE_LOOP('',(#2790,#2791,#2792,#2793));
#2795=FACE_BOUND('',#2794,.T.);
#2796=ADVANCED_FACE('F1404',(#2795),#2789,.F.);
#2797=CARTESIAN_POINT('',(-26.9875,6.35,-11.1125));
#2798=DIRECTION('',(0.,-1.,0.));
#2799=DIRECTION('',(0.,0.,-1.));
#2800=AXIS2_PLACEMENT_3D('',#2797,#2798,#2799);
#2801=CYLINDRICAL_SURFACE('',#2800,1.5875);
#2802=ORIENTED_EDGE('',*,*,#1236,.F.);
#2803=ORIENTED_EDGE('',*,*,#1113,.F.);
#2804=ORIENTED_EDGE('',*,*,#194,.F.);
#2805=ORIENTED_EDGE('',*,*,#1213,.F.);
#2806=EDGE_LOOP('',(#2802,#2803,#2804,#2805));
#2807=FACE_BOUND('',#2806,.T.);
#2808=ADVANCED_FACE('F1400',(#2807),#2801,.F.);
#2809=CARTESIAN_POINT('',(-26.9875,6.35,11.1125));
#2810=DIRECTION('',(0.,-1.,0.));
#2811=DIRECTION('',(0.,0.,-1.));
#2812=AXIS2_PLACEMENT_3D('',#2809,#2810,#2811);
#2813=CYLINDRICAL_SURFACE('',#2812,1.5875);
#2814=ORIENTED_EDGE('',*,*,#1260,.F.);
#2815=ORIENTED_EDGE('',*,*,#1144,.F.);
#2816=ORIENTED_EDGE('',*,*,#145,.F.);
#2817=ORIENTED_EDGE('',*,*,#1127,.F.);
#2818=EDGE_LOOP('',(#2814,#2815,#2816,#2817));
#2819=FACE_BOUND('',#2818,.T.);
#2820=ADVANCED_FACE('F1396',(#2819),#2813,.F.);
#2821=CARTESIAN_POINT('',(-49.2125,6.35,11.1125));
#2822=DIRECTION('',(0.,-1.,0.));
#2823=DIRECTION('',(0.,0.,-1.));
#2824=AXIS2_PLACEMENT_3D('',#2821,#2822,#2823);
#2825=CYLINDRICAL_SURFACE('',#2824,1.5875);
#2826=ORIENTED_EDGE('',*,*,#1252,.F.);
#2827=ORIENTED_EDGE('',*,*,#1175,.F.);
#2828=ORIENTED_EDGE('',*,*,#162,.F.);
#2829=ORIENTED_EDGE('',*,*,#1158,.F.);
#2830=EDGE_LOOP('',(#2826,#2827,#2828,#2829));
#2831=FACE_BOUND('',#2830,.T.);
#2832=ADVANCED_FACE('F1389',(#2831),#2825,.F.);
#2833=CARTESIAN_POINT('',(-49.2125,6.35,-11.1125));
#2834=DIRECTION('',(0.,-1.,0.));
#2835=DIRECTION('',(0.,0.,-1.));
#2836=AXIS2_PLACEMENT_3D('',#2833,#2834,#2835);
#2837=CYLINDRICAL_SURFACE('',#2836,1.5875);
#2838=ORIENTED_EDGE('',*,*,#1244,.F.);
#2839=ORIENTED_EDGE('',*,*,#1220,.F.);
#2840=ORIENTED_EDGE('',*,*,#179,.F.);
#2841=ORIENTED_EDGE('',*,*,#1189,.F.);
#2842=EDGE_LOOP('',(#2838,#2839,#2840,#2841));
#2843=FACE_BOUND('',#2842,.T.);
#2844=ADVANCED_FACE('F1378',(#2843),#2837,.F.);
#2845=CARTESIAN_POINT('',(12.7,6.35,-12.7));
#2846=DIRECTION('',(0.,0.,-1.));
#2847=DIRECTION('',(-1.,0.,0.));
#2848=AXIS2_PLACEMENT_3D('',#2845,#2846,#2847);
#2849=PLANE('',#2848);
#2850=DIRECTION('',(-1.,0.,0.));
#2851=VECTOR('',#2850,1.);
#2852=CARTESIAN_POINT('',(12.7,6.35,-12.7));
#2853=LINE('',#2852,#2851);
#2854=CARTESIAN_POINT('',(11.1125,6.35,-12.7));
#2855=VERTEX_POINT('',#2854);
#2856=CARTESIAN_POINT('',(-11.1125,6.35,-12.7));
#2857=VERTEX_POINT('',#2856);
#2858=EDGE_CURVE('E621',#2855,#2857,#2853,.T.);
#2859=ORIENTED_EDGE('',*,*,#2858,.F.);
#2860=DIRECTION('',(0.,1.,0.));
#2861=VECTOR('',#2860,1.);
#2862=CARTESIAN_POINT('',(11.1125,12.7,-12.7));
#2863=LINE('',#2862,#2861);
#2864=EDGE_CURVE('E674',#2855,#729,#2863,.T.);
#2865=ORIENTED_EDGE('',*,*,#2864,.T.);
#2866=ORIENTED_EDGE('',*,*,#730,.T.);
#2867=DIRECTION('',(0.,1.,0.));
#2868=VECTOR('',#2867,1.);
#2869=CARTESIAN_POINT('',(-11.1125,6.35,-12.7));
#2870=LINE('',#2869,#2868);
#2871=EDGE_CURVE('E608',#721,#2857,#2870,.F.);
#2872=ORIENTED_EDGE('',*,*,#2871,.T.);
#2873=EDGE_LOOP('',(#2859,#2865,#2866,#2872));
#2874=FACE_BOUND('',#2873,.T.);
#2875=ADVANCED_FACE('F619',(#2874),#2849,.F.);
#2876=CARTESIAN_POINT('',(11.1125,6.35,-11.1125));
#2877=DIRECTION('',(0.,-1.,0.));
#2878=DIRECTION('',(0.,0.,-1.));
#2879=AXIS2_PLACEMENT_3D('',#2876,#2877,#2878);
#2880=CYLINDRICAL_SURFACE('',#2879,1.5875);
#2881=CARTESIAN_POINT('',(11.1125,6.35,-11.1125));
#2882=DIRECTION('',(0.,-1.,0.));
#2883=DIRECTION('',(0.,0.,-1.));
#2884=AXIS2_PLACEMENT_3D('',#2881,#2882,#2883);
#2885=CIRCLE('',#2884,1.5875);
#2886=CARTESIAN_POINT('',(12.7,6.35,-11.1125));
#2887=VERTEX_POINT('',#2886);
#2888=EDGE_CURVE('E628',#2887,#2855,#2885,.F.);
#2889=ORIENTED_EDGE('',*,*,#2888,.F.);
#2890=DIRECTION('',(0.,1.,0.));
#2891=VECTOR('',#2890,1.);
#2892=CARTESIAN_POINT('',(12.7,6.35,-11.1125));
#2893=LINE('',#2892,#2891);
#2894=EDGE_CURVE('E668',#738,#2887,#2893,.F.);
#2895=ORIENTED_EDGE('',*,*,#2894,.F.);
#2896=ORIENTED_EDGE('',*,*,#739,.F.);
#2897=ORIENTED_EDGE('',*,*,#2864,.F.);
#2898=EDGE_LOOP('',(#2889,#2895,#2896,#2897));
#2899=FACE_BOUND('',#2898,.T.);
#2900=ADVANCED_FACE('F1380',(#2899),#2880,.F.);
#2901=CARTESIAN_POINT('',(12.7,6.35,-12.7));
#2902=DIRECTION('',(1.,0.,0.));
#2903=DIRECTION('',(0.,0.,-1.));
#2904=AXIS2_PLACEMENT_3D('',#2901,#2902,#2903);
#2905=PLANE('',#2904);
#2906=ORIENTED_EDGE('',*,*,#747,.T.);
#2907=ORIENTED_EDGE('',*,*,#2894,.T.);
#2908=DIRECTION('',(0.,0.,-1.));
#2909=VECTOR('',#2908,1.);
#2910=CARTESIAN_POINT('',(12.7,6.35,-12.7));
#2911=LINE('',#2910,#2909);
#2912=CARTESIAN_POINT('',(12.7,6.35,11.1125));
#2913=VERTEX_POINT('',#2912);
#2914=EDGE_CURVE('E633',#2913,#2887,#2911,.T.);
#2915=ORIENTED_EDGE('',*,*,#2914,.F.);
#2916=DIRECTION('',(0.,1.,0.));
#2917=VECTOR('',#2916,1.);
#2918=CARTESIAN_POINT('',(12.7,12.7,11.1125));
#2919=LINE('',#2918,#2917);
#2920=EDGE_CURVE('E663',#2913,#746,#2919,.T.);
#2921=ORIENTED_EDGE('',*,*,#2920,.T.);
#2922=EDGE_LOOP('',(#2906,#2907,#2915,#2921));
#2923=FACE_BOUND('',#2922,.T.);
#2924=ADVANCED_FACE('F1386',(#2923),#2905,.F.);
#2925=CARTESIAN_POINT('',(11.1125,6.35,11.1125));
#2926=DIRECTION('',(0.,-1.,0.));
#2927=DIRECTION('',(0.,0.,-1.));
#2928=AXIS2_PLACEMENT_3D('',#2925,#2926,#2927);
#2929=CYLINDRICAL_SURFACE('',#2928,1.5875);
#2930=CARTESIAN_POINT('',(11.1125,6.35,11.1125));
#2931=DIRECTION('',(0.,-1.,0.));
#2932=DIRECTION('',(0.,0.,-1.));
#2933=AXIS2_PLACEMENT_3D('',#2930,#2931,#2932);
#2934=CIRCLE('',#2933,1.5875);
#2935=CARTESIAN_POINT('',(11.1125,6.35,12.7));
#2936=VERTEX_POINT('',#2935);
#2937=EDGE_CURVE('E640',#2936,#2913,#2934,.F.);
#2938=ORIENTED_EDGE('',*,*,#2937,.F.);
#2939=DIRECTION('',(0.,1.,0.));
#2940=VECTOR('',#2939,1.);
#2941=CARTESIAN_POINT('',(11.1125,6.35,12.7));
#2942=LINE('',#2941,#2940);
#2943=EDGE_CURVE('E657',#695,#2936,#2942,.F.);
#2944=ORIENTED_EDGE('',*,*,#2943,.F.);
#2945=ORIENTED_EDGE('',*,*,#754,.F.);
#2946=ORIENTED_EDGE('',*,*,#2920,.F.);
#2947=EDGE_LOOP('',(#2938,#2944,#2945,#2946));
#2948=FACE_BOUND('',#2947,.T.);
#2949=ADVANCED_FACE('F1762',(#2948),#2929,.F.);
#2950=CARTESIAN_POINT('',(12.7,6.35,12.7));
#2951=DIRECTION('',(0.,0.,1.));
#2952=DIRECTION('',(1.,0.,0.));
#2953=AXIS2_PLACEMENT_3D('',#2950,#2951,#2952);
#2954=PLANE('',#2953);
#2955=ORIENTED_EDGE('',*,*,#696,.T.);
#2956=ORIENTED_EDGE('',*,*,#2943,.T.);
#2957=DIRECTION('',(1.,0.,0.));
#2958=VECTOR('',#2957,1.);
#2959=CARTESIAN_POINT('',(12.7,6.35,12.7));
#2960=LINE('',#2959,#2958);
#2961=CARTESIAN_POINT('',(-11.1125,6.35,12.7));
#2962=VERTEX_POINT('',#2961);
#2963=EDGE_CURVE('E638',#2962,#2936,#2960,.T.);
#2964=ORIENTED_EDGE('',*,*,#2963,.F.);
#2965=DIRECTION('',(0.,1.,0.));
#2966=VECTOR('',#2965,1.);
#2967=CARTESIAN_POINT('',(-11.1125,12.7,12.7));
#2968=LINE('',#2967,#2966);
#2969=EDGE_CURVE('E649',#2962,#693,#2968,.T.);
#2970=ORIENTED_EDGE('',*,*,#2969,.T.);
#2971=EDGE_LOOP('',(#2955,#2956,#2964,#2970));
#2972=FACE_BOUND('',#2971,.T.);
#2973=ADVANCED_FACE('F1757',(#2972),#2954,.F.);
#2974=CARTESIAN_POINT('',(-12.7,6.35,-12.7));
#2975=DIRECTION('',(-1.,0.,0.));
#2976=DIRECTION('',(0.,0.,1.));
#2977=AXIS2_PLACEMENT_3D('',#2974,#2975,#2976);
#2978=PLANE('',#2977);
#2979=ORIENTED_EDGE('',*,*,#713,.T.);
#2980=DIRECTION('',(0.,1.,0.));
#2981=VECTOR('',#2980,1.);
#2982=CARTESIAN_POINT('',(-12.7,6.35,11.1125));
#2983=LINE('',#2982,#2981);
#2984=CARTESIAN_POINT('',(-12.7,6.35,11.1125));
#2985=VERTEX_POINT('',#2984);
#2986=EDGE_CURVE('E643',#704,#2985,#2983,.F.);
#2987=ORIENTED_EDGE('',*,*,#2986,.T.);
#2988=DIRECTION('',(0.,0.,1.));
#2989=VECTOR('',#2988,1.);
#2990=CARTESIAN_POINT('',(-12.7,6.35,-12.7));
#2991=LINE('',#2990,#2989);
#2992=CARTESIAN_POINT('',(-12.7,6.35,-11.1125));
#2993=VERTEX_POINT('',#2992);
#2994=EDGE_CURVE('E629',#2993,#2985,#2991,.T.);
#2995=ORIENTED_EDGE('',*,*,#2994,.F.);
#2996=DIRECTION('',(0.,1.,0.));
#2997=VECTOR('',#2996,1.);
#2998=CARTESIAN_POINT('',(-12.7,12.7,-11.1125));
#2999=LINE('',#2998,#2997);
#3000=EDGE_CURVE('E611',#2993,#712,#2999,.T.);
#3001=ORIENTED_EDGE('',*,*,#3000,.T.);
#3002=EDGE_LOOP('',(#2979,#2987,#2995,#3001));
#3003=FACE_BOUND('',#3002,.T.);
#3004=ADVANCED_FACE('F1768',(#3003),#2978,.F.);
#3005=CARTESIAN_POINT('',(-11.1125,6.35,11.1125));
#3006=DIRECTION('',(0.,-1.,0.));
#3007=DIRECTION('',(0.,0.,-1.));
#3008=AXIS2_PLACEMENT_3D('',#3005,#3006,#3007);
#3009=CYLINDRICAL_SURFACE('',#3008,1.5875);
#3010=CARTESIAN_POINT('',(-11.1125,6.35,11.1125));
#3011=DIRECTION('',(0.,-1.,0.));
#3012=DIRECTION('',(0.,0.,-1.));
#3013=AXIS2_PLACEMENT_3D('',#3010,#3011,#3012);
#3014=CIRCLE('',#3013,1.5875);
#3015=EDGE_CURVE('E631',#2985,#2962,#3014,.F.);
#3016=ORIENTED_EDGE('',*,*,#3015,.F.);
#3017=ORIENTED_EDGE('',*,*,#2986,.F.);
#3018=ORIENTED_EDGE('',*,*,#705,.F.);
#3019=ORIENTED_EDGE('',*,*,#2969,.F.);
#3020=EDGE_LOOP('',(#3016,#3017,#3018,#3019));
#3021=FACE_BOUND('',#3020,.T.);
#3022=ADVANCED_FACE('F1766',(#3021),#3009,.F.);
#3023=CARTESIAN_POINT('',(12.7,6.35,12.7));
#3024=DIRECTION('',(0.,-1.,0.));
#3025=DIRECTION('',(0.,0.,-1.));
#3026=AXIS2_PLACEMENT_3D('',#3023,#3024,#3025);
#3027=PLANE('',#3026);
#3028=ORIENTED_EDGE('',*,*,#2914,.T.);
#3029=ORIENTED_EDGE('',*,*,#2888,.T.);
#3030=ORIENTED_EDGE('',*,*,#2858,.T.);
#3031=CARTESIAN_POINT('',(-11.1125,6.35,-11.1125));
#3032=DIRECTION('',(0.,-1.,0.));
#3033=DIRECTION('',(0.,0.,-1.));
#3034=AXIS2_PLACEMENT_3D('',#3031,#3032,#3033);
#3035=CIRCLE('',#3034,1.5875);
#3036=EDGE_CURVE('E605',#2857,#2993,#3035,.F.);
#3037=ORIENTED_EDGE('',*,*,#3036,.T.);
#3038=ORIENTED_EDGE('',*,*,#2994,.T.);
#3039=ORIENTED_EDGE('',*,*,#3015,.T.);
#3040=ORIENTED_EDGE('',*,*,#2963,.T.);
#3041=ORIENTED_EDGE('',*,*,#2937,.T.);
#3042=EDGE_LOOP('',(#3028,#3029,#3030,#3037,#3038,#3039,#3040,#3041));
#3043=FACE_BOUND('',#3042,.T.);
#3044=ADVANCED_FACE('F626',(#3043),#3027,.F.);
#3045=CARTESIAN_POINT('',(-11.1125,6.35,-11.1125));
#3046=DIRECTION('',(0.,-1.,0.));
#3047=DIRECTION('',(0.,0.,-1.));
#3048=AXIS2_PLACEMENT_3D('',#3045,#3046,#3047);
#3049=CYLINDRICAL_SURFACE('',#3048,1.5875);
#3050=ORIENTED_EDGE('',*,*,#3036,.F.);
#3051=ORIENTED_EDGE('',*,*,#2871,.F.);
#3052=ORIENTED_EDGE('',*,*,#722,.F.);
#3053=ORIENTED_EDGE('',*,*,#3000,.F.);
#3054=EDGE_LOOP('',(#3050,#3051,#3052,#3053));
#3055=FACE_BOUND('',#3054,.T.);
#3056=ADVANCED_FACE('F607',(#3055),#3049,.F.);
#3057=CARTESIAN_POINT('',(26.9875,6.35,-11.1125));
#3058=DIRECTION('',(0.,-1.,0.));
#3059=DIRECTION('',(0.,0.,-1.));
#3060=AXIS2_PLACEMENT_3D('',#3057,#3058,#3059);
#3061=CYLINDRICAL_SURFACE('',#3060,1.5875);
#3062=CARTESIAN_POINT('',(26.9875,6.35,-11.1125));
#3063=DIRECTION('',(0.,-1.,0.));
#3064=DIRECTION('',(0.,0.,-1.));
#3065=AXIS2_PLACEMENT_3D('',#3062,#3063,#3064);
#3066=CIRCLE('',#3065,1.5875);
#3067=CARTESIAN_POINT('',(26.9875,6.35,-12.7));
#3068=VERTEX_POINT('',#3067);
#3069=CARTESIAN_POINT('',(25.4,6.35,-11.1125));
#3070=VERTEX_POINT('',#3069);
#3071=EDGE_CURVE('E11',#3068,#3070,#3066,.F.);
#3072=ORIENTED_EDGE('',*,*,#3071,.F.);
#3073=DIRECTION('',(0.,1.,0.));
#3074=VECTOR('',#3073,1.);
#3075=CARTESIAN_POINT('',(26.9875,6.35,-12.7));
#3076=LINE('',#3075,#3074);
#3077=EDGE_CURVE('E1271',#765,#3068,#3076,.F.);
#3078=ORIENTED_EDGE('',*,*,#3077,.F.);
#3079=ORIENTED_EDGE('',*,*,#824,.F.);
#3080=DIRECTION('',(0.,1.,0.));
#3081=VECTOR('',#3080,1.);
#3082=CARTESIAN_POINT('',(25.4,12.7,-11.1125));
#3083=LINE('',#3082,#3081);
#3084=EDGE_CURVE('E1300',#3070,#816,#3083,.T.);
#3085=ORIENTED_EDGE('',*,*,#3084,.F.);
#3086=EDGE_LOOP('',(#3072,#3078,#3079,#3085));
#3087=FACE_BOUND('',#3086,.T.);
#3088=ADVANCED_FACE('F38',(#3087),#3061,.F.);
#3089=CARTESIAN_POINT('',(50.8,6.35,12.7));
#3090=DIRECTION('',(0.,-1.,0.));
#3091=DIRECTION('',(0.,0.,-1.));
#3092=AXIS2_PLACEMENT_3D('',#3089,#3090,#3091);
#3093=PLANE('',#3092);
#3094=DIRECTION('',(0.,0.,-1.));
#3095=VECTOR('',#3094,1.);
#3096=CARTESIAN_POINT('',(50.8,6.35,-12.7));
#3097=LINE('',#3096,#3095);
#3098=CARTESIAN_POINT('',(50.8,6.35,11.1125));
#3099=VERTEX_POINT('',#3098);
#3100=CARTESIAN_POINT('',(50.8,6.35,-11.1125));
#3101=VERTEX_POINT('',#3100);
#3102=EDGE_CURVE('E1280',#3099,#3101,#3097,.T.);
#3103=ORIENTED_EDGE('',*,*,#3102,.T.);
#3104=CARTESIAN_POINT('',(49.2125,6.35,-11.1125));
#3105=DIRECTION('',(0.,-1.,0.));
#3106=DIRECTION('',(0.,0.,-1.));
#3107=AXIS2_PLACEMENT_3D('',#3104,#3105,#3106);
#3108=CIRCLE('',#3107,1.5875);
#3109=CARTESIAN_POINT('',(49.2125,6.35,-12.7));
#3110=VERTEX_POINT('',#3109);
#3111=EDGE_CURVE('E1274',#3101,#3110,#3108,.F.);
#3112=ORIENTED_EDGE('',*,*,#3111,.T.);
#3113=DIRECTION('',(-1.,0.,0.));
#3114=VECTOR('',#3113,1.);
#3115=CARTESIAN_POINT('',(50.8,6.35,-12.7));
#3116=LINE('',#3115,#3114);
#3117=EDGE_CURVE('E1266',#3110,#3068,#3116,.T.);
#3118=ORIENTED_EDGE('',*,*,#3117,.T.);
#3119=ORIENTED_EDGE('',*,*,#3071,.T.);
#3120=DIRECTION('',(0.,0.,1.));
#3121=VECTOR('',#3120,1.);
#3122=CARTESIAN_POINT('',(25.4,6.35,-12.7));
#3123=LINE('',#3122,#3121);
#3124=CARTESIAN_POINT('',(25.4,6.35,11.1125));
#3125=VERTEX_POINT('',#3124);
#3126=EDGE_CURVE('E51',#3070,#3125,#3123,.T.);
#3127=ORIENTED_EDGE('',*,*,#3126,.T.);
#3128=CARTESIAN_POINT('',(26.9875,6.35,11.1125));
#3129=DIRECTION('',(0.,-1.,0.));
#3130=DIRECTION('',(0.,0.,-1.));
#3131=AXIS2_PLACEMENT_3D('',#3128,#3129,#3130);
#3132=CIRCLE('',#3131,1.5875);
#3133=CARTESIAN_POINT('',(26.9875,6.35,12.7));
#3134=VERTEX_POINT('',#3133);
#3135=EDGE_CURVE('E44',#3125,#3134,#3132,.F.);
#3136=ORIENTED_EDGE('',*,*,#3135,.T.);
#3137=DIRECTION('',(1.,0.,0.));
#3138=VECTOR('',#3137,1.);
#3139=CARTESIAN_POINT('',(50.8,6.35,12.7));
#3140=LINE('',#3139,#3138);
#3141=CARTESIAN_POINT('',(49.2125,6.35,12.7));
#3142=VERTEX_POINT('',#3141);
#3143=EDGE_CURVE('E1292',#3134,#3142,#3140,.T.);
#3144=ORIENTED_EDGE('',*,*,#3143,.T.);
#3145=CARTESIAN_POINT('',(49.2125,6.35,11.1125));
#3146=DIRECTION('',(0.,-1.,0.));
#3147=DIRECTION('',(0.,0.,-1.));
#3148=AXIS2_PLACEMENT_3D('',#3145,#3146,#3147);
#3149=CIRCLE('',#3148,1.5875);
#3150=EDGE_CURVE('E1286',#3142,#3099,#3149,.F.);
#3151=ORIENTED_EDGE('',*,*,#3150,.T.);
#3152=EDGE_LOOP('',(#3103,#3112,#3118,#3119,#3127,#3136,#3144,#3151));
#3153=FACE_BOUND('',#3152,.T.);
#3154=ADVANCED_FACE('F1304',(#3153),#3093,.F.);
#3155=CARTESIAN_POINT('',(26.9875,6.35,11.1125));
#3156=DIRECTION('',(0.,-1.,0.));
#3157=DIRECTION('',(0.,0.,-1.));
#3158=AXIS2_PLACEMENT_3D('',#3155,#3156,#3157);
#3159=CYLINDRICAL_SURFACE('',#3158,1.5875);
#3160=ORIENTED_EDGE('',*,*,#3135,.F.);
#3161=DIRECTION('',(0.,1.,0.));
#3162=VECTOR('',#3161,1.);
#3163=CARTESIAN_POINT('',(25.4,6.35,11.1125));
#3164=LINE('',#3163,#3162);
#3165=EDGE_CURVE('E56',#808,#3125,#3164,.F.);
#3166=ORIENTED_EDGE('',*,*,#3165,.F.);
#3167=ORIENTED_EDGE('',*,*,#809,.F.);
#3168=DIRECTION('',(0.,1.,0.));
#3169=VECTOR('',#3168,1.);
#3170=CARTESIAN_POINT('',(26.9875,12.7,12.7));
#3171=LINE('',#3170,#3169);
#3172=EDGE_CURVE('E1295',#3134,#799,#3171,.T.);
#3173=ORIENTED_EDGE('',*,*,#3172,.F.);
#3174=EDGE_LOOP('',(#3160,#3166,#3167,#3173));
#3175=FACE_BOUND('',#3174,.T.);
#3176=ADVANCED_FACE('F1307',(#3175),#3159,.F.);
#3177=CARTESIAN_POINT('',(25.4,6.35,-12.7));
#3178=DIRECTION('',(-1.,0.,0.));
#3179=DIRECTION('',(0.,0.,1.));
#3180=AXIS2_PLACEMENT_3D('',#3177,#3178,#3179);
#3181=PLANE('',#3180);
#3182=ORIENTED_EDGE('',*,*,#817,.T.);
#3183=ORIENTED_EDGE('',*,*,#3165,.T.);
#3184=ORIENTED_EDGE('',*,*,#3126,.F.);
#3185=ORIENTED_EDGE('',*,*,#3084,.T.);
#3186=EDGE_LOOP('',(#3182,#3183,#3184,#3185));
#3187=FACE_BOUND('',#3186,.T.);
#3188=ADVANCED_FACE('F1329',(#3187),#3181,.F.);
#3189=CARTESIAN_POINT('',(50.8,6.35,12.7));
#3190=DIRECTION('',(0.,0.,1.));
#3191=DIRECTION('',(1.,0.,0.));
#3192=AXIS2_PLACEMENT_3D('',#3189,#3190,#3191);
#3193=PLANE('',#3192);
#3194=ORIENTED_EDGE('',*,*,#800,.T.);
#3195=DIRECTION('',(0.,1.,0.));
#3196=VECTOR('',#3195,1.);
#3197=CARTESIAN_POINT('',(49.2125,6.35,12.7));
#3198=LINE('',#3197,#3196);
#3199=EDGE_CURVE('E1289',#791,#3142,#3198,.F.);
#3200=ORIENTED_EDGE('',*,*,#3199,.T.);
#3201=ORIENTED_EDGE('',*,*,#3143,.F.);
#3202=ORIENTED_EDGE('',*,*,#3172,.T.);
#3203=EDGE_LOOP('',(#3194,#3200,#3201,#3202));
#3204=FACE_BOUND('',#3203,.T.);
#3205=ADVANCED_FACE('F1310',(#3204),#3193,.F.);
#3206=CARTESIAN_POINT('',(49.2125,6.35,11.1125));
#3207=DIRECTION('',(0.,-1.,0.));
#3208=DIRECTION('',(0.,0.,-1.));
#3209=AXIS2_PLACEMENT_3D('',#3206,#3207,#3208);
#3210=CYLINDRICAL_SURFACE('',#3209,1.5875);
#3211=ORIENTED_EDGE('',*,*,#3150,.F.);
#3212=ORIENTED_EDGE('',*,*,#3199,.F.);
#3213=ORIENTED_EDGE('',*,*,#792,.F.);
#3214=DIRECTION('',(0.,1.,0.));
#3215=VECTOR('',#3214,1.);
#3216=CARTESIAN_POINT('',(50.8,12.7,11.1125));
#3217=LINE('',#3216,#3215);
#3218=EDGE_CURVE('E1283',#3099,#782,#3217,.T.);
#3219=ORIENTED_EDGE('',*,*,#3218,.F.);
#3220=EDGE_LOOP('',(#3211,#3212,#3213,#3219));
#3221=FACE_BOUND('',#3220,.T.);
#3222=ADVANCED_FACE('F1314',(#3221),#3210,.F.);
#3223=CARTESIAN_POINT('',(50.8,6.35,-12.7));
#3224=DIRECTION('',(1.,0.,0.));
#3225=DIRECTION('',(0.,0.,-1.));
#3226=AXIS2_PLACEMENT_3D('',#3223,#3224,#3225);
#3227=PLANE('',#3226);
#3228=ORIENTED_EDGE('',*,*,#783,.T.);
#3229=DIRECTION('',(0.,1.,0.));
#3230=VECTOR('',#3229,1.);
#3231=CARTESIAN_POINT('',(50.8,6.35,-11.1125));
#3232=LINE('',#3231,#3230);
#3233=EDGE_CURVE('E1277',#774,#3101,#3232,.F.);
#3234=ORIENTED_EDGE('',*,*,#3233,.T.);
#3235=ORIENTED_EDGE('',*,*,#3102,.F.);
#3236=ORIENTED_EDGE('',*,*,#3218,.T.);
#3237=EDGE_LOOP('',(#3228,#3234,#3235,#3236));
#3238=FACE_BOUND('',#3237,.T.);
#3239=ADVANCED_FACE('F1317',(#3238),#3227,.F.);
#3240=CARTESIAN_POINT('',(49.2125,6.35,-11.1125));
#3241=DIRECTION('',(0.,-1.,0.));
#3242=DIRECTION('',(0.,0.,-1.));
#3243=AXIS2_PLACEMENT_3D('',#3240,#3241,#3242);
#3244=CYLINDRICAL_SURFACE('',#3243,1.5875);
#3245=ORIENTED_EDGE('',*,*,#3111,.F.);
#3246=ORIENTED_EDGE('',*,*,#3233,.F.);
#3247=ORIENTED_EDGE('',*,*,#775,.F.);
#3248=DIRECTION('',(0.,1.,0.));
#3249=VECTOR('',#3248,1.);
#3250=CARTESIAN_POINT('',(49.2125,12.7,-12.7));
#3251=LINE('',#3250,#3249);
#3252=EDGE_CURVE('E1268',#3110,#763,#3251,.T.);
#3253=ORIENTED_EDGE('',*,*,#3252,.F.);
#3254=EDGE_LOOP('',(#3245,#3246,#3247,#3253));
#3255=FACE_BOUND('',#3254,.T.);
#3256=ADVANCED_FACE('F1321',(#3255),#3244,.F.);
#3257=CARTESIAN_POINT('',(50.8,6.35,-12.7));
#3258=DIRECTION('',(0.,0.,-1.));
#3259=DIRECTION('',(-1.,0.,0.));
#3260=AXIS2_PLACEMENT_3D('',#3257,#3258,#3259);
#3261=PLANE('',#3260);
#3262=ORIENTED_EDGE('',*,*,#3117,.F.);
#3263=ORIENTED_EDGE('',*,*,#3252,.T.);
#3264=ORIENTED_EDGE('',*,*,#766,.T.);
#3265=ORIENTED_EDGE('',*,*,#3077,.T.);
#3266=EDGE_LOOP('',(#3262,#3263,#3264,#3265));
#3267=FACE_BOUND('',#3266,.T.);
#3268=ADVANCED_FACE('F1324',(#3267),#3261,.F.);
#3269=CLOSED_SHELL('',(#828,#859,#883,#907,#924,#936,#967,#998,#1029,#1060,#1100,#1131,#1162,
#1193,#1224,#1264,#1276,#1288,#1300,#1312,#1343,#1374,#1405,#1436,#1476,#1507,#1538,#1569,#1600,
#1640,#1671,#1702,#1733,#1764,#1804,#1835,#1866,#1897,#1928,#1968,#1999,#2030,#2061,#2092,#2132,
#2163,#2194,#2225,#2256,#2296,#2327,#2358,#2389,#2420,#2460,#2472,#2484,#2496,#2508,#2520,#2532,
#2544,#2556,#2568,#2580,#2592,#2604,#2616,#2628,#2640,#2652,#2664,#2676,#2688,#2700,#2712,#2724,
#2736,#2748,#2760,#2772,#2784,#2796,#2808,#2820,#2832,#2844,#2875,#2900,#2924,#2949,#2973,#3004,
#3022,#3044,#3056,#3088,#3154,#3176,#3188,#3205,#3222,#3239,#3256,#3268));
#3270=MANIFOLD_SOLID_BREP('B2',#3269);
#3271=ADVANCED_BREP_SHAPE_REPRESENTATION('',(#18,#3270),#14);
#3272=SHAPE_DEFINITION_REPRESENTATION(#9,#3271);
ENDSEC;
END-ISO-10303-21;
